VERSION 5.8 ;
BUSBITCHARS "[]" ;
DIVIDERCHAR "/" ;
UNITS
    DATABASE MICRONS 1000 ;
END UNITS

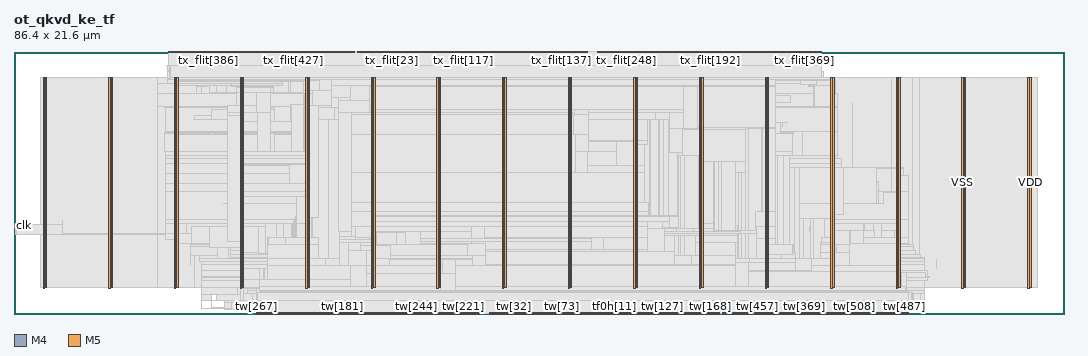
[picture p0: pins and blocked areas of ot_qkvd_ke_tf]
MACRO ot_qkvd_ke_tf
  FOREIGN ot_qkvd_ke_tf 0 0 ;
  CLASS BLOCK ;
  SIZE 86.4 BY 21.6 ;
  PIN clk
    DIRECTION INPUT ;
    USE SIGNAL ;
    PORT
      LAYER M4 ;
        RECT  0 7.248 0.084 7.272 ;
    END
  END clk
  PIN rst_n
    DIRECTION INPUT ;
    USE SIGNAL ;
    PORT
      LAYER M4 ;
        RECT  0 7.344 0.084 7.368 ;
    END
  END rst_n
  PIN tf0h[0]
    DIRECTION INPUT ;
    USE SIGNAL ;
    PORT
      LAYER M5 ;
        RECT  48.336 0 48.36 0.084 ;
    END
  END tf0h[0]
  PIN tf0h[10]
    DIRECTION INPUT ;
    USE SIGNAL ;
    PORT
      LAYER M5 ;
        RECT  49.296 0 49.32 0.084 ;
    END
  END tf0h[10]
  PIN tf0h[11]
    DIRECTION INPUT ;
    USE SIGNAL ;
    PORT
      LAYER M5 ;
        RECT  49.392 0 49.416 0.084 ;
    END
  END tf0h[11]
  PIN tf0h[12]
    DIRECTION INPUT ;
    USE SIGNAL ;
    PORT
      LAYER M5 ;
        RECT  49.488 0 49.512 0.084 ;
    END
  END tf0h[12]
  PIN tf0h[13]
    DIRECTION INPUT ;
    USE SIGNAL ;
    PORT
      LAYER M5 ;
        RECT  49.584 0 49.608 0.084 ;
    END
  END tf0h[13]
  PIN tf0h[14]
    DIRECTION INPUT ;
    USE SIGNAL ;
    PORT
      LAYER M5 ;
        RECT  49.68 0 49.704 0.084 ;
    END
  END tf0h[14]
  PIN tf0h[15]
    DIRECTION INPUT ;
    USE SIGNAL ;
    PORT
      LAYER M5 ;
        RECT  49.776 0 49.8 0.084 ;
    END
  END tf0h[15]
  PIN tf0h[16]
    DIRECTION INPUT ;
    USE SIGNAL ;
    PORT
      LAYER M5 ;
        RECT  49.872 0 49.896 0.084 ;
    END
  END tf0h[16]
  PIN tf0h[17]
    DIRECTION INPUT ;
    USE SIGNAL ;
    PORT
      LAYER M5 ;
        RECT  49.968 0 49.992 0.084 ;
    END
  END tf0h[17]
  PIN tf0h[18]
    DIRECTION INPUT ;
    USE SIGNAL ;
    PORT
      LAYER M5 ;
        RECT  50.064 0 50.088 0.084 ;
    END
  END tf0h[18]
  PIN tf0h[19]
    DIRECTION INPUT ;
    USE SIGNAL ;
    PORT
      LAYER M5 ;
        RECT  50.16 0 50.184 0.084 ;
    END
  END tf0h[19]
  PIN tf0h[1]
    DIRECTION INPUT ;
    USE SIGNAL ;
    PORT
      LAYER M5 ;
        RECT  48.432 0 48.456 0.084 ;
    END
  END tf0h[1]
  PIN tf0h[2]
    DIRECTION INPUT ;
    USE SIGNAL ;
    PORT
      LAYER M5 ;
        RECT  48.528 0 48.552 0.084 ;
    END
  END tf0h[2]
  PIN tf0h[3]
    DIRECTION INPUT ;
    USE SIGNAL ;
    PORT
      LAYER M5 ;
        RECT  48.624 0 48.648 0.084 ;
    END
  END tf0h[3]
  PIN tf0h[4]
    DIRECTION INPUT ;
    USE SIGNAL ;
    PORT
      LAYER M5 ;
        RECT  48.72 0 48.744 0.084 ;
    END
  END tf0h[4]
  PIN tf0h[5]
    DIRECTION INPUT ;
    USE SIGNAL ;
    PORT
      LAYER M5 ;
        RECT  48.816 0 48.84 0.084 ;
    END
  END tf0h[5]
  PIN tf0h[6]
    DIRECTION INPUT ;
    USE SIGNAL ;
    PORT
      LAYER M5 ;
        RECT  48.912 0 48.936 0.084 ;
    END
  END tf0h[6]
  PIN tf0h[7]
    DIRECTION INPUT ;
    USE SIGNAL ;
    PORT
      LAYER M5 ;
        RECT  49.008 0 49.032 0.084 ;
    END
  END tf0h[7]
  PIN tf0h[8]
    DIRECTION INPUT ;
    USE SIGNAL ;
    PORT
      LAYER M5 ;
        RECT  49.104 0 49.128 0.084 ;
    END
  END tf0h[8]
  PIN tf0h[9]
    DIRECTION INPUT ;
    USE SIGNAL ;
    PORT
      LAYER M5 ;
        RECT  49.2 0 49.224 0.084 ;
    END
  END tf0h[9]
  PIN tv0_i
    DIRECTION INPUT ;
    USE SIGNAL ;
    PORT
      LAYER M5 ;
        RECT  50.256 0 50.28 0.084 ;
    END
  END tv0_i
  PIN tw[0]
    DIRECTION INPUT ;
    USE SIGNAL ;
    PORT
      LAYER M5 ;
        RECT  50.352 0 50.376 0.084 ;
    END
  END tw[0]
  PIN tw[100]
    DIRECTION INPUT ;
    USE SIGNAL ;
    PORT
      LAYER M5 ;
        RECT  47.664 0 47.688 0.084 ;
    END
  END tw[100]
  PIN tw[101]
    DIRECTION INPUT ;
    USE SIGNAL ;
    PORT
      LAYER M5 ;
        RECT  47.76 0 47.784 0.084 ;
    END
  END tw[101]
  PIN tw[102]
    DIRECTION INPUT ;
    USE SIGNAL ;
    PORT
      LAYER M5 ;
        RECT  47.856 0 47.88 0.084 ;
    END
  END tw[102]
  PIN tw[103]
    DIRECTION INPUT ;
    USE SIGNAL ;
    PORT
      LAYER M5 ;
        RECT  47.952 0 47.976 0.084 ;
    END
  END tw[103]
  PIN tw[104]
    DIRECTION INPUT ;
    USE SIGNAL ;
    PORT
      LAYER M5 ;
        RECT  48.048 0 48.072 0.084 ;
    END
  END tw[104]
  PIN tw[105]
    DIRECTION INPUT ;
    USE SIGNAL ;
    PORT
      LAYER M5 ;
        RECT  48.144 0 48.168 0.084 ;
    END
  END tw[105]
  PIN tw[106]
    DIRECTION INPUT ;
    USE SIGNAL ;
    PORT
      LAYER M5 ;
        RECT  48.24 0 48.264 0.084 ;
    END
  END tw[106]
  PIN tw[107]
    DIRECTION INPUT ;
    USE SIGNAL ;
    PORT
      LAYER M5 ;
        RECT  51.408 0 51.432 0.084 ;
    END
  END tw[107]
  PIN tw[108]
    DIRECTION INPUT ;
    USE SIGNAL ;
    PORT
      LAYER M5 ;
        RECT  51.504 0 51.528 0.084 ;
    END
  END tw[108]
  PIN tw[109]
    DIRECTION INPUT ;
    USE SIGNAL ;
    PORT
      LAYER M5 ;
        RECT  51.6 0 51.624 0.084 ;
    END
  END tw[109]
  PIN tw[10]
    DIRECTION INPUT ;
    USE SIGNAL ;
    PORT
      LAYER M5 ;
        RECT  51.312 0 51.336 0.084 ;
    END
  END tw[10]
  PIN tw[110]
    DIRECTION INPUT ;
    USE SIGNAL ;
    PORT
      LAYER M5 ;
        RECT  51.696 0 51.72 0.084 ;
    END
  END tw[110]
  PIN tw[111]
    DIRECTION INPUT ;
    USE SIGNAL ;
    PORT
      LAYER M5 ;
        RECT  51.792 0 51.816 0.084 ;
    END
  END tw[111]
  PIN tw[112]
    DIRECTION INPUT ;
    USE SIGNAL ;
    PORT
      LAYER M5 ;
        RECT  51.888 0 51.912 0.084 ;
    END
  END tw[112]
  PIN tw[113]
    DIRECTION INPUT ;
    USE SIGNAL ;
    PORT
      LAYER M5 ;
        RECT  51.984 0 52.008 0.084 ;
    END
  END tw[113]
  PIN tw[114]
    DIRECTION INPUT ;
    USE SIGNAL ;
    PORT
      LAYER M5 ;
        RECT  52.08 0 52.104 0.084 ;
    END
  END tw[114]
  PIN tw[115]
    DIRECTION INPUT ;
    USE SIGNAL ;
    PORT
      LAYER M5 ;
        RECT  52.176 0 52.2 0.084 ;
    END
  END tw[115]
  PIN tw[116]
    DIRECTION INPUT ;
    USE SIGNAL ;
    PORT
      LAYER M5 ;
        RECT  52.272 0 52.296 0.084 ;
    END
  END tw[116]
  PIN tw[117]
    DIRECTION INPUT ;
    USE SIGNAL ;
    PORT
      LAYER M5 ;
        RECT  52.368 0 52.392 0.084 ;
    END
  END tw[117]
  PIN tw[118]
    DIRECTION INPUT ;
    USE SIGNAL ;
    PORT
      LAYER M5 ;
        RECT  52.464 0 52.488 0.084 ;
    END
  END tw[118]
  PIN tw[119]
    DIRECTION INPUT ;
    USE SIGNAL ;
    PORT
      LAYER M5 ;
        RECT  52.56 0 52.584 0.084 ;
    END
  END tw[119]
  PIN tw[11]
    DIRECTION INPUT ;
    USE SIGNAL ;
    PORT
      LAYER M5 ;
        RECT  39.12 0 39.144 0.084 ;
    END
  END tw[11]
  PIN tw[120]
    DIRECTION INPUT ;
    USE SIGNAL ;
    PORT
      LAYER M5 ;
        RECT  52.656 0 52.68 0.084 ;
    END
  END tw[120]
  PIN tw[121]
    DIRECTION INPUT ;
    USE SIGNAL ;
    PORT
      LAYER M5 ;
        RECT  52.752 0 52.776 0.084 ;
    END
  END tw[121]
  PIN tw[122]
    DIRECTION INPUT ;
    USE SIGNAL ;
    PORT
      LAYER M5 ;
        RECT  52.848 0 52.872 0.084 ;
    END
  END tw[122]
  PIN tw[123]
    DIRECTION INPUT ;
    USE SIGNAL ;
    PORT
      LAYER M5 ;
        RECT  52.944 0 52.968 0.084 ;
    END
  END tw[123]
  PIN tw[124]
    DIRECTION INPUT ;
    USE SIGNAL ;
    PORT
      LAYER M5 ;
        RECT  53.04 0 53.064 0.084 ;
    END
  END tw[124]
  PIN tw[125]
    DIRECTION INPUT ;
    USE SIGNAL ;
    PORT
      LAYER M5 ;
        RECT  53.136 0 53.16 0.084 ;
    END
  END tw[125]
  PIN tw[126]
    DIRECTION INPUT ;
    USE SIGNAL ;
    PORT
      LAYER M5 ;
        RECT  53.232 0 53.256 0.084 ;
    END
  END tw[126]
  PIN tw[127]
    DIRECTION INPUT ;
    USE SIGNAL ;
    PORT
      LAYER M5 ;
        RECT  53.328 0 53.352 0.084 ;
    END
  END tw[127]
  PIN tw[128]
    DIRECTION INPUT ;
    USE SIGNAL ;
    PORT
      LAYER M5 ;
        RECT  53.424 0 53.448 0.084 ;
    END
  END tw[128]
  PIN tw[129]
    DIRECTION INPUT ;
    USE SIGNAL ;
    PORT
      LAYER M5 ;
        RECT  53.52 0 53.544 0.084 ;
    END
  END tw[129]
  PIN tw[12]
    DIRECTION INPUT ;
    USE SIGNAL ;
    PORT
      LAYER M5 ;
        RECT  39.216 0 39.24 0.084 ;
    END
  END tw[12]
  PIN tw[130]
    DIRECTION INPUT ;
    USE SIGNAL ;
    PORT
      LAYER M5 ;
        RECT  53.616 0 53.64 0.084 ;
    END
  END tw[130]
  PIN tw[131]
    DIRECTION INPUT ;
    USE SIGNAL ;
    PORT
      LAYER M5 ;
        RECT  53.712 0 53.736 0.084 ;
    END
  END tw[131]
  PIN tw[132]
    DIRECTION INPUT ;
    USE SIGNAL ;
    PORT
      LAYER M5 ;
        RECT  53.808 0 53.832 0.084 ;
    END
  END tw[132]
  PIN tw[133]
    DIRECTION INPUT ;
    USE SIGNAL ;
    PORT
      LAYER M5 ;
        RECT  53.904 0 53.928 0.084 ;
    END
  END tw[133]
  PIN tw[134]
    DIRECTION INPUT ;
    USE SIGNAL ;
    PORT
      LAYER M5 ;
        RECT  54 0 54.024 0.084 ;
    END
  END tw[134]
  PIN tw[135]
    DIRECTION INPUT ;
    USE SIGNAL ;
    PORT
      LAYER M5 ;
        RECT  54.096 0 54.12 0.084 ;
    END
  END tw[135]
  PIN tw[136]
    DIRECTION INPUT ;
    USE SIGNAL ;
    PORT
      LAYER M5 ;
        RECT  54.192 0 54.216 0.084 ;
    END
  END tw[136]
  PIN tw[137]
    DIRECTION INPUT ;
    USE SIGNAL ;
    PORT
      LAYER M5 ;
        RECT  54.288 0 54.312 0.084 ;
    END
  END tw[137]
  PIN tw[138]
    DIRECTION INPUT ;
    USE SIGNAL ;
    PORT
      LAYER M5 ;
        RECT  54.384 0 54.408 0.084 ;
    END
  END tw[138]
  PIN tw[139]
    DIRECTION INPUT ;
    USE SIGNAL ;
    PORT
      LAYER M5 ;
        RECT  54.48 0 54.504 0.084 ;
    END
  END tw[139]
  PIN tw[13]
    DIRECTION INPUT ;
    USE SIGNAL ;
    PORT
      LAYER M5 ;
        RECT  39.312 0 39.336 0.084 ;
    END
  END tw[13]
  PIN tw[140]
    DIRECTION INPUT ;
    USE SIGNAL ;
    PORT
      LAYER M5 ;
        RECT  54.576 0 54.6 0.084 ;
    END
  END tw[140]
  PIN tw[141]
    DIRECTION INPUT ;
    USE SIGNAL ;
    PORT
      LAYER M5 ;
        RECT  54.672 0 54.696 0.084 ;
    END
  END tw[141]
  PIN tw[142]
    DIRECTION INPUT ;
    USE SIGNAL ;
    PORT
      LAYER M5 ;
        RECT  54.768 0 54.792 0.084 ;
    END
  END tw[142]
  PIN tw[143]
    DIRECTION INPUT ;
    USE SIGNAL ;
    PORT
      LAYER M5 ;
        RECT  54.864 0 54.888 0.084 ;
    END
  END tw[143]
  PIN tw[144]
    DIRECTION INPUT ;
    USE SIGNAL ;
    PORT
      LAYER M5 ;
        RECT  54.96 0 54.984 0.084 ;
    END
  END tw[144]
  PIN tw[145]
    DIRECTION INPUT ;
    USE SIGNAL ;
    PORT
      LAYER M5 ;
        RECT  55.056 0 55.08 0.084 ;
    END
  END tw[145]
  PIN tw[146]
    DIRECTION INPUT ;
    USE SIGNAL ;
    PORT
      LAYER M5 ;
        RECT  55.152 0 55.176 0.084 ;
    END
  END tw[146]
  PIN tw[147]
    DIRECTION INPUT ;
    USE SIGNAL ;
    PORT
      LAYER M5 ;
        RECT  55.248 0 55.272 0.084 ;
    END
  END tw[147]
  PIN tw[148]
    DIRECTION INPUT ;
    USE SIGNAL ;
    PORT
      LAYER M5 ;
        RECT  55.344 0 55.368 0.084 ;
    END
  END tw[148]
  PIN tw[149]
    DIRECTION INPUT ;
    USE SIGNAL ;
    PORT
      LAYER M5 ;
        RECT  55.44 0 55.464 0.084 ;
    END
  END tw[149]
  PIN tw[14]
    DIRECTION INPUT ;
    USE SIGNAL ;
    PORT
      LAYER M5 ;
        RECT  39.408 0 39.432 0.084 ;
    END
  END tw[14]
  PIN tw[150]
    DIRECTION INPUT ;
    USE SIGNAL ;
    PORT
      LAYER M5 ;
        RECT  55.536 0 55.56 0.084 ;
    END
  END tw[150]
  PIN tw[151]
    DIRECTION INPUT ;
    USE SIGNAL ;
    PORT
      LAYER M5 ;
        RECT  55.632 0 55.656 0.084 ;
    END
  END tw[151]
  PIN tw[152]
    DIRECTION INPUT ;
    USE SIGNAL ;
    PORT
      LAYER M5 ;
        RECT  55.728 0 55.752 0.084 ;
    END
  END tw[152]
  PIN tw[153]
    DIRECTION INPUT ;
    USE SIGNAL ;
    PORT
      LAYER M5 ;
        RECT  55.824 0 55.848 0.084 ;
    END
  END tw[153]
  PIN tw[154]
    DIRECTION INPUT ;
    USE SIGNAL ;
    PORT
      LAYER M5 ;
        RECT  55.92 0 55.944 0.084 ;
    END
  END tw[154]
  PIN tw[155]
    DIRECTION INPUT ;
    USE SIGNAL ;
    PORT
      LAYER M5 ;
        RECT  56.016 0 56.04 0.084 ;
    END
  END tw[155]
  PIN tw[156]
    DIRECTION INPUT ;
    USE SIGNAL ;
    PORT
      LAYER M5 ;
        RECT  56.112 0 56.136 0.084 ;
    END
  END tw[156]
  PIN tw[157]
    DIRECTION INPUT ;
    USE SIGNAL ;
    PORT
      LAYER M5 ;
        RECT  56.208 0 56.232 0.084 ;
    END
  END tw[157]
  PIN tw[158]
    DIRECTION INPUT ;
    USE SIGNAL ;
    PORT
      LAYER M5 ;
        RECT  56.304 0 56.328 0.084 ;
    END
  END tw[158]
  PIN tw[159]
    DIRECTION INPUT ;
    USE SIGNAL ;
    PORT
      LAYER M5 ;
        RECT  56.4 0 56.424 0.084 ;
    END
  END tw[159]
  PIN tw[15]
    DIRECTION INPUT ;
    USE SIGNAL ;
    PORT
      LAYER M5 ;
        RECT  39.504 0 39.528 0.084 ;
    END
  END tw[15]
  PIN tw[160]
    DIRECTION INPUT ;
    USE SIGNAL ;
    PORT
      LAYER M5 ;
        RECT  56.496 0 56.52 0.084 ;
    END
  END tw[160]
  PIN tw[161]
    DIRECTION INPUT ;
    USE SIGNAL ;
    PORT
      LAYER M5 ;
        RECT  56.592 0 56.616 0.084 ;
    END
  END tw[161]
  PIN tw[162]
    DIRECTION INPUT ;
    USE SIGNAL ;
    PORT
      LAYER M5 ;
        RECT  56.688 0 56.712 0.084 ;
    END
  END tw[162]
  PIN tw[163]
    DIRECTION INPUT ;
    USE SIGNAL ;
    PORT
      LAYER M5 ;
        RECT  56.784 0 56.808 0.084 ;
    END
  END tw[163]
  PIN tw[164]
    DIRECTION INPUT ;
    USE SIGNAL ;
    PORT
      LAYER M5 ;
        RECT  56.88 0 56.904 0.084 ;
    END
  END tw[164]
  PIN tw[165]
    DIRECTION INPUT ;
    USE SIGNAL ;
    PORT
      LAYER M5 ;
        RECT  56.976 0 57 0.084 ;
    END
  END tw[165]
  PIN tw[166]
    DIRECTION INPUT ;
    USE SIGNAL ;
    PORT
      LAYER M5 ;
        RECT  57.072 0 57.096 0.084 ;
    END
  END tw[166]
  PIN tw[167]
    DIRECTION INPUT ;
    USE SIGNAL ;
    PORT
      LAYER M5 ;
        RECT  57.168 0 57.192 0.084 ;
    END
  END tw[167]
  PIN tw[168]
    DIRECTION INPUT ;
    USE SIGNAL ;
    PORT
      LAYER M5 ;
        RECT  57.264 0 57.288 0.084 ;
    END
  END tw[168]
  PIN tw[169]
    DIRECTION INPUT ;
    USE SIGNAL ;
    PORT
      LAYER M5 ;
        RECT  57.36 0 57.384 0.084 ;
    END
  END tw[169]
  PIN tw[16]
    DIRECTION INPUT ;
    USE SIGNAL ;
    PORT
      LAYER M5 ;
        RECT  39.6 0 39.624 0.084 ;
    END
  END tw[16]
  PIN tw[170]
    DIRECTION INPUT ;
    USE SIGNAL ;
    PORT
      LAYER M5 ;
        RECT  57.456 0 57.48 0.084 ;
    END
  END tw[170]
  PIN tw[171]
    DIRECTION INPUT ;
    USE SIGNAL ;
    PORT
      LAYER M5 ;
        RECT  26.064 0 26.088 0.084 ;
    END
  END tw[171]
  PIN tw[172]
    DIRECTION INPUT ;
    USE SIGNAL ;
    PORT
      LAYER M5 ;
        RECT  26.16 0 26.184 0.084 ;
    END
  END tw[172]
  PIN tw[173]
    DIRECTION INPUT ;
    USE SIGNAL ;
    PORT
      LAYER M5 ;
        RECT  26.256 0 26.28 0.084 ;
    END
  END tw[173]
  PIN tw[174]
    DIRECTION INPUT ;
    USE SIGNAL ;
    PORT
      LAYER M5 ;
        RECT  26.352 0 26.376 0.084 ;
    END
  END tw[174]
  PIN tw[175]
    DIRECTION INPUT ;
    USE SIGNAL ;
    PORT
      LAYER M5 ;
        RECT  26.448 0 26.472 0.084 ;
    END
  END tw[175]
  PIN tw[176]
    DIRECTION INPUT ;
    USE SIGNAL ;
    PORT
      LAYER M5 ;
        RECT  26.544 0 26.568 0.084 ;
    END
  END tw[176]
  PIN tw[177]
    DIRECTION INPUT ;
    USE SIGNAL ;
    PORT
      LAYER M5 ;
        RECT  26.64 0 26.664 0.084 ;
    END
  END tw[177]
  PIN tw[178]
    DIRECTION INPUT ;
    USE SIGNAL ;
    PORT
      LAYER M5 ;
        RECT  26.736 0 26.76 0.084 ;
    END
  END tw[178]
  PIN tw[179]
    DIRECTION INPUT ;
    USE SIGNAL ;
    PORT
      LAYER M5 ;
        RECT  26.832 0 26.856 0.084 ;
    END
  END tw[179]
  PIN tw[17]
    DIRECTION INPUT ;
    USE SIGNAL ;
    PORT
      LAYER M5 ;
        RECT  39.696 0 39.72 0.084 ;
    END
  END tw[17]
  PIN tw[180]
    DIRECTION INPUT ;
    USE SIGNAL ;
    PORT
      LAYER M5 ;
        RECT  26.928 0 26.952 0.084 ;
    END
  END tw[180]
  PIN tw[181]
    DIRECTION INPUT ;
    USE SIGNAL ;
    PORT
      LAYER M5 ;
        RECT  27.024 0 27.048 0.084 ;
    END
  END tw[181]
  PIN tw[182]
    DIRECTION INPUT ;
    USE SIGNAL ;
    PORT
      LAYER M5 ;
        RECT  27.12 0 27.144 0.084 ;
    END
  END tw[182]
  PIN tw[183]
    DIRECTION INPUT ;
    USE SIGNAL ;
    PORT
      LAYER M5 ;
        RECT  27.216 0 27.24 0.084 ;
    END
  END tw[183]
  PIN tw[184]
    DIRECTION INPUT ;
    USE SIGNAL ;
    PORT
      LAYER M5 ;
        RECT  27.312 0 27.336 0.084 ;
    END
  END tw[184]
  PIN tw[185]
    DIRECTION INPUT ;
    USE SIGNAL ;
    PORT
      LAYER M5 ;
        RECT  27.408 0 27.432 0.084 ;
    END
  END tw[185]
  PIN tw[186]
    DIRECTION INPUT ;
    USE SIGNAL ;
    PORT
      LAYER M5 ;
        RECT  27.504 0 27.528 0.084 ;
    END
  END tw[186]
  PIN tw[187]
    DIRECTION INPUT ;
    USE SIGNAL ;
    PORT
      LAYER M5 ;
        RECT  27.6 0 27.624 0.084 ;
    END
  END tw[187]
  PIN tw[188]
    DIRECTION INPUT ;
    USE SIGNAL ;
    PORT
      LAYER M5 ;
        RECT  27.696 0 27.72 0.084 ;
    END
  END tw[188]
  PIN tw[189]
    DIRECTION INPUT ;
    USE SIGNAL ;
    PORT
      LAYER M5 ;
        RECT  27.792 0 27.816 0.084 ;
    END
  END tw[189]
  PIN tw[18]
    DIRECTION INPUT ;
    USE SIGNAL ;
    PORT
      LAYER M5 ;
        RECT  39.792 0 39.816 0.084 ;
    END
  END tw[18]
  PIN tw[190]
    DIRECTION INPUT ;
    USE SIGNAL ;
    PORT
      LAYER M5 ;
        RECT  27.888 0 27.912 0.084 ;
    END
  END tw[190]
  PIN tw[191]
    DIRECTION INPUT ;
    USE SIGNAL ;
    PORT
      LAYER M5 ;
        RECT  27.984 0 28.008 0.084 ;
    END
  END tw[191]
  PIN tw[192]
    DIRECTION INPUT ;
    USE SIGNAL ;
    PORT
      LAYER M5 ;
        RECT  28.08 0 28.104 0.084 ;
    END
  END tw[192]
  PIN tw[193]
    DIRECTION INPUT ;
    USE SIGNAL ;
    PORT
      LAYER M5 ;
        RECT  28.176 0 28.2 0.084 ;
    END
  END tw[193]
  PIN tw[194]
    DIRECTION INPUT ;
    USE SIGNAL ;
    PORT
      LAYER M5 ;
        RECT  28.272 0 28.296 0.084 ;
    END
  END tw[194]
  PIN tw[195]
    DIRECTION INPUT ;
    USE SIGNAL ;
    PORT
      LAYER M5 ;
        RECT  28.368 0 28.392 0.084 ;
    END
  END tw[195]
  PIN tw[196]
    DIRECTION INPUT ;
    USE SIGNAL ;
    PORT
      LAYER M5 ;
        RECT  28.464 0 28.488 0.084 ;
    END
  END tw[196]
  PIN tw[197]
    DIRECTION INPUT ;
    USE SIGNAL ;
    PORT
      LAYER M5 ;
        RECT  28.56 0 28.584 0.084 ;
    END
  END tw[197]
  PIN tw[198]
    DIRECTION INPUT ;
    USE SIGNAL ;
    PORT
      LAYER M5 ;
        RECT  28.656 0 28.68 0.084 ;
    END
  END tw[198]
  PIN tw[199]
    DIRECTION INPUT ;
    USE SIGNAL ;
    PORT
      LAYER M5 ;
        RECT  28.752 0 28.776 0.084 ;
    END
  END tw[199]
  PIN tw[19]
    DIRECTION INPUT ;
    USE SIGNAL ;
    PORT
      LAYER M5 ;
        RECT  39.888 0 39.912 0.084 ;
    END
  END tw[19]
  PIN tw[1]
    DIRECTION INPUT ;
    USE SIGNAL ;
    PORT
      LAYER M5 ;
        RECT  50.448 0 50.472 0.084 ;
    END
  END tw[1]
  PIN tw[200]
    DIRECTION INPUT ;
    USE SIGNAL ;
    PORT
      LAYER M5 ;
        RECT  28.848 0 28.872 0.084 ;
    END
  END tw[200]
  PIN tw[201]
    DIRECTION INPUT ;
    USE SIGNAL ;
    PORT
      LAYER M5 ;
        RECT  28.944 0 28.968 0.084 ;
    END
  END tw[201]
  PIN tw[202]
    DIRECTION INPUT ;
    USE SIGNAL ;
    PORT
      LAYER M5 ;
        RECT  29.04 0 29.064 0.084 ;
    END
  END tw[202]
  PIN tw[203]
    DIRECTION INPUT ;
    USE SIGNAL ;
    PORT
      LAYER M5 ;
        RECT  35.28 0 35.304 0.084 ;
    END
  END tw[203]
  PIN tw[204]
    DIRECTION INPUT ;
    USE SIGNAL ;
    PORT
      LAYER M5 ;
        RECT  35.376 0 35.4 0.084 ;
    END
  END tw[204]
  PIN tw[205]
    DIRECTION INPUT ;
    USE SIGNAL ;
    PORT
      LAYER M5 ;
        RECT  35.472 0 35.496 0.084 ;
    END
  END tw[205]
  PIN tw[206]
    DIRECTION INPUT ;
    USE SIGNAL ;
    PORT
      LAYER M5 ;
        RECT  35.568 0 35.592 0.084 ;
    END
  END tw[206]
  PIN tw[207]
    DIRECTION INPUT ;
    USE SIGNAL ;
    PORT
      LAYER M5 ;
        RECT  35.664 0 35.688 0.084 ;
    END
  END tw[207]
  PIN tw[208]
    DIRECTION INPUT ;
    USE SIGNAL ;
    PORT
      LAYER M5 ;
        RECT  35.76 0 35.784 0.084 ;
    END
  END tw[208]
  PIN tw[209]
    DIRECTION INPUT ;
    USE SIGNAL ;
    PORT
      LAYER M5 ;
        RECT  35.856 0 35.88 0.084 ;
    END
  END tw[209]
  PIN tw[20]
    DIRECTION INPUT ;
    USE SIGNAL ;
    PORT
      LAYER M5 ;
        RECT  39.984 0 40.008 0.084 ;
    END
  END tw[20]
  PIN tw[210]
    DIRECTION INPUT ;
    USE SIGNAL ;
    PORT
      LAYER M5 ;
        RECT  35.952 0 35.976 0.084 ;
    END
  END tw[210]
  PIN tw[211]
    DIRECTION INPUT ;
    USE SIGNAL ;
    PORT
      LAYER M5 ;
        RECT  36.048 0 36.072 0.084 ;
    END
  END tw[211]
  PIN tw[212]
    DIRECTION INPUT ;
    USE SIGNAL ;
    PORT
      LAYER M5 ;
        RECT  36.144 0 36.168 0.084 ;
    END
  END tw[212]
  PIN tw[213]
    DIRECTION INPUT ;
    USE SIGNAL ;
    PORT
      LAYER M5 ;
        RECT  36.24 0 36.264 0.084 ;
    END
  END tw[213]
  PIN tw[214]
    DIRECTION INPUT ;
    USE SIGNAL ;
    PORT
      LAYER M5 ;
        RECT  36.336 0 36.36 0.084 ;
    END
  END tw[214]
  PIN tw[215]
    DIRECTION INPUT ;
    USE SIGNAL ;
    PORT
      LAYER M5 ;
        RECT  36.432 0 36.456 0.084 ;
    END
  END tw[215]
  PIN tw[216]
    DIRECTION INPUT ;
    USE SIGNAL ;
    PORT
      LAYER M5 ;
        RECT  36.528 0 36.552 0.084 ;
    END
  END tw[216]
  PIN tw[217]
    DIRECTION INPUT ;
    USE SIGNAL ;
    PORT
      LAYER M5 ;
        RECT  36.624 0 36.648 0.084 ;
    END
  END tw[217]
  PIN tw[218]
    DIRECTION INPUT ;
    USE SIGNAL ;
    PORT
      LAYER M5 ;
        RECT  36.72 0 36.744 0.084 ;
    END
  END tw[218]
  PIN tw[219]
    DIRECTION INPUT ;
    USE SIGNAL ;
    PORT
      LAYER M5 ;
        RECT  36.816 0 36.84 0.084 ;
    END
  END tw[219]
  PIN tw[21]
    DIRECTION INPUT ;
    USE SIGNAL ;
    PORT
      LAYER M5 ;
        RECT  40.08 0 40.104 0.084 ;
    END
  END tw[21]
  PIN tw[220]
    DIRECTION INPUT ;
    USE SIGNAL ;
    PORT
      LAYER M5 ;
        RECT  36.912 0 36.936 0.084 ;
    END
  END tw[220]
  PIN tw[221]
    DIRECTION INPUT ;
    USE SIGNAL ;
    PORT
      LAYER M5 ;
        RECT  37.008 0 37.032 0.084 ;
    END
  END tw[221]
  PIN tw[222]
    DIRECTION INPUT ;
    USE SIGNAL ;
    PORT
      LAYER M5 ;
        RECT  37.104 0 37.128 0.084 ;
    END
  END tw[222]
  PIN tw[223]
    DIRECTION INPUT ;
    USE SIGNAL ;
    PORT
      LAYER M5 ;
        RECT  37.2 0 37.224 0.084 ;
    END
  END tw[223]
  PIN tw[224]
    DIRECTION INPUT ;
    USE SIGNAL ;
    PORT
      LAYER M5 ;
        RECT  37.296 0 37.32 0.084 ;
    END
  END tw[224]
  PIN tw[225]
    DIRECTION INPUT ;
    USE SIGNAL ;
    PORT
      LAYER M5 ;
        RECT  37.392 0 37.416 0.084 ;
    END
  END tw[225]
  PIN tw[226]
    DIRECTION INPUT ;
    USE SIGNAL ;
    PORT
      LAYER M5 ;
        RECT  37.488 0 37.512 0.084 ;
    END
  END tw[226]
  PIN tw[227]
    DIRECTION INPUT ;
    USE SIGNAL ;
    PORT
      LAYER M5 ;
        RECT  37.584 0 37.608 0.084 ;
    END
  END tw[227]
  PIN tw[228]
    DIRECTION INPUT ;
    USE SIGNAL ;
    PORT
      LAYER M5 ;
        RECT  37.68 0 37.704 0.084 ;
    END
  END tw[228]
  PIN tw[229]
    DIRECTION INPUT ;
    USE SIGNAL ;
    PORT
      LAYER M5 ;
        RECT  37.776 0 37.8 0.084 ;
    END
  END tw[229]
  PIN tw[22]
    DIRECTION INPUT ;
    USE SIGNAL ;
    PORT
      LAYER M5 ;
        RECT  40.176 0 40.2 0.084 ;
    END
  END tw[22]
  PIN tw[230]
    DIRECTION INPUT ;
    USE SIGNAL ;
    PORT
      LAYER M5 ;
        RECT  37.872 0 37.896 0.084 ;
    END
  END tw[230]
  PIN tw[231]
    DIRECTION INPUT ;
    USE SIGNAL ;
    PORT
      LAYER M5 ;
        RECT  37.968 0 37.992 0.084 ;
    END
  END tw[231]
  PIN tw[232]
    DIRECTION INPUT ;
    USE SIGNAL ;
    PORT
      LAYER M5 ;
        RECT  38.064 0 38.088 0.084 ;
    END
  END tw[232]
  PIN tw[233]
    DIRECTION INPUT ;
    USE SIGNAL ;
    PORT
      LAYER M5 ;
        RECT  38.16 0 38.184 0.084 ;
    END
  END tw[233]
  PIN tw[234]
    DIRECTION INPUT ;
    USE SIGNAL ;
    PORT
      LAYER M5 ;
        RECT  38.256 0 38.28 0.084 ;
    END
  END tw[234]
  PIN tw[235]
    DIRECTION INPUT ;
    USE SIGNAL ;
    PORT
      LAYER M5 ;
        RECT  32.208 0 32.232 0.084 ;
    END
  END tw[235]
  PIN tw[236]
    DIRECTION INPUT ;
    USE SIGNAL ;
    PORT
      LAYER M5 ;
        RECT  32.304 0 32.328 0.084 ;
    END
  END tw[236]
  PIN tw[237]
    DIRECTION INPUT ;
    USE SIGNAL ;
    PORT
      LAYER M5 ;
        RECT  32.4 0 32.424 0.084 ;
    END
  END tw[237]
  PIN tw[238]
    DIRECTION INPUT ;
    USE SIGNAL ;
    PORT
      LAYER M5 ;
        RECT  32.496 0 32.52 0.084 ;
    END
  END tw[238]
  PIN tw[239]
    DIRECTION INPUT ;
    USE SIGNAL ;
    PORT
      LAYER M5 ;
        RECT  32.592 0 32.616 0.084 ;
    END
  END tw[239]
  PIN tw[23]
    DIRECTION INPUT ;
    USE SIGNAL ;
    PORT
      LAYER M5 ;
        RECT  40.272 0 40.296 0.084 ;
    END
  END tw[23]
  PIN tw[240]
    DIRECTION INPUT ;
    USE SIGNAL ;
    PORT
      LAYER M5 ;
        RECT  32.688 0 32.712 0.084 ;
    END
  END tw[240]
  PIN tw[241]
    DIRECTION INPUT ;
    USE SIGNAL ;
    PORT
      LAYER M5 ;
        RECT  32.784 0 32.808 0.084 ;
    END
  END tw[241]
  PIN tw[242]
    DIRECTION INPUT ;
    USE SIGNAL ;
    PORT
      LAYER M5 ;
        RECT  32.88 0 32.904 0.084 ;
    END
  END tw[242]
  PIN tw[243]
    DIRECTION INPUT ;
    USE SIGNAL ;
    PORT
      LAYER M5 ;
        RECT  32.976 0 33 0.084 ;
    END
  END tw[243]
  PIN tw[244]
    DIRECTION INPUT ;
    USE SIGNAL ;
    PORT
      LAYER M5 ;
        RECT  33.072 0 33.096 0.084 ;
    END
  END tw[244]
  PIN tw[245]
    DIRECTION INPUT ;
    USE SIGNAL ;
    PORT
      LAYER M5 ;
        RECT  33.168 0 33.192 0.084 ;
    END
  END tw[245]
  PIN tw[246]
    DIRECTION INPUT ;
    USE SIGNAL ;
    PORT
      LAYER M5 ;
        RECT  33.264 0 33.288 0.084 ;
    END
  END tw[246]
  PIN tw[247]
    DIRECTION INPUT ;
    USE SIGNAL ;
    PORT
      LAYER M5 ;
        RECT  33.36 0 33.384 0.084 ;
    END
  END tw[247]
  PIN tw[248]
    DIRECTION INPUT ;
    USE SIGNAL ;
    PORT
      LAYER M5 ;
        RECT  33.456 0 33.48 0.084 ;
    END
  END tw[248]
  PIN tw[249]
    DIRECTION INPUT ;
    USE SIGNAL ;
    PORT
      LAYER M5 ;
        RECT  33.552 0 33.576 0.084 ;
    END
  END tw[249]
  PIN tw[24]
    DIRECTION INPUT ;
    USE SIGNAL ;
    PORT
      LAYER M5 ;
        RECT  40.368 0 40.392 0.084 ;
    END
  END tw[24]
  PIN tw[250]
    DIRECTION INPUT ;
    USE SIGNAL ;
    PORT
      LAYER M5 ;
        RECT  33.648 0 33.672 0.084 ;
    END
  END tw[250]
  PIN tw[251]
    DIRECTION INPUT ;
    USE SIGNAL ;
    PORT
      LAYER M5 ;
        RECT  33.744 0 33.768 0.084 ;
    END
  END tw[251]
  PIN tw[252]
    DIRECTION INPUT ;
    USE SIGNAL ;
    PORT
      LAYER M5 ;
        RECT  33.84 0 33.864 0.084 ;
    END
  END tw[252]
  PIN tw[253]
    DIRECTION INPUT ;
    USE SIGNAL ;
    PORT
      LAYER M5 ;
        RECT  33.936 0 33.96 0.084 ;
    END
  END tw[253]
  PIN tw[254]
    DIRECTION INPUT ;
    USE SIGNAL ;
    PORT
      LAYER M5 ;
        RECT  34.032 0 34.056 0.084 ;
    END
  END tw[254]
  PIN tw[255]
    DIRECTION INPUT ;
    USE SIGNAL ;
    PORT
      LAYER M5 ;
        RECT  34.128 0 34.152 0.084 ;
    END
  END tw[255]
  PIN tw[256]
    DIRECTION INPUT ;
    USE SIGNAL ;
    PORT
      LAYER M5 ;
        RECT  34.224 0 34.248 0.084 ;
    END
  END tw[256]
  PIN tw[257]
    DIRECTION INPUT ;
    USE SIGNAL ;
    PORT
      LAYER M5 ;
        RECT  34.32 0 34.344 0.084 ;
    END
  END tw[257]
  PIN tw[258]
    DIRECTION INPUT ;
    USE SIGNAL ;
    PORT
      LAYER M5 ;
        RECT  34.416 0 34.44 0.084 ;
    END
  END tw[258]
  PIN tw[259]
    DIRECTION INPUT ;
    USE SIGNAL ;
    PORT
      LAYER M5 ;
        RECT  34.512 0 34.536 0.084 ;
    END
  END tw[259]
  PIN tw[25]
    DIRECTION INPUT ;
    USE SIGNAL ;
    PORT
      LAYER M5 ;
        RECT  40.464 0 40.488 0.084 ;
    END
  END tw[25]
  PIN tw[260]
    DIRECTION INPUT ;
    USE SIGNAL ;
    PORT
      LAYER M5 ;
        RECT  34.608 0 34.632 0.084 ;
    END
  END tw[260]
  PIN tw[261]
    DIRECTION INPUT ;
    USE SIGNAL ;
    PORT
      LAYER M5 ;
        RECT  34.704 0 34.728 0.084 ;
    END
  END tw[261]
  PIN tw[262]
    DIRECTION INPUT ;
    USE SIGNAL ;
    PORT
      LAYER M5 ;
        RECT  34.8 0 34.824 0.084 ;
    END
  END tw[262]
  PIN tw[263]
    DIRECTION INPUT ;
    USE SIGNAL ;
    PORT
      LAYER M5 ;
        RECT  34.896 0 34.92 0.084 ;
    END
  END tw[263]
  PIN tw[264]
    DIRECTION INPUT ;
    USE SIGNAL ;
    PORT
      LAYER M5 ;
        RECT  34.992 0 35.016 0.084 ;
    END
  END tw[264]
  PIN tw[265]
    DIRECTION INPUT ;
    USE SIGNAL ;
    PORT
      LAYER M5 ;
        RECT  35.088 0 35.112 0.084 ;
    END
  END tw[265]
  PIN tw[266]
    DIRECTION INPUT ;
    USE SIGNAL ;
    PORT
      LAYER M5 ;
        RECT  35.184 0 35.208 0.084 ;
    END
  END tw[266]
  PIN tw[267]
    DIRECTION INPUT ;
    USE SIGNAL ;
    PORT
      LAYER M5 ;
        RECT  19.92 0 19.944 0.084 ;
    END
  END tw[267]
  PIN tw[268]
    DIRECTION INPUT ;
    USE SIGNAL ;
    PORT
      LAYER M5 ;
        RECT  20.016 0 20.04 0.084 ;
    END
  END tw[268]
  PIN tw[269]
    DIRECTION INPUT ;
    USE SIGNAL ;
    PORT
      LAYER M5 ;
        RECT  20.112 0 20.136 0.084 ;
    END
  END tw[269]
  PIN tw[26]
    DIRECTION INPUT ;
    USE SIGNAL ;
    PORT
      LAYER M5 ;
        RECT  40.56 0 40.584 0.084 ;
    END
  END tw[26]
  PIN tw[270]
    DIRECTION INPUT ;
    USE SIGNAL ;
    PORT
      LAYER M5 ;
        RECT  20.208 0 20.232 0.084 ;
    END
  END tw[270]
  PIN tw[271]
    DIRECTION INPUT ;
    USE SIGNAL ;
    PORT
      LAYER M5 ;
        RECT  20.304 0 20.328 0.084 ;
    END
  END tw[271]
  PIN tw[272]
    DIRECTION INPUT ;
    USE SIGNAL ;
    PORT
      LAYER M5 ;
        RECT  20.4 0 20.424 0.084 ;
    END
  END tw[272]
  PIN tw[273]
    DIRECTION INPUT ;
    USE SIGNAL ;
    PORT
      LAYER M5 ;
        RECT  20.496 0 20.52 0.084 ;
    END
  END tw[273]
  PIN tw[274]
    DIRECTION INPUT ;
    USE SIGNAL ;
    PORT
      LAYER M5 ;
        RECT  20.592 0 20.616 0.084 ;
    END
  END tw[274]
  PIN tw[275]
    DIRECTION INPUT ;
    USE SIGNAL ;
    PORT
      LAYER M5 ;
        RECT  20.688 0 20.712 0.084 ;
    END
  END tw[275]
  PIN tw[276]
    DIRECTION INPUT ;
    USE SIGNAL ;
    PORT
      LAYER M5 ;
        RECT  20.784 0 20.808 0.084 ;
    END
  END tw[276]
  PIN tw[277]
    DIRECTION INPUT ;
    USE SIGNAL ;
    PORT
      LAYER M5 ;
        RECT  20.88 0 20.904 0.084 ;
    END
  END tw[277]
  PIN tw[278]
    DIRECTION INPUT ;
    USE SIGNAL ;
    PORT
      LAYER M5 ;
        RECT  20.976 0 21 0.084 ;
    END
  END tw[278]
  PIN tw[279]
    DIRECTION INPUT ;
    USE SIGNAL ;
    PORT
      LAYER M5 ;
        RECT  21.072 0 21.096 0.084 ;
    END
  END tw[279]
  PIN tw[27]
    DIRECTION INPUT ;
    USE SIGNAL ;
    PORT
      LAYER M5 ;
        RECT  40.656 0 40.68 0.084 ;
    END
  END tw[27]
  PIN tw[280]
    DIRECTION INPUT ;
    USE SIGNAL ;
    PORT
      LAYER M5 ;
        RECT  21.168 0 21.192 0.084 ;
    END
  END tw[280]
  PIN tw[281]
    DIRECTION INPUT ;
    USE SIGNAL ;
    PORT
      LAYER M5 ;
        RECT  21.264 0 21.288 0.084 ;
    END
  END tw[281]
  PIN tw[282]
    DIRECTION INPUT ;
    USE SIGNAL ;
    PORT
      LAYER M5 ;
        RECT  21.36 0 21.384 0.084 ;
    END
  END tw[282]
  PIN tw[283]
    DIRECTION INPUT ;
    USE SIGNAL ;
    PORT
      LAYER M5 ;
        RECT  21.456 0 21.48 0.084 ;
    END
  END tw[283]
  PIN tw[284]
    DIRECTION INPUT ;
    USE SIGNAL ;
    PORT
      LAYER M5 ;
        RECT  21.552 0 21.576 0.084 ;
    END
  END tw[284]
  PIN tw[285]
    DIRECTION INPUT ;
    USE SIGNAL ;
    PORT
      LAYER M5 ;
        RECT  21.648 0 21.672 0.084 ;
    END
  END tw[285]
  PIN tw[286]
    DIRECTION INPUT ;
    USE SIGNAL ;
    PORT
      LAYER M5 ;
        RECT  21.744 0 21.768 0.084 ;
    END
  END tw[286]
  PIN tw[287]
    DIRECTION INPUT ;
    USE SIGNAL ;
    PORT
      LAYER M5 ;
        RECT  21.84 0 21.864 0.084 ;
    END
  END tw[287]
  PIN tw[288]
    DIRECTION INPUT ;
    USE SIGNAL ;
    PORT
      LAYER M5 ;
        RECT  21.936 0 21.96 0.084 ;
    END
  END tw[288]
  PIN tw[289]
    DIRECTION INPUT ;
    USE SIGNAL ;
    PORT
      LAYER M5 ;
        RECT  22.032 0 22.056 0.084 ;
    END
  END tw[289]
  PIN tw[28]
    DIRECTION INPUT ;
    USE SIGNAL ;
    PORT
      LAYER M5 ;
        RECT  40.752 0 40.776 0.084 ;
    END
  END tw[28]
  PIN tw[290]
    DIRECTION INPUT ;
    USE SIGNAL ;
    PORT
      LAYER M5 ;
        RECT  22.128 0 22.152 0.084 ;
    END
  END tw[290]
  PIN tw[291]
    DIRECTION INPUT ;
    USE SIGNAL ;
    PORT
      LAYER M5 ;
        RECT  22.224 0 22.248 0.084 ;
    END
  END tw[291]
  PIN tw[292]
    DIRECTION INPUT ;
    USE SIGNAL ;
    PORT
      LAYER M5 ;
        RECT  22.32 0 22.344 0.084 ;
    END
  END tw[292]
  PIN tw[293]
    DIRECTION INPUT ;
    USE SIGNAL ;
    PORT
      LAYER M5 ;
        RECT  22.416 0 22.44 0.084 ;
    END
  END tw[293]
  PIN tw[294]
    DIRECTION INPUT ;
    USE SIGNAL ;
    PORT
      LAYER M5 ;
        RECT  22.512 0 22.536 0.084 ;
    END
  END tw[294]
  PIN tw[295]
    DIRECTION INPUT ;
    USE SIGNAL ;
    PORT
      LAYER M5 ;
        RECT  22.608 0 22.632 0.084 ;
    END
  END tw[295]
  PIN tw[296]
    DIRECTION INPUT ;
    USE SIGNAL ;
    PORT
      LAYER M5 ;
        RECT  22.704 0 22.728 0.084 ;
    END
  END tw[296]
  PIN tw[297]
    DIRECTION INPUT ;
    USE SIGNAL ;
    PORT
      LAYER M5 ;
        RECT  22.8 0 22.824 0.084 ;
    END
  END tw[297]
  PIN tw[298]
    DIRECTION INPUT ;
    USE SIGNAL ;
    PORT
      LAYER M5 ;
        RECT  22.896 0 22.92 0.084 ;
    END
  END tw[298]
  PIN tw[299]
    DIRECTION INPUT ;
    USE SIGNAL ;
    PORT
      LAYER M5 ;
        RECT  22.992 0 23.016 0.084 ;
    END
  END tw[299]
  PIN tw[29]
    DIRECTION INPUT ;
    USE SIGNAL ;
    PORT
      LAYER M5 ;
        RECT  40.848 0 40.872 0.084 ;
    END
  END tw[29]
  PIN tw[2]
    DIRECTION INPUT ;
    USE SIGNAL ;
    PORT
      LAYER M5 ;
        RECT  50.544 0 50.568 0.084 ;
    END
  END tw[2]
  PIN tw[300]
    DIRECTION INPUT ;
    USE SIGNAL ;
    PORT
      LAYER M5 ;
        RECT  23.088 0 23.112 0.084 ;
    END
  END tw[300]
  PIN tw[301]
    DIRECTION INPUT ;
    USE SIGNAL ;
    PORT
      LAYER M5 ;
        RECT  23.184 0 23.208 0.084 ;
    END
  END tw[301]
  PIN tw[302]
    DIRECTION INPUT ;
    USE SIGNAL ;
    PORT
      LAYER M5 ;
        RECT  23.28 0 23.304 0.084 ;
    END
  END tw[302]
  PIN tw[303]
    DIRECTION INPUT ;
    USE SIGNAL ;
    PORT
      LAYER M5 ;
        RECT  23.376 0 23.4 0.084 ;
    END
  END tw[303]
  PIN tw[304]
    DIRECTION INPUT ;
    USE SIGNAL ;
    PORT
      LAYER M5 ;
        RECT  23.472 0 23.496 0.084 ;
    END
  END tw[304]
  PIN tw[305]
    DIRECTION INPUT ;
    USE SIGNAL ;
    PORT
      LAYER M5 ;
        RECT  23.568 0 23.592 0.084 ;
    END
  END tw[305]
  PIN tw[306]
    DIRECTION INPUT ;
    USE SIGNAL ;
    PORT
      LAYER M5 ;
        RECT  23.664 0 23.688 0.084 ;
    END
  END tw[306]
  PIN tw[307]
    DIRECTION INPUT ;
    USE SIGNAL ;
    PORT
      LAYER M5 ;
        RECT  23.76 0 23.784 0.084 ;
    END
  END tw[307]
  PIN tw[308]
    DIRECTION INPUT ;
    USE SIGNAL ;
    PORT
      LAYER M5 ;
        RECT  23.856 0 23.88 0.084 ;
    END
  END tw[308]
  PIN tw[309]
    DIRECTION INPUT ;
    USE SIGNAL ;
    PORT
      LAYER M5 ;
        RECT  23.952 0 23.976 0.084 ;
    END
  END tw[309]
  PIN tw[30]
    DIRECTION INPUT ;
    USE SIGNAL ;
    PORT
      LAYER M5 ;
        RECT  40.944 0 40.968 0.084 ;
    END
  END tw[30]
  PIN tw[310]
    DIRECTION INPUT ;
    USE SIGNAL ;
    PORT
      LAYER M5 ;
        RECT  24.048 0 24.072 0.084 ;
    END
  END tw[310]
  PIN tw[311]
    DIRECTION INPUT ;
    USE SIGNAL ;
    PORT
      LAYER M5 ;
        RECT  24.144 0 24.168 0.084 ;
    END
  END tw[311]
  PIN tw[312]
    DIRECTION INPUT ;
    USE SIGNAL ;
    PORT
      LAYER M5 ;
        RECT  24.24 0 24.264 0.084 ;
    END
  END tw[312]
  PIN tw[313]
    DIRECTION INPUT ;
    USE SIGNAL ;
    PORT
      LAYER M5 ;
        RECT  24.336 0 24.36 0.084 ;
    END
  END tw[313]
  PIN tw[314]
    DIRECTION INPUT ;
    USE SIGNAL ;
    PORT
      LAYER M5 ;
        RECT  24.432 0 24.456 0.084 ;
    END
  END tw[314]
  PIN tw[315]
    DIRECTION INPUT ;
    USE SIGNAL ;
    PORT
      LAYER M5 ;
        RECT  24.528 0 24.552 0.084 ;
    END
  END tw[315]
  PIN tw[316]
    DIRECTION INPUT ;
    USE SIGNAL ;
    PORT
      LAYER M5 ;
        RECT  24.624 0 24.648 0.084 ;
    END
  END tw[316]
  PIN tw[317]
    DIRECTION INPUT ;
    USE SIGNAL ;
    PORT
      LAYER M5 ;
        RECT  24.72 0 24.744 0.084 ;
    END
  END tw[317]
  PIN tw[318]
    DIRECTION INPUT ;
    USE SIGNAL ;
    PORT
      LAYER M5 ;
        RECT  24.816 0 24.84 0.084 ;
    END
  END tw[318]
  PIN tw[319]
    DIRECTION INPUT ;
    USE SIGNAL ;
    PORT
      LAYER M5 ;
        RECT  24.912 0 24.936 0.084 ;
    END
  END tw[319]
  PIN tw[31]
    DIRECTION INPUT ;
    USE SIGNAL ;
    PORT
      LAYER M5 ;
        RECT  41.04 0 41.064 0.084 ;
    END
  END tw[31]
  PIN tw[320]
    DIRECTION INPUT ;
    USE SIGNAL ;
    PORT
      LAYER M5 ;
        RECT  25.008 0 25.032 0.084 ;
    END
  END tw[320]
  PIN tw[321]
    DIRECTION INPUT ;
    USE SIGNAL ;
    PORT
      LAYER M5 ;
        RECT  25.104 0 25.128 0.084 ;
    END
  END tw[321]
  PIN tw[322]
    DIRECTION INPUT ;
    USE SIGNAL ;
    PORT
      LAYER M5 ;
        RECT  25.2 0 25.224 0.084 ;
    END
  END tw[322]
  PIN tw[323]
    DIRECTION INPUT ;
    USE SIGNAL ;
    PORT
      LAYER M5 ;
        RECT  25.296 0 25.32 0.084 ;
    END
  END tw[323]
  PIN tw[324]
    DIRECTION INPUT ;
    USE SIGNAL ;
    PORT
      LAYER M5 ;
        RECT  25.392 0 25.416 0.084 ;
    END
  END tw[324]
  PIN tw[325]
    DIRECTION INPUT ;
    USE SIGNAL ;
    PORT
      LAYER M5 ;
        RECT  25.488 0 25.512 0.084 ;
    END
  END tw[325]
  PIN tw[326]
    DIRECTION INPUT ;
    USE SIGNAL ;
    PORT
      LAYER M5 ;
        RECT  25.584 0 25.608 0.084 ;
    END
  END tw[326]
  PIN tw[327]
    DIRECTION INPUT ;
    USE SIGNAL ;
    PORT
      LAYER M5 ;
        RECT  25.68 0 25.704 0.084 ;
    END
  END tw[327]
  PIN tw[328]
    DIRECTION INPUT ;
    USE SIGNAL ;
    PORT
      LAYER M5 ;
        RECT  25.776 0 25.8 0.084 ;
    END
  END tw[328]
  PIN tw[329]
    DIRECTION INPUT ;
    USE SIGNAL ;
    PORT
      LAYER M5 ;
        RECT  25.872 0 25.896 0.084 ;
    END
  END tw[329]
  PIN tw[32]
    DIRECTION INPUT ;
    USE SIGNAL ;
    PORT
      LAYER M5 ;
        RECT  41.136 0 41.16 0.084 ;
    END
  END tw[32]
  PIN tw[330]
    DIRECTION INPUT ;
    USE SIGNAL ;
    PORT
      LAYER M5 ;
        RECT  25.968 0 25.992 0.084 ;
    END
  END tw[330]
  PIN tw[331]
    DIRECTION INPUT ;
    USE SIGNAL ;
    PORT
      LAYER M5 ;
        RECT  29.136 0 29.16 0.084 ;
    END
  END tw[331]
  PIN tw[332]
    DIRECTION INPUT ;
    USE SIGNAL ;
    PORT
      LAYER M5 ;
        RECT  29.232 0 29.256 0.084 ;
    END
  END tw[332]
  PIN tw[333]
    DIRECTION INPUT ;
    USE SIGNAL ;
    PORT
      LAYER M5 ;
        RECT  29.328 0 29.352 0.084 ;
    END
  END tw[333]
  PIN tw[334]
    DIRECTION INPUT ;
    USE SIGNAL ;
    PORT
      LAYER M5 ;
        RECT  29.424 0 29.448 0.084 ;
    END
  END tw[334]
  PIN tw[335]
    DIRECTION INPUT ;
    USE SIGNAL ;
    PORT
      LAYER M5 ;
        RECT  29.52 0 29.544 0.084 ;
    END
  END tw[335]
  PIN tw[336]
    DIRECTION INPUT ;
    USE SIGNAL ;
    PORT
      LAYER M5 ;
        RECT  29.616 0 29.64 0.084 ;
    END
  END tw[336]
  PIN tw[337]
    DIRECTION INPUT ;
    USE SIGNAL ;
    PORT
      LAYER M5 ;
        RECT  29.712 0 29.736 0.084 ;
    END
  END tw[337]
  PIN tw[338]
    DIRECTION INPUT ;
    USE SIGNAL ;
    PORT
      LAYER M5 ;
        RECT  29.808 0 29.832 0.084 ;
    END
  END tw[338]
  PIN tw[339]
    DIRECTION INPUT ;
    USE SIGNAL ;
    PORT
      LAYER M5 ;
        RECT  29.904 0 29.928 0.084 ;
    END
  END tw[339]
  PIN tw[33]
    DIRECTION INPUT ;
    USE SIGNAL ;
    PORT
      LAYER M5 ;
        RECT  41.232 0 41.256 0.084 ;
    END
  END tw[33]
  PIN tw[340]
    DIRECTION INPUT ;
    USE SIGNAL ;
    PORT
      LAYER M5 ;
        RECT  30 0 30.024 0.084 ;
    END
  END tw[340]
  PIN tw[341]
    DIRECTION INPUT ;
    USE SIGNAL ;
    PORT
      LAYER M5 ;
        RECT  30.096 0 30.12 0.084 ;
    END
  END tw[341]
  PIN tw[342]
    DIRECTION INPUT ;
    USE SIGNAL ;
    PORT
      LAYER M5 ;
        RECT  30.192 0 30.216 0.084 ;
    END
  END tw[342]
  PIN tw[343]
    DIRECTION INPUT ;
    USE SIGNAL ;
    PORT
      LAYER M5 ;
        RECT  30.288 0 30.312 0.084 ;
    END
  END tw[343]
  PIN tw[344]
    DIRECTION INPUT ;
    USE SIGNAL ;
    PORT
      LAYER M5 ;
        RECT  30.384 0 30.408 0.084 ;
    END
  END tw[344]
  PIN tw[345]
    DIRECTION INPUT ;
    USE SIGNAL ;
    PORT
      LAYER M5 ;
        RECT  30.48 0 30.504 0.084 ;
    END
  END tw[345]
  PIN tw[346]
    DIRECTION INPUT ;
    USE SIGNAL ;
    PORT
      LAYER M5 ;
        RECT  30.576 0 30.6 0.084 ;
    END
  END tw[346]
  PIN tw[347]
    DIRECTION INPUT ;
    USE SIGNAL ;
    PORT
      LAYER M5 ;
        RECT  30.672 0 30.696 0.084 ;
    END
  END tw[347]
  PIN tw[348]
    DIRECTION INPUT ;
    USE SIGNAL ;
    PORT
      LAYER M5 ;
        RECT  30.768 0 30.792 0.084 ;
    END
  END tw[348]
  PIN tw[349]
    DIRECTION INPUT ;
    USE SIGNAL ;
    PORT
      LAYER M5 ;
        RECT  30.864 0 30.888 0.084 ;
    END
  END tw[349]
  PIN tw[34]
    DIRECTION INPUT ;
    USE SIGNAL ;
    PORT
      LAYER M5 ;
        RECT  41.328 0 41.352 0.084 ;
    END
  END tw[34]
  PIN tw[350]
    DIRECTION INPUT ;
    USE SIGNAL ;
    PORT
      LAYER M5 ;
        RECT  30.96 0 30.984 0.084 ;
    END
  END tw[350]
  PIN tw[351]
    DIRECTION INPUT ;
    USE SIGNAL ;
    PORT
      LAYER M5 ;
        RECT  31.056 0 31.08 0.084 ;
    END
  END tw[351]
  PIN tw[352]
    DIRECTION INPUT ;
    USE SIGNAL ;
    PORT
      LAYER M5 ;
        RECT  31.152 0 31.176 0.084 ;
    END
  END tw[352]
  PIN tw[353]
    DIRECTION INPUT ;
    USE SIGNAL ;
    PORT
      LAYER M5 ;
        RECT  31.248 0 31.272 0.084 ;
    END
  END tw[353]
  PIN tw[354]
    DIRECTION INPUT ;
    USE SIGNAL ;
    PORT
      LAYER M5 ;
        RECT  31.344 0 31.368 0.084 ;
    END
  END tw[354]
  PIN tw[355]
    DIRECTION INPUT ;
    USE SIGNAL ;
    PORT
      LAYER M5 ;
        RECT  31.44 0 31.464 0.084 ;
    END
  END tw[355]
  PIN tw[356]
    DIRECTION INPUT ;
    USE SIGNAL ;
    PORT
      LAYER M5 ;
        RECT  31.536 0 31.56 0.084 ;
    END
  END tw[356]
  PIN tw[357]
    DIRECTION INPUT ;
    USE SIGNAL ;
    PORT
      LAYER M5 ;
        RECT  31.632 0 31.656 0.084 ;
    END
  END tw[357]
  PIN tw[358]
    DIRECTION INPUT ;
    USE SIGNAL ;
    PORT
      LAYER M5 ;
        RECT  31.728 0 31.752 0.084 ;
    END
  END tw[358]
  PIN tw[359]
    DIRECTION INPUT ;
    USE SIGNAL ;
    PORT
      LAYER M5 ;
        RECT  31.824 0 31.848 0.084 ;
    END
  END tw[359]
  PIN tw[35]
    DIRECTION INPUT ;
    USE SIGNAL ;
    PORT
      LAYER M5 ;
        RECT  41.424 0 41.448 0.084 ;
    END
  END tw[35]
  PIN tw[360]
    DIRECTION INPUT ;
    USE SIGNAL ;
    PORT
      LAYER M5 ;
        RECT  31.92 0 31.944 0.084 ;
    END
  END tw[360]
  PIN tw[361]
    DIRECTION INPUT ;
    USE SIGNAL ;
    PORT
      LAYER M5 ;
        RECT  32.016 0 32.04 0.084 ;
    END
  END tw[361]
  PIN tw[362]
    DIRECTION INPUT ;
    USE SIGNAL ;
    PORT
      LAYER M5 ;
        RECT  32.112 0 32.136 0.084 ;
    END
  END tw[362]
  PIN tw[363]
    DIRECTION INPUT ;
    USE SIGNAL ;
    PORT
      LAYER M5 ;
        RECT  64.464 0 64.488 0.084 ;
    END
  END tw[363]
  PIN tw[364]
    DIRECTION INPUT ;
    USE SIGNAL ;
    PORT
      LAYER M5 ;
        RECT  64.56 0 64.584 0.084 ;
    END
  END tw[364]
  PIN tw[365]
    DIRECTION INPUT ;
    USE SIGNAL ;
    PORT
      LAYER M5 ;
        RECT  64.656 0 64.68 0.084 ;
    END
  END tw[365]
  PIN tw[366]
    DIRECTION INPUT ;
    USE SIGNAL ;
    PORT
      LAYER M5 ;
        RECT  64.752 0 64.776 0.084 ;
    END
  END tw[366]
  PIN tw[367]
    DIRECTION INPUT ;
    USE SIGNAL ;
    PORT
      LAYER M5 ;
        RECT  64.848 0 64.872 0.084 ;
    END
  END tw[367]
  PIN tw[368]
    DIRECTION INPUT ;
    USE SIGNAL ;
    PORT
      LAYER M5 ;
        RECT  64.944 0 64.968 0.084 ;
    END
  END tw[368]
  PIN tw[369]
    DIRECTION INPUT ;
    USE SIGNAL ;
    PORT
      LAYER M5 ;
        RECT  65.04 0 65.064 0.084 ;
    END
  END tw[369]
  PIN tw[36]
    DIRECTION INPUT ;
    USE SIGNAL ;
    PORT
      LAYER M5 ;
        RECT  41.52 0 41.544 0.084 ;
    END
  END tw[36]
  PIN tw[370]
    DIRECTION INPUT ;
    USE SIGNAL ;
    PORT
      LAYER M5 ;
        RECT  65.136 0 65.16 0.084 ;
    END
  END tw[370]
  PIN tw[371]
    DIRECTION INPUT ;
    USE SIGNAL ;
    PORT
      LAYER M5 ;
        RECT  65.232 0 65.256 0.084 ;
    END
  END tw[371]
  PIN tw[372]
    DIRECTION INPUT ;
    USE SIGNAL ;
    PORT
      LAYER M5 ;
        RECT  65.328 0 65.352 0.084 ;
    END
  END tw[372]
  PIN tw[373]
    DIRECTION INPUT ;
    USE SIGNAL ;
    PORT
      LAYER M5 ;
        RECT  65.424 0 65.448 0.084 ;
    END
  END tw[373]
  PIN tw[374]
    DIRECTION INPUT ;
    USE SIGNAL ;
    PORT
      LAYER M5 ;
        RECT  65.52 0 65.544 0.084 ;
    END
  END tw[374]
  PIN tw[375]
    DIRECTION INPUT ;
    USE SIGNAL ;
    PORT
      LAYER M5 ;
        RECT  65.616 0 65.64 0.084 ;
    END
  END tw[375]
  PIN tw[376]
    DIRECTION INPUT ;
    USE SIGNAL ;
    PORT
      LAYER M5 ;
        RECT  65.712 0 65.736 0.084 ;
    END
  END tw[376]
  PIN tw[377]
    DIRECTION INPUT ;
    USE SIGNAL ;
    PORT
      LAYER M5 ;
        RECT  65.808 0 65.832 0.084 ;
    END
  END tw[377]
  PIN tw[378]
    DIRECTION INPUT ;
    USE SIGNAL ;
    PORT
      LAYER M5 ;
        RECT  65.904 0 65.928 0.084 ;
    END
  END tw[378]
  PIN tw[379]
    DIRECTION INPUT ;
    USE SIGNAL ;
    PORT
      LAYER M5 ;
        RECT  66 0 66.024 0.084 ;
    END
  END tw[379]
  PIN tw[37]
    DIRECTION INPUT ;
    USE SIGNAL ;
    PORT
      LAYER M5 ;
        RECT  41.616 0 41.64 0.084 ;
    END
  END tw[37]
  PIN tw[380]
    DIRECTION INPUT ;
    USE SIGNAL ;
    PORT
      LAYER M5 ;
        RECT  66.096 0 66.12 0.084 ;
    END
  END tw[380]
  PIN tw[381]
    DIRECTION INPUT ;
    USE SIGNAL ;
    PORT
      LAYER M5 ;
        RECT  66.192 0 66.216 0.084 ;
    END
  END tw[381]
  PIN tw[382]
    DIRECTION INPUT ;
    USE SIGNAL ;
    PORT
      LAYER M5 ;
        RECT  66.288 0 66.312 0.084 ;
    END
  END tw[382]
  PIN tw[383]
    DIRECTION INPUT ;
    USE SIGNAL ;
    PORT
      LAYER M5 ;
        RECT  66.384 0 66.408 0.084 ;
    END
  END tw[383]
  PIN tw[384]
    DIRECTION INPUT ;
    USE SIGNAL ;
    PORT
      LAYER M5 ;
        RECT  66.48 0 66.504 0.084 ;
    END
  END tw[384]
  PIN tw[385]
    DIRECTION INPUT ;
    USE SIGNAL ;
    PORT
      LAYER M5 ;
        RECT  66.576 0 66.6 0.084 ;
    END
  END tw[385]
  PIN tw[386]
    DIRECTION INPUT ;
    USE SIGNAL ;
    PORT
      LAYER M5 ;
        RECT  66.672 0 66.696 0.084 ;
    END
  END tw[386]
  PIN tw[387]
    DIRECTION INPUT ;
    USE SIGNAL ;
    PORT
      LAYER M5 ;
        RECT  66.768 0 66.792 0.084 ;
    END
  END tw[387]
  PIN tw[388]
    DIRECTION INPUT ;
    USE SIGNAL ;
    PORT
      LAYER M5 ;
        RECT  66.864 0 66.888 0.084 ;
    END
  END tw[388]
  PIN tw[389]
    DIRECTION INPUT ;
    USE SIGNAL ;
    PORT
      LAYER M5 ;
        RECT  66.96 0 66.984 0.084 ;
    END
  END tw[389]
  PIN tw[38]
    DIRECTION INPUT ;
    USE SIGNAL ;
    PORT
      LAYER M5 ;
        RECT  41.712 0 41.736 0.084 ;
    END
  END tw[38]
  PIN tw[390]
    DIRECTION INPUT ;
    USE SIGNAL ;
    PORT
      LAYER M5 ;
        RECT  67.056 0 67.08 0.084 ;
    END
  END tw[390]
  PIN tw[391]
    DIRECTION INPUT ;
    USE SIGNAL ;
    PORT
      LAYER M5 ;
        RECT  67.152 0 67.176 0.084 ;
    END
  END tw[391]
  PIN tw[392]
    DIRECTION INPUT ;
    USE SIGNAL ;
    PORT
      LAYER M5 ;
        RECT  67.248 0 67.272 0.084 ;
    END
  END tw[392]
  PIN tw[393]
    DIRECTION INPUT ;
    USE SIGNAL ;
    PORT
      LAYER M5 ;
        RECT  67.344 0 67.368 0.084 ;
    END
  END tw[393]
  PIN tw[394]
    DIRECTION INPUT ;
    USE SIGNAL ;
    PORT
      LAYER M5 ;
        RECT  67.44 0 67.464 0.084 ;
    END
  END tw[394]
  PIN tw[395]
    DIRECTION INPUT ;
    USE SIGNAL ;
    PORT
      LAYER M5 ;
        RECT  61.392 0 61.416 0.084 ;
    END
  END tw[395]
  PIN tw[396]
    DIRECTION INPUT ;
    USE SIGNAL ;
    PORT
      LAYER M5 ;
        RECT  61.488 0 61.512 0.084 ;
    END
  END tw[396]
  PIN tw[397]
    DIRECTION INPUT ;
    USE SIGNAL ;
    PORT
      LAYER M5 ;
        RECT  61.584 0 61.608 0.084 ;
    END
  END tw[397]
  PIN tw[398]
    DIRECTION INPUT ;
    USE SIGNAL ;
    PORT
      LAYER M5 ;
        RECT  61.68 0 61.704 0.084 ;
    END
  END tw[398]
  PIN tw[399]
    DIRECTION INPUT ;
    USE SIGNAL ;
    PORT
      LAYER M5 ;
        RECT  61.776 0 61.8 0.084 ;
    END
  END tw[399]
  PIN tw[39]
    DIRECTION INPUT ;
    USE SIGNAL ;
    PORT
      LAYER M5 ;
        RECT  41.808 0 41.832 0.084 ;
    END
  END tw[39]
  PIN tw[3]
    DIRECTION INPUT ;
    USE SIGNAL ;
    PORT
      LAYER M5 ;
        RECT  50.64 0 50.664 0.084 ;
    END
  END tw[3]
  PIN tw[400]
    DIRECTION INPUT ;
    USE SIGNAL ;
    PORT
      LAYER M5 ;
        RECT  61.872 0 61.896 0.084 ;
    END
  END tw[400]
  PIN tw[401]
    DIRECTION INPUT ;
    USE SIGNAL ;
    PORT
      LAYER M5 ;
        RECT  61.968 0 61.992 0.084 ;
    END
  END tw[401]
  PIN tw[402]
    DIRECTION INPUT ;
    USE SIGNAL ;
    PORT
      LAYER M5 ;
        RECT  62.064 0 62.088 0.084 ;
    END
  END tw[402]
  PIN tw[403]
    DIRECTION INPUT ;
    USE SIGNAL ;
    PORT
      LAYER M5 ;
        RECT  62.16 0 62.184 0.084 ;
    END
  END tw[403]
  PIN tw[404]
    DIRECTION INPUT ;
    USE SIGNAL ;
    PORT
      LAYER M5 ;
        RECT  62.256 0 62.28 0.084 ;
    END
  END tw[404]
  PIN tw[405]
    DIRECTION INPUT ;
    USE SIGNAL ;
    PORT
      LAYER M5 ;
        RECT  62.352 0 62.376 0.084 ;
    END
  END tw[405]
  PIN tw[406]
    DIRECTION INPUT ;
    USE SIGNAL ;
    PORT
      LAYER M5 ;
        RECT  62.448 0 62.472 0.084 ;
    END
  END tw[406]
  PIN tw[407]
    DIRECTION INPUT ;
    USE SIGNAL ;
    PORT
      LAYER M5 ;
        RECT  62.544 0 62.568 0.084 ;
    END
  END tw[407]
  PIN tw[408]
    DIRECTION INPUT ;
    USE SIGNAL ;
    PORT
      LAYER M5 ;
        RECT  62.64 0 62.664 0.084 ;
    END
  END tw[408]
  PIN tw[409]
    DIRECTION INPUT ;
    USE SIGNAL ;
    PORT
      LAYER M5 ;
        RECT  62.736 0 62.76 0.084 ;
    END
  END tw[409]
  PIN tw[40]
    DIRECTION INPUT ;
    USE SIGNAL ;
    PORT
      LAYER M5 ;
        RECT  41.904 0 41.928 0.084 ;
    END
  END tw[40]
  PIN tw[410]
    DIRECTION INPUT ;
    USE SIGNAL ;
    PORT
      LAYER M5 ;
        RECT  62.832 0 62.856 0.084 ;
    END
  END tw[410]
  PIN tw[411]
    DIRECTION INPUT ;
    USE SIGNAL ;
    PORT
      LAYER M5 ;
        RECT  62.928 0 62.952 0.084 ;
    END
  END tw[411]
  PIN tw[412]
    DIRECTION INPUT ;
    USE SIGNAL ;
    PORT
      LAYER M5 ;
        RECT  63.024 0 63.048 0.084 ;
    END
  END tw[412]
  PIN tw[413]
    DIRECTION INPUT ;
    USE SIGNAL ;
    PORT
      LAYER M5 ;
        RECT  63.12 0 63.144 0.084 ;
    END
  END tw[413]
  PIN tw[414]
    DIRECTION INPUT ;
    USE SIGNAL ;
    PORT
      LAYER M5 ;
        RECT  63.216 0 63.24 0.084 ;
    END
  END tw[414]
  PIN tw[415]
    DIRECTION INPUT ;
    USE SIGNAL ;
    PORT
      LAYER M5 ;
        RECT  63.312 0 63.336 0.084 ;
    END
  END tw[415]
  PIN tw[416]
    DIRECTION INPUT ;
    USE SIGNAL ;
    PORT
      LAYER M5 ;
        RECT  63.408 0 63.432 0.084 ;
    END
  END tw[416]
  PIN tw[417]
    DIRECTION INPUT ;
    USE SIGNAL ;
    PORT
      LAYER M5 ;
        RECT  63.504 0 63.528 0.084 ;
    END
  END tw[417]
  PIN tw[418]
    DIRECTION INPUT ;
    USE SIGNAL ;
    PORT
      LAYER M5 ;
        RECT  63.6 0 63.624 0.084 ;
    END
  END tw[418]
  PIN tw[419]
    DIRECTION INPUT ;
    USE SIGNAL ;
    PORT
      LAYER M5 ;
        RECT  63.696 0 63.72 0.084 ;
    END
  END tw[419]
  PIN tw[41]
    DIRECTION INPUT ;
    USE SIGNAL ;
    PORT
      LAYER M5 ;
        RECT  42 0 42.024 0.084 ;
    END
  END tw[41]
  PIN tw[420]
    DIRECTION INPUT ;
    USE SIGNAL ;
    PORT
      LAYER M5 ;
        RECT  63.792 0 63.816 0.084 ;
    END
  END tw[420]
  PIN tw[421]
    DIRECTION INPUT ;
    USE SIGNAL ;
    PORT
      LAYER M5 ;
        RECT  63.888 0 63.912 0.084 ;
    END
  END tw[421]
  PIN tw[422]
    DIRECTION INPUT ;
    USE SIGNAL ;
    PORT
      LAYER M5 ;
        RECT  63.984 0 64.008 0.084 ;
    END
  END tw[422]
  PIN tw[423]
    DIRECTION INPUT ;
    USE SIGNAL ;
    PORT
      LAYER M5 ;
        RECT  64.08 0 64.104 0.084 ;
    END
  END tw[423]
  PIN tw[424]
    DIRECTION INPUT ;
    USE SIGNAL ;
    PORT
      LAYER M5 ;
        RECT  64.176 0 64.2 0.084 ;
    END
  END tw[424]
  PIN tw[425]
    DIRECTION INPUT ;
    USE SIGNAL ;
    PORT
      LAYER M5 ;
        RECT  64.272 0 64.296 0.084 ;
    END
  END tw[425]
  PIN tw[426]
    DIRECTION INPUT ;
    USE SIGNAL ;
    PORT
      LAYER M5 ;
        RECT  64.368 0 64.392 0.084 ;
    END
  END tw[426]
  PIN tw[427]
    DIRECTION INPUT ;
    USE SIGNAL ;
    PORT
      LAYER M5 ;
        RECT  58.32 0 58.344 0.084 ;
    END
  END tw[427]
  PIN tw[428]
    DIRECTION INPUT ;
    USE SIGNAL ;
    PORT
      LAYER M5 ;
        RECT  58.416 0 58.44 0.084 ;
    END
  END tw[428]
  PIN tw[429]
    DIRECTION INPUT ;
    USE SIGNAL ;
    PORT
      LAYER M5 ;
        RECT  58.512 0 58.536 0.084 ;
    END
  END tw[429]
  PIN tw[42]
    DIRECTION INPUT ;
    USE SIGNAL ;
    PORT
      LAYER M5 ;
        RECT  42.096 0 42.12 0.084 ;
    END
  END tw[42]
  PIN tw[430]
    DIRECTION INPUT ;
    USE SIGNAL ;
    PORT
      LAYER M5 ;
        RECT  58.608 0 58.632 0.084 ;
    END
  END tw[430]
  PIN tw[431]
    DIRECTION INPUT ;
    USE SIGNAL ;
    PORT
      LAYER M5 ;
        RECT  58.704 0 58.728 0.084 ;
    END
  END tw[431]
  PIN tw[432]
    DIRECTION INPUT ;
    USE SIGNAL ;
    PORT
      LAYER M5 ;
        RECT  58.8 0 58.824 0.084 ;
    END
  END tw[432]
  PIN tw[433]
    DIRECTION INPUT ;
    USE SIGNAL ;
    PORT
      LAYER M5 ;
        RECT  58.896 0 58.92 0.084 ;
    END
  END tw[433]
  PIN tw[434]
    DIRECTION INPUT ;
    USE SIGNAL ;
    PORT
      LAYER M5 ;
        RECT  58.992 0 59.016 0.084 ;
    END
  END tw[434]
  PIN tw[435]
    DIRECTION INPUT ;
    USE SIGNAL ;
    PORT
      LAYER M5 ;
        RECT  59.088 0 59.112 0.084 ;
    END
  END tw[435]
  PIN tw[436]
    DIRECTION INPUT ;
    USE SIGNAL ;
    PORT
      LAYER M5 ;
        RECT  59.184 0 59.208 0.084 ;
    END
  END tw[436]
  PIN tw[437]
    DIRECTION INPUT ;
    USE SIGNAL ;
    PORT
      LAYER M5 ;
        RECT  59.28 0 59.304 0.084 ;
    END
  END tw[437]
  PIN tw[438]
    DIRECTION INPUT ;
    USE SIGNAL ;
    PORT
      LAYER M5 ;
        RECT  59.376 0 59.4 0.084 ;
    END
  END tw[438]
  PIN tw[439]
    DIRECTION INPUT ;
    USE SIGNAL ;
    PORT
      LAYER M5 ;
        RECT  59.472 0 59.496 0.084 ;
    END
  END tw[439]
  PIN tw[43]
    DIRECTION INPUT ;
    USE SIGNAL ;
    PORT
      LAYER M5 ;
        RECT  42.192 0 42.216 0.084 ;
    END
  END tw[43]
  PIN tw[440]
    DIRECTION INPUT ;
    USE SIGNAL ;
    PORT
      LAYER M5 ;
        RECT  59.568 0 59.592 0.084 ;
    END
  END tw[440]
  PIN tw[441]
    DIRECTION INPUT ;
    USE SIGNAL ;
    PORT
      LAYER M5 ;
        RECT  59.664 0 59.688 0.084 ;
    END
  END tw[441]
  PIN tw[442]
    DIRECTION INPUT ;
    USE SIGNAL ;
    PORT
      LAYER M5 ;
        RECT  59.76 0 59.784 0.084 ;
    END
  END tw[442]
  PIN tw[443]
    DIRECTION INPUT ;
    USE SIGNAL ;
    PORT
      LAYER M5 ;
        RECT  59.856 0 59.88 0.084 ;
    END
  END tw[443]
  PIN tw[444]
    DIRECTION INPUT ;
    USE SIGNAL ;
    PORT
      LAYER M5 ;
        RECT  59.952 0 59.976 0.084 ;
    END
  END tw[444]
  PIN tw[445]
    DIRECTION INPUT ;
    USE SIGNAL ;
    PORT
      LAYER M5 ;
        RECT  60.048 0 60.072 0.084 ;
    END
  END tw[445]
  PIN tw[446]
    DIRECTION INPUT ;
    USE SIGNAL ;
    PORT
      LAYER M5 ;
        RECT  60.144 0 60.168 0.084 ;
    END
  END tw[446]
  PIN tw[447]
    DIRECTION INPUT ;
    USE SIGNAL ;
    PORT
      LAYER M5 ;
        RECT  60.24 0 60.264 0.084 ;
    END
  END tw[447]
  PIN tw[448]
    DIRECTION INPUT ;
    USE SIGNAL ;
    PORT
      LAYER M5 ;
        RECT  60.336 0 60.36 0.084 ;
    END
  END tw[448]
  PIN tw[449]
    DIRECTION INPUT ;
    USE SIGNAL ;
    PORT
      LAYER M5 ;
        RECT  60.432 0 60.456 0.084 ;
    END
  END tw[449]
  PIN tw[44]
    DIRECTION INPUT ;
    USE SIGNAL ;
    PORT
      LAYER M5 ;
        RECT  42.288 0 42.312 0.084 ;
    END
  END tw[44]
  PIN tw[450]
    DIRECTION INPUT ;
    USE SIGNAL ;
    PORT
      LAYER M5 ;
        RECT  60.528 0 60.552 0.084 ;
    END
  END tw[450]
  PIN tw[451]
    DIRECTION INPUT ;
    USE SIGNAL ;
    PORT
      LAYER M5 ;
        RECT  60.624 0 60.648 0.084 ;
    END
  END tw[451]
  PIN tw[452]
    DIRECTION INPUT ;
    USE SIGNAL ;
    PORT
      LAYER M5 ;
        RECT  60.72 0 60.744 0.084 ;
    END
  END tw[452]
  PIN tw[453]
    DIRECTION INPUT ;
    USE SIGNAL ;
    PORT
      LAYER M5 ;
        RECT  60.816 0 60.84 0.084 ;
    END
  END tw[453]
  PIN tw[454]
    DIRECTION INPUT ;
    USE SIGNAL ;
    PORT
      LAYER M5 ;
        RECT  60.912 0 60.936 0.084 ;
    END
  END tw[454]
  PIN tw[455]
    DIRECTION INPUT ;
    USE SIGNAL ;
    PORT
      LAYER M5 ;
        RECT  61.008 0 61.032 0.084 ;
    END
  END tw[455]
  PIN tw[456]
    DIRECTION INPUT ;
    USE SIGNAL ;
    PORT
      LAYER M5 ;
        RECT  61.104 0 61.128 0.084 ;
    END
  END tw[456]
  PIN tw[457]
    DIRECTION INPUT ;
    USE SIGNAL ;
    PORT
      LAYER M5 ;
        RECT  61.2 0 61.224 0.084 ;
    END
  END tw[457]
  PIN tw[458]
    DIRECTION INPUT ;
    USE SIGNAL ;
    PORT
      LAYER M5 ;
        RECT  61.296 0 61.32 0.084 ;
    END
  END tw[458]
  PIN tw[459]
    DIRECTION INPUT ;
    USE SIGNAL ;
    PORT
      LAYER M5 ;
        RECT  70.608 0 70.632 0.084 ;
    END
  END tw[459]
  PIN tw[45]
    DIRECTION INPUT ;
    USE SIGNAL ;
    PORT
      LAYER M5 ;
        RECT  42.384 0 42.408 0.084 ;
    END
  END tw[45]
  PIN tw[460]
    DIRECTION INPUT ;
    USE SIGNAL ;
    PORT
      LAYER M5 ;
        RECT  70.704 0 70.728 0.084 ;
    END
  END tw[460]
  PIN tw[461]
    DIRECTION INPUT ;
    USE SIGNAL ;
    PORT
      LAYER M5 ;
        RECT  70.8 0 70.824 0.084 ;
    END
  END tw[461]
  PIN tw[462]
    DIRECTION INPUT ;
    USE SIGNAL ;
    PORT
      LAYER M5 ;
        RECT  70.896 0 70.92 0.084 ;
    END
  END tw[462]
  PIN tw[463]
    DIRECTION INPUT ;
    USE SIGNAL ;
    PORT
      LAYER M5 ;
        RECT  70.992 0 71.016 0.084 ;
    END
  END tw[463]
  PIN tw[464]
    DIRECTION INPUT ;
    USE SIGNAL ;
    PORT
      LAYER M5 ;
        RECT  71.088 0 71.112 0.084 ;
    END
  END tw[464]
  PIN tw[465]
    DIRECTION INPUT ;
    USE SIGNAL ;
    PORT
      LAYER M5 ;
        RECT  71.184 0 71.208 0.084 ;
    END
  END tw[465]
  PIN tw[466]
    DIRECTION INPUT ;
    USE SIGNAL ;
    PORT
      LAYER M5 ;
        RECT  71.28 0 71.304 0.084 ;
    END
  END tw[466]
  PIN tw[467]
    DIRECTION INPUT ;
    USE SIGNAL ;
    PORT
      LAYER M5 ;
        RECT  71.376 0 71.4 0.084 ;
    END
  END tw[467]
  PIN tw[468]
    DIRECTION INPUT ;
    USE SIGNAL ;
    PORT
      LAYER M5 ;
        RECT  71.472 0 71.496 0.084 ;
    END
  END tw[468]
  PIN tw[469]
    DIRECTION INPUT ;
    USE SIGNAL ;
    PORT
      LAYER M5 ;
        RECT  71.568 0 71.592 0.084 ;
    END
  END tw[469]
  PIN tw[46]
    DIRECTION INPUT ;
    USE SIGNAL ;
    PORT
      LAYER M5 ;
        RECT  42.48 0 42.504 0.084 ;
    END
  END tw[46]
  PIN tw[470]
    DIRECTION INPUT ;
    USE SIGNAL ;
    PORT
      LAYER M5 ;
        RECT  71.664 0 71.688 0.084 ;
    END
  END tw[470]
  PIN tw[471]
    DIRECTION INPUT ;
    USE SIGNAL ;
    PORT
      LAYER M5 ;
        RECT  71.76 0 71.784 0.084 ;
    END
  END tw[471]
  PIN tw[472]
    DIRECTION INPUT ;
    USE SIGNAL ;
    PORT
      LAYER M5 ;
        RECT  71.856 0 71.88 0.084 ;
    END
  END tw[472]
  PIN tw[473]
    DIRECTION INPUT ;
    USE SIGNAL ;
    PORT
      LAYER M5 ;
        RECT  71.952 0 71.976 0.084 ;
    END
  END tw[473]
  PIN tw[474]
    DIRECTION INPUT ;
    USE SIGNAL ;
    PORT
      LAYER M5 ;
        RECT  72.048 0 72.072 0.084 ;
    END
  END tw[474]
  PIN tw[475]
    DIRECTION INPUT ;
    USE SIGNAL ;
    PORT
      LAYER M5 ;
        RECT  72.144 0 72.168 0.084 ;
    END
  END tw[475]
  PIN tw[476]
    DIRECTION INPUT ;
    USE SIGNAL ;
    PORT
      LAYER M5 ;
        RECT  72.24 0 72.264 0.084 ;
    END
  END tw[476]
  PIN tw[477]
    DIRECTION INPUT ;
    USE SIGNAL ;
    PORT
      LAYER M5 ;
        RECT  72.336 0 72.36 0.084 ;
    END
  END tw[477]
  PIN tw[478]
    DIRECTION INPUT ;
    USE SIGNAL ;
    PORT
      LAYER M5 ;
        RECT  72.432 0 72.456 0.084 ;
    END
  END tw[478]
  PIN tw[479]
    DIRECTION INPUT ;
    USE SIGNAL ;
    PORT
      LAYER M5 ;
        RECT  72.528 0 72.552 0.084 ;
    END
  END tw[479]
  PIN tw[47]
    DIRECTION INPUT ;
    USE SIGNAL ;
    PORT
      LAYER M5 ;
        RECT  42.576 0 42.6 0.084 ;
    END
  END tw[47]
  PIN tw[480]
    DIRECTION INPUT ;
    USE SIGNAL ;
    PORT
      LAYER M5 ;
        RECT  72.624 0 72.648 0.084 ;
    END
  END tw[480]
  PIN tw[481]
    DIRECTION INPUT ;
    USE SIGNAL ;
    PORT
      LAYER M5 ;
        RECT  72.72 0 72.744 0.084 ;
    END
  END tw[481]
  PIN tw[482]
    DIRECTION INPUT ;
    USE SIGNAL ;
    PORT
      LAYER M5 ;
        RECT  72.816 0 72.84 0.084 ;
    END
  END tw[482]
  PIN tw[483]
    DIRECTION INPUT ;
    USE SIGNAL ;
    PORT
      LAYER M5 ;
        RECT  72.912 0 72.936 0.084 ;
    END
  END tw[483]
  PIN tw[484]
    DIRECTION INPUT ;
    USE SIGNAL ;
    PORT
      LAYER M5 ;
        RECT  73.008 0 73.032 0.084 ;
    END
  END tw[484]
  PIN tw[485]
    DIRECTION INPUT ;
    USE SIGNAL ;
    PORT
      LAYER M5 ;
        RECT  73.104 0 73.128 0.084 ;
    END
  END tw[485]
  PIN tw[486]
    DIRECTION INPUT ;
    USE SIGNAL ;
    PORT
      LAYER M5 ;
        RECT  73.2 0 73.224 0.084 ;
    END
  END tw[486]
  PIN tw[487]
    DIRECTION INPUT ;
    USE SIGNAL ;
    PORT
      LAYER M5 ;
        RECT  73.296 0 73.32 0.084 ;
    END
  END tw[487]
  PIN tw[488]
    DIRECTION INPUT ;
    USE SIGNAL ;
    PORT
      LAYER M5 ;
        RECT  73.392 0 73.416 0.084 ;
    END
  END tw[488]
  PIN tw[489]
    DIRECTION INPUT ;
    USE SIGNAL ;
    PORT
      LAYER M5 ;
        RECT  73.488 0 73.512 0.084 ;
    END
  END tw[489]
  PIN tw[48]
    DIRECTION INPUT ;
    USE SIGNAL ;
    PORT
      LAYER M5 ;
        RECT  42.672 0 42.696 0.084 ;
    END
  END tw[48]
  PIN tw[490]
    DIRECTION INPUT ;
    USE SIGNAL ;
    PORT
      LAYER M5 ;
        RECT  73.584 0 73.608 0.084 ;
    END
  END tw[490]
  PIN tw[491]
    DIRECTION INPUT ;
    USE SIGNAL ;
    PORT
      LAYER M5 ;
        RECT  67.536 0 67.56 0.084 ;
    END
  END tw[491]
  PIN tw[492]
    DIRECTION INPUT ;
    USE SIGNAL ;
    PORT
      LAYER M5 ;
        RECT  67.632 0 67.656 0.084 ;
    END
  END tw[492]
  PIN tw[493]
    DIRECTION INPUT ;
    USE SIGNAL ;
    PORT
      LAYER M5 ;
        RECT  67.728 0 67.752 0.084 ;
    END
  END tw[493]
  PIN tw[494]
    DIRECTION INPUT ;
    USE SIGNAL ;
    PORT
      LAYER M5 ;
        RECT  67.824 0 67.848 0.084 ;
    END
  END tw[494]
  PIN tw[495]
    DIRECTION INPUT ;
    USE SIGNAL ;
    PORT
      LAYER M5 ;
        RECT  67.92 0 67.944 0.084 ;
    END
  END tw[495]
  PIN tw[496]
    DIRECTION INPUT ;
    USE SIGNAL ;
    PORT
      LAYER M5 ;
        RECT  68.016 0 68.04 0.084 ;
    END
  END tw[496]
  PIN tw[497]
    DIRECTION INPUT ;
    USE SIGNAL ;
    PORT
      LAYER M5 ;
        RECT  68.112 0 68.136 0.084 ;
    END
  END tw[497]
  PIN tw[498]
    DIRECTION INPUT ;
    USE SIGNAL ;
    PORT
      LAYER M5 ;
        RECT  68.208 0 68.232 0.084 ;
    END
  END tw[498]
  PIN tw[499]
    DIRECTION INPUT ;
    USE SIGNAL ;
    PORT
      LAYER M5 ;
        RECT  68.304 0 68.328 0.084 ;
    END
  END tw[499]
  PIN tw[49]
    DIRECTION INPUT ;
    USE SIGNAL ;
    PORT
      LAYER M5 ;
        RECT  42.768 0 42.792 0.084 ;
    END
  END tw[49]
  PIN tw[4]
    DIRECTION INPUT ;
    USE SIGNAL ;
    PORT
      LAYER M5 ;
        RECT  50.736 0 50.76 0.084 ;
    END
  END tw[4]
  PIN tw[500]
    DIRECTION INPUT ;
    USE SIGNAL ;
    PORT
      LAYER M5 ;
        RECT  68.4 0 68.424 0.084 ;
    END
  END tw[500]
  PIN tw[501]
    DIRECTION INPUT ;
    USE SIGNAL ;
    PORT
      LAYER M5 ;
        RECT  68.496 0 68.52 0.084 ;
    END
  END tw[501]
  PIN tw[502]
    DIRECTION INPUT ;
    USE SIGNAL ;
    PORT
      LAYER M5 ;
        RECT  68.592 0 68.616 0.084 ;
    END
  END tw[502]
  PIN tw[503]
    DIRECTION INPUT ;
    USE SIGNAL ;
    PORT
      LAYER M5 ;
        RECT  68.688 0 68.712 0.084 ;
    END
  END tw[503]
  PIN tw[504]
    DIRECTION INPUT ;
    USE SIGNAL ;
    PORT
      LAYER M5 ;
        RECT  68.784 0 68.808 0.084 ;
    END
  END tw[504]
  PIN tw[505]
    DIRECTION INPUT ;
    USE SIGNAL ;
    PORT
      LAYER M5 ;
        RECT  68.88 0 68.904 0.084 ;
    END
  END tw[505]
  PIN tw[506]
    DIRECTION INPUT ;
    USE SIGNAL ;
    PORT
      LAYER M5 ;
        RECT  68.976 0 69 0.084 ;
    END
  END tw[506]
  PIN tw[507]
    DIRECTION INPUT ;
    USE SIGNAL ;
    PORT
      LAYER M5 ;
        RECT  69.072 0 69.096 0.084 ;
    END
  END tw[507]
  PIN tw[508]
    DIRECTION INPUT ;
    USE SIGNAL ;
    PORT
      LAYER M5 ;
        RECT  69.168 0 69.192 0.084 ;
    END
  END tw[508]
  PIN tw[509]
    DIRECTION INPUT ;
    USE SIGNAL ;
    PORT
      LAYER M5 ;
        RECT  69.264 0 69.288 0.084 ;
    END
  END tw[509]
  PIN tw[50]
    DIRECTION INPUT ;
    USE SIGNAL ;
    PORT
      LAYER M5 ;
        RECT  42.864 0 42.888 0.084 ;
    END
  END tw[50]
  PIN tw[510]
    DIRECTION INPUT ;
    USE SIGNAL ;
    PORT
      LAYER M5 ;
        RECT  69.36 0 69.384 0.084 ;
    END
  END tw[510]
  PIN tw[511]
    DIRECTION INPUT ;
    USE SIGNAL ;
    PORT
      LAYER M5 ;
        RECT  69.456 0 69.48 0.084 ;
    END
  END tw[511]
  PIN tw[512]
    DIRECTION INPUT ;
    USE SIGNAL ;
    PORT
      LAYER M5 ;
        RECT  69.552 0 69.576 0.084 ;
    END
  END tw[512]
  PIN tw[513]
    DIRECTION INPUT ;
    USE SIGNAL ;
    PORT
      LAYER M5 ;
        RECT  69.648 0 69.672 0.084 ;
    END
  END tw[513]
  PIN tw[514]
    DIRECTION INPUT ;
    USE SIGNAL ;
    PORT
      LAYER M5 ;
        RECT  69.744 0 69.768 0.084 ;
    END
  END tw[514]
  PIN tw[515]
    DIRECTION INPUT ;
    USE SIGNAL ;
    PORT
      LAYER M5 ;
        RECT  69.84 0 69.864 0.084 ;
    END
  END tw[515]
  PIN tw[516]
    DIRECTION INPUT ;
    USE SIGNAL ;
    PORT
      LAYER M5 ;
        RECT  69.936 0 69.96 0.084 ;
    END
  END tw[516]
  PIN tw[517]
    DIRECTION INPUT ;
    USE SIGNAL ;
    PORT
      LAYER M5 ;
        RECT  70.032 0 70.056 0.084 ;
    END
  END tw[517]
  PIN tw[518]
    DIRECTION INPUT ;
    USE SIGNAL ;
    PORT
      LAYER M5 ;
        RECT  70.128 0 70.152 0.084 ;
    END
  END tw[518]
  PIN tw[519]
    DIRECTION INPUT ;
    USE SIGNAL ;
    PORT
      LAYER M5 ;
        RECT  70.224 0 70.248 0.084 ;
    END
  END tw[519]
  PIN tw[51]
    DIRECTION INPUT ;
    USE SIGNAL ;
    PORT
      LAYER M5 ;
        RECT  42.96 0 42.984 0.084 ;
    END
  END tw[51]
  PIN tw[520]
    DIRECTION INPUT ;
    USE SIGNAL ;
    PORT
      LAYER M5 ;
        RECT  70.32 0 70.344 0.084 ;
    END
  END tw[520]
  PIN tw[521]
    DIRECTION INPUT ;
    USE SIGNAL ;
    PORT
      LAYER M5 ;
        RECT  70.416 0 70.44 0.084 ;
    END
  END tw[521]
  PIN tw[522]
    DIRECTION INPUT ;
    USE SIGNAL ;
    PORT
      LAYER M5 ;
        RECT  70.512 0 70.536 0.084 ;
    END
  END tw[522]
  PIN tw[523]
    DIRECTION INPUT ;
    USE SIGNAL ;
    PORT
      LAYER M5 ;
        RECT  57.552 0 57.576 0.084 ;
    END
  END tw[523]
  PIN tw[524]
    DIRECTION INPUT ;
    USE SIGNAL ;
    PORT
      LAYER M5 ;
        RECT  57.648 0 57.672 0.084 ;
    END
  END tw[524]
  PIN tw[525]
    DIRECTION INPUT ;
    USE SIGNAL ;
    PORT
      LAYER M5 ;
        RECT  57.744 0 57.768 0.084 ;
    END
  END tw[525]
  PIN tw[526]
    DIRECTION INPUT ;
    USE SIGNAL ;
    PORT
      LAYER M5 ;
        RECT  57.84 0 57.864 0.084 ;
    END
  END tw[526]
  PIN tw[527]
    DIRECTION INPUT ;
    USE SIGNAL ;
    PORT
      LAYER M5 ;
        RECT  57.936 0 57.96 0.084 ;
    END
  END tw[527]
  PIN tw[52]
    DIRECTION INPUT ;
    USE SIGNAL ;
    PORT
      LAYER M5 ;
        RECT  43.056 0 43.08 0.084 ;
    END
  END tw[52]
  PIN tw[53]
    DIRECTION INPUT ;
    USE SIGNAL ;
    PORT
      LAYER M5 ;
        RECT  43.152 0 43.176 0.084 ;
    END
  END tw[53]
  PIN tw[54]
    DIRECTION INPUT ;
    USE SIGNAL ;
    PORT
      LAYER M5 ;
        RECT  43.248 0 43.272 0.084 ;
    END
  END tw[54]
  PIN tw[55]
    DIRECTION INPUT ;
    USE SIGNAL ;
    PORT
      LAYER M5 ;
        RECT  43.344 0 43.368 0.084 ;
    END
  END tw[55]
  PIN tw[56]
    DIRECTION INPUT ;
    USE SIGNAL ;
    PORT
      LAYER M5 ;
        RECT  43.44 0 43.464 0.084 ;
    END
  END tw[56]
  PIN tw[57]
    DIRECTION INPUT ;
    USE SIGNAL ;
    PORT
      LAYER M5 ;
        RECT  43.536 0 43.56 0.084 ;
    END
  END tw[57]
  PIN tw[58]
    DIRECTION INPUT ;
    USE SIGNAL ;
    PORT
      LAYER M5 ;
        RECT  43.632 0 43.656 0.084 ;
    END
  END tw[58]
  PIN tw[59]
    DIRECTION INPUT ;
    USE SIGNAL ;
    PORT
      LAYER M5 ;
        RECT  43.728 0 43.752 0.084 ;
    END
  END tw[59]
  PIN tw[5]
    DIRECTION INPUT ;
    USE SIGNAL ;
    PORT
      LAYER M5 ;
        RECT  50.832 0 50.856 0.084 ;
    END
  END tw[5]
  PIN tw[60]
    DIRECTION INPUT ;
    USE SIGNAL ;
    PORT
      LAYER M5 ;
        RECT  43.824 0 43.848 0.084 ;
    END
  END tw[60]
  PIN tw[61]
    DIRECTION INPUT ;
    USE SIGNAL ;
    PORT
      LAYER M5 ;
        RECT  43.92 0 43.944 0.084 ;
    END
  END tw[61]
  PIN tw[62]
    DIRECTION INPUT ;
    USE SIGNAL ;
    PORT
      LAYER M5 ;
        RECT  44.016 0 44.04 0.084 ;
    END
  END tw[62]
  PIN tw[63]
    DIRECTION INPUT ;
    USE SIGNAL ;
    PORT
      LAYER M5 ;
        RECT  44.112 0 44.136 0.084 ;
    END
  END tw[63]
  PIN tw[64]
    DIRECTION INPUT ;
    USE SIGNAL ;
    PORT
      LAYER M5 ;
        RECT  44.208 0 44.232 0.084 ;
    END
  END tw[64]
  PIN tw[65]
    DIRECTION INPUT ;
    USE SIGNAL ;
    PORT
      LAYER M5 ;
        RECT  44.304 0 44.328 0.084 ;
    END
  END tw[65]
  PIN tw[66]
    DIRECTION INPUT ;
    USE SIGNAL ;
    PORT
      LAYER M5 ;
        RECT  44.4 0 44.424 0.084 ;
    END
  END tw[66]
  PIN tw[67]
    DIRECTION INPUT ;
    USE SIGNAL ;
    PORT
      LAYER M5 ;
        RECT  44.496 0 44.52 0.084 ;
    END
  END tw[67]
  PIN tw[68]
    DIRECTION INPUT ;
    USE SIGNAL ;
    PORT
      LAYER M5 ;
        RECT  44.592 0 44.616 0.084 ;
    END
  END tw[68]
  PIN tw[69]
    DIRECTION INPUT ;
    USE SIGNAL ;
    PORT
      LAYER M5 ;
        RECT  44.688 0 44.712 0.084 ;
    END
  END tw[69]
  PIN tw[6]
    DIRECTION INPUT ;
    USE SIGNAL ;
    PORT
      LAYER M5 ;
        RECT  50.928 0 50.952 0.084 ;
    END
  END tw[6]
  PIN tw[70]
    DIRECTION INPUT ;
    USE SIGNAL ;
    PORT
      LAYER M5 ;
        RECT  44.784 0 44.808 0.084 ;
    END
  END tw[70]
  PIN tw[71]
    DIRECTION INPUT ;
    USE SIGNAL ;
    PORT
      LAYER M5 ;
        RECT  44.88 0 44.904 0.084 ;
    END
  END tw[71]
  PIN tw[72]
    DIRECTION INPUT ;
    USE SIGNAL ;
    PORT
      LAYER M5 ;
        RECT  44.976 0 45 0.084 ;
    END
  END tw[72]
  PIN tw[73]
    DIRECTION INPUT ;
    USE SIGNAL ;
    PORT
      LAYER M5 ;
        RECT  45.072 0 45.096 0.084 ;
    END
  END tw[73]
  PIN tw[74]
    DIRECTION INPUT ;
    USE SIGNAL ;
    PORT
      LAYER M5 ;
        RECT  45.168 0 45.192 0.084 ;
    END
  END tw[74]
  PIN tw[75]
    DIRECTION INPUT ;
    USE SIGNAL ;
    PORT
      LAYER M5 ;
        RECT  45.264 0 45.288 0.084 ;
    END
  END tw[75]
  PIN tw[76]
    DIRECTION INPUT ;
    USE SIGNAL ;
    PORT
      LAYER M5 ;
        RECT  45.36 0 45.384 0.084 ;
    END
  END tw[76]
  PIN tw[77]
    DIRECTION INPUT ;
    USE SIGNAL ;
    PORT
      LAYER M5 ;
        RECT  45.456 0 45.48 0.084 ;
    END
  END tw[77]
  PIN tw[78]
    DIRECTION INPUT ;
    USE SIGNAL ;
    PORT
      LAYER M5 ;
        RECT  45.552 0 45.576 0.084 ;
    END
  END tw[78]
  PIN tw[79]
    DIRECTION INPUT ;
    USE SIGNAL ;
    PORT
      LAYER M5 ;
        RECT  45.648 0 45.672 0.084 ;
    END
  END tw[79]
  PIN tw[7]
    DIRECTION INPUT ;
    USE SIGNAL ;
    PORT
      LAYER M5 ;
        RECT  51.024 0 51.048 0.084 ;
    END
  END tw[7]
  PIN tw[80]
    DIRECTION INPUT ;
    USE SIGNAL ;
    PORT
      LAYER M5 ;
        RECT  45.744 0 45.768 0.084 ;
    END
  END tw[80]
  PIN tw[81]
    DIRECTION INPUT ;
    USE SIGNAL ;
    PORT
      LAYER M5 ;
        RECT  45.84 0 45.864 0.084 ;
    END
  END tw[81]
  PIN tw[82]
    DIRECTION INPUT ;
    USE SIGNAL ;
    PORT
      LAYER M5 ;
        RECT  45.936 0 45.96 0.084 ;
    END
  END tw[82]
  PIN tw[83]
    DIRECTION INPUT ;
    USE SIGNAL ;
    PORT
      LAYER M5 ;
        RECT  46.032 0 46.056 0.084 ;
    END
  END tw[83]
  PIN tw[84]
    DIRECTION INPUT ;
    USE SIGNAL ;
    PORT
      LAYER M5 ;
        RECT  46.128 0 46.152 0.084 ;
    END
  END tw[84]
  PIN tw[85]
    DIRECTION INPUT ;
    USE SIGNAL ;
    PORT
      LAYER M5 ;
        RECT  46.224 0 46.248 0.084 ;
    END
  END tw[85]
  PIN tw[86]
    DIRECTION INPUT ;
    USE SIGNAL ;
    PORT
      LAYER M5 ;
        RECT  46.32 0 46.344 0.084 ;
    END
  END tw[86]
  PIN tw[87]
    DIRECTION INPUT ;
    USE SIGNAL ;
    PORT
      LAYER M5 ;
        RECT  46.416 0 46.44 0.084 ;
    END
  END tw[87]
  PIN tw[88]
    DIRECTION INPUT ;
    USE SIGNAL ;
    PORT
      LAYER M5 ;
        RECT  46.512 0 46.536 0.084 ;
    END
  END tw[88]
  PIN tw[89]
    DIRECTION INPUT ;
    USE SIGNAL ;
    PORT
      LAYER M5 ;
        RECT  46.608 0 46.632 0.084 ;
    END
  END tw[89]
  PIN tw[8]
    DIRECTION INPUT ;
    USE SIGNAL ;
    PORT
      LAYER M5 ;
        RECT  51.12 0 51.144 0.084 ;
    END
  END tw[8]
  PIN tw[90]
    DIRECTION INPUT ;
    USE SIGNAL ;
    PORT
      LAYER M5 ;
        RECT  46.704 0 46.728 0.084 ;
    END
  END tw[90]
  PIN tw[91]
    DIRECTION INPUT ;
    USE SIGNAL ;
    PORT
      LAYER M5 ;
        RECT  46.8 0 46.824 0.084 ;
    END
  END tw[91]
  PIN tw[92]
    DIRECTION INPUT ;
    USE SIGNAL ;
    PORT
      LAYER M5 ;
        RECT  46.896 0 46.92 0.084 ;
    END
  END tw[92]
  PIN tw[93]
    DIRECTION INPUT ;
    USE SIGNAL ;
    PORT
      LAYER M5 ;
        RECT  46.992 0 47.016 0.084 ;
    END
  END tw[93]
  PIN tw[94]
    DIRECTION INPUT ;
    USE SIGNAL ;
    PORT
      LAYER M5 ;
        RECT  47.088 0 47.112 0.084 ;
    END
  END tw[94]
  PIN tw[95]
    DIRECTION INPUT ;
    USE SIGNAL ;
    PORT
      LAYER M5 ;
        RECT  47.184 0 47.208 0.084 ;
    END
  END tw[95]
  PIN tw[96]
    DIRECTION INPUT ;
    USE SIGNAL ;
    PORT
      LAYER M5 ;
        RECT  47.28 0 47.304 0.084 ;
    END
  END tw[96]
  PIN tw[97]
    DIRECTION INPUT ;
    USE SIGNAL ;
    PORT
      LAYER M5 ;
        RECT  47.376 0 47.4 0.084 ;
    END
  END tw[97]
  PIN tw[98]
    DIRECTION INPUT ;
    USE SIGNAL ;
    PORT
      LAYER M5 ;
        RECT  47.472 0 47.496 0.084 ;
    END
  END tw[98]
  PIN tw[99]
    DIRECTION INPUT ;
    USE SIGNAL ;
    PORT
      LAYER M5 ;
        RECT  47.568 0 47.592 0.084 ;
    END
  END tw[99]
  PIN tw[9]
    DIRECTION INPUT ;
    USE SIGNAL ;
    PORT
      LAYER M5 ;
        RECT  51.216 0 51.24 0.084 ;
    END
  END tw[9]
  PIN tx_flit[0]
    DIRECTION OUTPUT ;
    USE SIGNAL ;
    PORT
      LAYER M5 ;
        RECT  28.848 21.516 28.872 21.6 ;
    END
  END tx_flit[0]
  PIN tx_flit[100]
    DIRECTION OUTPUT ;
    USE SIGNAL ;
    PORT
      LAYER M5 ;
        RECT  35.376 21.516 35.4 21.6 ;
    END
  END tx_flit[100]
  PIN tx_flit[101]
    DIRECTION OUTPUT ;
    USE SIGNAL ;
    PORT
      LAYER M5 ;
        RECT  35.472 21.516 35.496 21.6 ;
    END
  END tx_flit[101]
  PIN tx_flit[102]
    DIRECTION OUTPUT ;
    USE SIGNAL ;
    PORT
      LAYER M5 ;
        RECT  35.568 21.516 35.592 21.6 ;
    END
  END tx_flit[102]
  PIN tx_flit[103]
    DIRECTION OUTPUT ;
    USE SIGNAL ;
    PORT
      LAYER M5 ;
        RECT  35.664 21.516 35.688 21.6 ;
    END
  END tx_flit[103]
  PIN tx_flit[104]
    DIRECTION OUTPUT ;
    USE SIGNAL ;
    PORT
      LAYER M5 ;
        RECT  35.76 21.516 35.784 21.6 ;
    END
  END tx_flit[104]
  PIN tx_flit[105]
    DIRECTION OUTPUT ;
    USE SIGNAL ;
    PORT
      LAYER M5 ;
        RECT  35.856 21.516 35.88 21.6 ;
    END
  END tx_flit[105]
  PIN tx_flit[106]
    DIRECTION OUTPUT ;
    USE SIGNAL ;
    PORT
      LAYER M5 ;
        RECT  35.952 21.516 35.976 21.6 ;
    END
  END tx_flit[106]
  PIN tx_flit[107]
    DIRECTION OUTPUT ;
    USE SIGNAL ;
    PORT
      LAYER M5 ;
        RECT  36.048 21.516 36.072 21.6 ;
    END
  END tx_flit[107]
  PIN tx_flit[108]
    DIRECTION OUTPUT ;
    USE SIGNAL ;
    PORT
      LAYER M5 ;
        RECT  36.144 21.516 36.168 21.6 ;
    END
  END tx_flit[108]
  PIN tx_flit[109]
    DIRECTION OUTPUT ;
    USE SIGNAL ;
    PORT
      LAYER M5 ;
        RECT  36.24 21.516 36.264 21.6 ;
    END
  END tx_flit[109]
  PIN tx_flit[10]
    DIRECTION OUTPUT ;
    USE SIGNAL ;
    PORT
      LAYER M5 ;
        RECT  29.808 21.516 29.832 21.6 ;
    END
  END tx_flit[10]
  PIN tx_flit[110]
    DIRECTION OUTPUT ;
    USE SIGNAL ;
    PORT
      LAYER M5 ;
        RECT  36.336 21.516 36.36 21.6 ;
    END
  END tx_flit[110]
  PIN tx_flit[111]
    DIRECTION OUTPUT ;
    USE SIGNAL ;
    PORT
      LAYER M5 ;
        RECT  36.432 21.516 36.456 21.6 ;
    END
  END tx_flit[111]
  PIN tx_flit[112]
    DIRECTION OUTPUT ;
    USE SIGNAL ;
    PORT
      LAYER M5 ;
        RECT  36.528 21.516 36.552 21.6 ;
    END
  END tx_flit[112]
  PIN tx_flit[113]
    DIRECTION OUTPUT ;
    USE SIGNAL ;
    PORT
      LAYER M5 ;
        RECT  36.624 21.516 36.648 21.6 ;
    END
  END tx_flit[113]
  PIN tx_flit[114]
    DIRECTION OUTPUT ;
    USE SIGNAL ;
    PORT
      LAYER M5 ;
        RECT  36.72 21.516 36.744 21.6 ;
    END
  END tx_flit[114]
  PIN tx_flit[115]
    DIRECTION OUTPUT ;
    USE SIGNAL ;
    PORT
      LAYER M5 ;
        RECT  36.816 21.516 36.84 21.6 ;
    END
  END tx_flit[115]
  PIN tx_flit[116]
    DIRECTION OUTPUT ;
    USE SIGNAL ;
    PORT
      LAYER M5 ;
        RECT  36.912 21.516 36.936 21.6 ;
    END
  END tx_flit[116]
  PIN tx_flit[117]
    DIRECTION OUTPUT ;
    USE SIGNAL ;
    PORT
      LAYER M5 ;
        RECT  37.008 21.516 37.032 21.6 ;
    END
  END tx_flit[117]
  PIN tx_flit[118]
    DIRECTION OUTPUT ;
    USE SIGNAL ;
    PORT
      LAYER M5 ;
        RECT  37.104 21.516 37.128 21.6 ;
    END
  END tx_flit[118]
  PIN tx_flit[119]
    DIRECTION OUTPUT ;
    USE SIGNAL ;
    PORT
      LAYER M5 ;
        RECT  37.2 21.516 37.224 21.6 ;
    END
  END tx_flit[119]
  PIN tx_flit[11]
    DIRECTION OUTPUT ;
    USE SIGNAL ;
    PORT
      LAYER M5 ;
        RECT  29.904 21.516 29.928 21.6 ;
    END
  END tx_flit[11]
  PIN tx_flit[120]
    DIRECTION OUTPUT ;
    USE SIGNAL ;
    PORT
      LAYER M5 ;
        RECT  37.296 21.516 37.32 21.6 ;
    END
  END tx_flit[120]
  PIN tx_flit[121]
    DIRECTION OUTPUT ;
    USE SIGNAL ;
    PORT
      LAYER M5 ;
        RECT  37.392 21.516 37.416 21.6 ;
    END
  END tx_flit[121]
  PIN tx_flit[122]
    DIRECTION OUTPUT ;
    USE SIGNAL ;
    PORT
      LAYER M5 ;
        RECT  37.488 21.516 37.512 21.6 ;
    END
  END tx_flit[122]
  PIN tx_flit[123]
    DIRECTION OUTPUT ;
    USE SIGNAL ;
    PORT
      LAYER M5 ;
        RECT  37.584 21.516 37.608 21.6 ;
    END
  END tx_flit[123]
  PIN tx_flit[124]
    DIRECTION OUTPUT ;
    USE SIGNAL ;
    PORT
      LAYER M5 ;
        RECT  37.68 21.516 37.704 21.6 ;
    END
  END tx_flit[124]
  PIN tx_flit[125]
    DIRECTION OUTPUT ;
    USE SIGNAL ;
    PORT
      LAYER M5 ;
        RECT  37.776 21.516 37.8 21.6 ;
    END
  END tx_flit[125]
  PIN tx_flit[126]
    DIRECTION OUTPUT ;
    USE SIGNAL ;
    PORT
      LAYER M5 ;
        RECT  37.872 21.516 37.896 21.6 ;
    END
  END tx_flit[126]
  PIN tx_flit[127]
    DIRECTION OUTPUT ;
    USE SIGNAL ;
    PORT
      LAYER M5 ;
        RECT  37.968 21.516 37.992 21.6 ;
    END
  END tx_flit[127]
  PIN tx_flit[128]
    DIRECTION OUTPUT ;
    USE SIGNAL ;
    PORT
      LAYER M5 ;
        RECT  44.208 21.516 44.232 21.6 ;
    END
  END tx_flit[128]
  PIN tx_flit[129]
    DIRECTION OUTPUT ;
    USE SIGNAL ;
    PORT
      LAYER M5 ;
        RECT  44.304 21.516 44.328 21.6 ;
    END
  END tx_flit[129]
  PIN tx_flit[12]
    DIRECTION OUTPUT ;
    USE SIGNAL ;
    PORT
      LAYER M5 ;
        RECT  30 21.516 30.024 21.6 ;
    END
  END tx_flit[12]
  PIN tx_flit[130]
    DIRECTION OUTPUT ;
    USE SIGNAL ;
    PORT
      LAYER M5 ;
        RECT  44.4 21.516 44.424 21.6 ;
    END
  END tx_flit[130]
  PIN tx_flit[131]
    DIRECTION OUTPUT ;
    USE SIGNAL ;
    PORT
      LAYER M5 ;
        RECT  44.496 21.516 44.52 21.6 ;
    END
  END tx_flit[131]
  PIN tx_flit[132]
    DIRECTION OUTPUT ;
    USE SIGNAL ;
    PORT
      LAYER M5 ;
        RECT  44.592 21.516 44.616 21.6 ;
    END
  END tx_flit[132]
  PIN tx_flit[133]
    DIRECTION OUTPUT ;
    USE SIGNAL ;
    PORT
      LAYER M5 ;
        RECT  44.688 21.516 44.712 21.6 ;
    END
  END tx_flit[133]
  PIN tx_flit[134]
    DIRECTION OUTPUT ;
    USE SIGNAL ;
    PORT
      LAYER M5 ;
        RECT  44.784 21.516 44.808 21.6 ;
    END
  END tx_flit[134]
  PIN tx_flit[135]
    DIRECTION OUTPUT ;
    USE SIGNAL ;
    PORT
      LAYER M5 ;
        RECT  44.88 21.516 44.904 21.6 ;
    END
  END tx_flit[135]
  PIN tx_flit[136]
    DIRECTION OUTPUT ;
    USE SIGNAL ;
    PORT
      LAYER M5 ;
        RECT  44.976 21.516 45 21.6 ;
    END
  END tx_flit[136]
  PIN tx_flit[137]
    DIRECTION OUTPUT ;
    USE SIGNAL ;
    PORT
      LAYER M5 ;
        RECT  45.072 21.516 45.096 21.6 ;
    END
  END tx_flit[137]
  PIN tx_flit[138]
    DIRECTION OUTPUT ;
    USE SIGNAL ;
    PORT
      LAYER M5 ;
        RECT  45.168 21.516 45.192 21.6 ;
    END
  END tx_flit[138]
  PIN tx_flit[139]
    DIRECTION OUTPUT ;
    USE SIGNAL ;
    PORT
      LAYER M5 ;
        RECT  45.264 21.516 45.288 21.6 ;
    END
  END tx_flit[139]
  PIN tx_flit[13]
    DIRECTION OUTPUT ;
    USE SIGNAL ;
    PORT
      LAYER M5 ;
        RECT  30.096 21.516 30.12 21.6 ;
    END
  END tx_flit[13]
  PIN tx_flit[140]
    DIRECTION OUTPUT ;
    USE SIGNAL ;
    PORT
      LAYER M5 ;
        RECT  45.36 21.516 45.384 21.6 ;
    END
  END tx_flit[140]
  PIN tx_flit[141]
    DIRECTION OUTPUT ;
    USE SIGNAL ;
    PORT
      LAYER M5 ;
        RECT  45.456 21.516 45.48 21.6 ;
    END
  END tx_flit[141]
  PIN tx_flit[142]
    DIRECTION OUTPUT ;
    USE SIGNAL ;
    PORT
      LAYER M5 ;
        RECT  45.552 21.516 45.576 21.6 ;
    END
  END tx_flit[142]
  PIN tx_flit[143]
    DIRECTION OUTPUT ;
    USE SIGNAL ;
    PORT
      LAYER M5 ;
        RECT  45.648 21.516 45.672 21.6 ;
    END
  END tx_flit[143]
  PIN tx_flit[144]
    DIRECTION OUTPUT ;
    USE SIGNAL ;
    PORT
      LAYER M5 ;
        RECT  45.744 21.516 45.768 21.6 ;
    END
  END tx_flit[144]
  PIN tx_flit[145]
    DIRECTION OUTPUT ;
    USE SIGNAL ;
    PORT
      LAYER M5 ;
        RECT  45.84 21.516 45.864 21.6 ;
    END
  END tx_flit[145]
  PIN tx_flit[146]
    DIRECTION OUTPUT ;
    USE SIGNAL ;
    PORT
      LAYER M5 ;
        RECT  45.936 21.516 45.96 21.6 ;
    END
  END tx_flit[146]
  PIN tx_flit[147]
    DIRECTION OUTPUT ;
    USE SIGNAL ;
    PORT
      LAYER M5 ;
        RECT  46.032 21.516 46.056 21.6 ;
    END
  END tx_flit[147]
  PIN tx_flit[148]
    DIRECTION OUTPUT ;
    USE SIGNAL ;
    PORT
      LAYER M5 ;
        RECT  46.128 21.516 46.152 21.6 ;
    END
  END tx_flit[148]
  PIN tx_flit[149]
    DIRECTION OUTPUT ;
    USE SIGNAL ;
    PORT
      LAYER M5 ;
        RECT  46.224 21.516 46.248 21.6 ;
    END
  END tx_flit[149]
  PIN tx_flit[14]
    DIRECTION OUTPUT ;
    USE SIGNAL ;
    PORT
      LAYER M5 ;
        RECT  30.192 21.516 30.216 21.6 ;
    END
  END tx_flit[14]
  PIN tx_flit[150]
    DIRECTION OUTPUT ;
    USE SIGNAL ;
    PORT
      LAYER M5 ;
        RECT  46.32 21.516 46.344 21.6 ;
    END
  END tx_flit[150]
  PIN tx_flit[151]
    DIRECTION OUTPUT ;
    USE SIGNAL ;
    PORT
      LAYER M5 ;
        RECT  46.416 21.516 46.44 21.6 ;
    END
  END tx_flit[151]
  PIN tx_flit[152]
    DIRECTION OUTPUT ;
    USE SIGNAL ;
    PORT
      LAYER M5 ;
        RECT  46.512 21.516 46.536 21.6 ;
    END
  END tx_flit[152]
  PIN tx_flit[153]
    DIRECTION OUTPUT ;
    USE SIGNAL ;
    PORT
      LAYER M5 ;
        RECT  46.608 21.516 46.632 21.6 ;
    END
  END tx_flit[153]
  PIN tx_flit[154]
    DIRECTION OUTPUT ;
    USE SIGNAL ;
    PORT
      LAYER M5 ;
        RECT  46.704 21.516 46.728 21.6 ;
    END
  END tx_flit[154]
  PIN tx_flit[155]
    DIRECTION OUTPUT ;
    USE SIGNAL ;
    PORT
      LAYER M5 ;
        RECT  46.8 21.516 46.824 21.6 ;
    END
  END tx_flit[155]
  PIN tx_flit[156]
    DIRECTION OUTPUT ;
    USE SIGNAL ;
    PORT
      LAYER M5 ;
        RECT  46.896 21.516 46.92 21.6 ;
    END
  END tx_flit[156]
  PIN tx_flit[157]
    DIRECTION OUTPUT ;
    USE SIGNAL ;
    PORT
      LAYER M5 ;
        RECT  46.992 21.516 47.016 21.6 ;
    END
  END tx_flit[157]
  PIN tx_flit[158]
    DIRECTION OUTPUT ;
    USE SIGNAL ;
    PORT
      LAYER M5 ;
        RECT  47.088 21.516 47.112 21.6 ;
    END
  END tx_flit[158]
  PIN tx_flit[159]
    DIRECTION OUTPUT ;
    USE SIGNAL ;
    PORT
      LAYER M5 ;
        RECT  47.184 21.516 47.208 21.6 ;
    END
  END tx_flit[159]
  PIN tx_flit[15]
    DIRECTION OUTPUT ;
    USE SIGNAL ;
    PORT
      LAYER M5 ;
        RECT  30.288 21.516 30.312 21.6 ;
    END
  END tx_flit[15]
  PIN tx_flit[160]
    DIRECTION OUTPUT ;
    USE SIGNAL ;
    PORT
      LAYER M5 ;
        RECT  41.136 21.516 41.16 21.6 ;
    END
  END tx_flit[160]
  PIN tx_flit[161]
    DIRECTION OUTPUT ;
    USE SIGNAL ;
    PORT
      LAYER M5 ;
        RECT  41.232 21.516 41.256 21.6 ;
    END
  END tx_flit[161]
  PIN tx_flit[162]
    DIRECTION OUTPUT ;
    USE SIGNAL ;
    PORT
      LAYER M5 ;
        RECT  41.328 21.516 41.352 21.6 ;
    END
  END tx_flit[162]
  PIN tx_flit[163]
    DIRECTION OUTPUT ;
    USE SIGNAL ;
    PORT
      LAYER M5 ;
        RECT  41.424 21.516 41.448 21.6 ;
    END
  END tx_flit[163]
  PIN tx_flit[164]
    DIRECTION OUTPUT ;
    USE SIGNAL ;
    PORT
      LAYER M5 ;
        RECT  41.52 21.516 41.544 21.6 ;
    END
  END tx_flit[164]
  PIN tx_flit[165]
    DIRECTION OUTPUT ;
    USE SIGNAL ;
    PORT
      LAYER M5 ;
        RECT  41.616 21.516 41.64 21.6 ;
    END
  END tx_flit[165]
  PIN tx_flit[166]
    DIRECTION OUTPUT ;
    USE SIGNAL ;
    PORT
      LAYER M5 ;
        RECT  41.712 21.516 41.736 21.6 ;
    END
  END tx_flit[166]
  PIN tx_flit[167]
    DIRECTION OUTPUT ;
    USE SIGNAL ;
    PORT
      LAYER M5 ;
        RECT  41.808 21.516 41.832 21.6 ;
    END
  END tx_flit[167]
  PIN tx_flit[168]
    DIRECTION OUTPUT ;
    USE SIGNAL ;
    PORT
      LAYER M5 ;
        RECT  41.904 21.516 41.928 21.6 ;
    END
  END tx_flit[168]
  PIN tx_flit[169]
    DIRECTION OUTPUT ;
    USE SIGNAL ;
    PORT
      LAYER M5 ;
        RECT  42 21.516 42.024 21.6 ;
    END
  END tx_flit[169]
  PIN tx_flit[16]
    DIRECTION OUTPUT ;
    USE SIGNAL ;
    PORT
      LAYER M5 ;
        RECT  30.384 21.516 30.408 21.6 ;
    END
  END tx_flit[16]
  PIN tx_flit[170]
    DIRECTION OUTPUT ;
    USE SIGNAL ;
    PORT
      LAYER M5 ;
        RECT  42.096 21.516 42.12 21.6 ;
    END
  END tx_flit[170]
  PIN tx_flit[171]
    DIRECTION OUTPUT ;
    USE SIGNAL ;
    PORT
      LAYER M5 ;
        RECT  42.192 21.516 42.216 21.6 ;
    END
  END tx_flit[171]
  PIN tx_flit[172]
    DIRECTION OUTPUT ;
    USE SIGNAL ;
    PORT
      LAYER M5 ;
        RECT  42.288 21.516 42.312 21.6 ;
    END
  END tx_flit[172]
  PIN tx_flit[173]
    DIRECTION OUTPUT ;
    USE SIGNAL ;
    PORT
      LAYER M5 ;
        RECT  42.384 21.516 42.408 21.6 ;
    END
  END tx_flit[173]
  PIN tx_flit[174]
    DIRECTION OUTPUT ;
    USE SIGNAL ;
    PORT
      LAYER M5 ;
        RECT  42.48 21.516 42.504 21.6 ;
    END
  END tx_flit[174]
  PIN tx_flit[175]
    DIRECTION OUTPUT ;
    USE SIGNAL ;
    PORT
      LAYER M5 ;
        RECT  42.576 21.516 42.6 21.6 ;
    END
  END tx_flit[175]
  PIN tx_flit[176]
    DIRECTION OUTPUT ;
    USE SIGNAL ;
    PORT
      LAYER M5 ;
        RECT  42.672 21.516 42.696 21.6 ;
    END
  END tx_flit[176]
  PIN tx_flit[177]
    DIRECTION OUTPUT ;
    USE SIGNAL ;
    PORT
      LAYER M5 ;
        RECT  42.768 21.516 42.792 21.6 ;
    END
  END tx_flit[177]
  PIN tx_flit[178]
    DIRECTION OUTPUT ;
    USE SIGNAL ;
    PORT
      LAYER M5 ;
        RECT  42.864 21.516 42.888 21.6 ;
    END
  END tx_flit[178]
  PIN tx_flit[179]
    DIRECTION OUTPUT ;
    USE SIGNAL ;
    PORT
      LAYER M5 ;
        RECT  42.96 21.516 42.984 21.6 ;
    END
  END tx_flit[179]
  PIN tx_flit[17]
    DIRECTION OUTPUT ;
    USE SIGNAL ;
    PORT
      LAYER M5 ;
        RECT  30.48 21.516 30.504 21.6 ;
    END
  END tx_flit[17]
  PIN tx_flit[180]
    DIRECTION OUTPUT ;
    USE SIGNAL ;
    PORT
      LAYER M5 ;
        RECT  43.056 21.516 43.08 21.6 ;
    END
  END tx_flit[180]
  PIN tx_flit[181]
    DIRECTION OUTPUT ;
    USE SIGNAL ;
    PORT
      LAYER M5 ;
        RECT  43.152 21.516 43.176 21.6 ;
    END
  END tx_flit[181]
  PIN tx_flit[182]
    DIRECTION OUTPUT ;
    USE SIGNAL ;
    PORT
      LAYER M5 ;
        RECT  43.248 21.516 43.272 21.6 ;
    END
  END tx_flit[182]
  PIN tx_flit[183]
    DIRECTION OUTPUT ;
    USE SIGNAL ;
    PORT
      LAYER M5 ;
        RECT  43.344 21.516 43.368 21.6 ;
    END
  END tx_flit[183]
  PIN tx_flit[184]
    DIRECTION OUTPUT ;
    USE SIGNAL ;
    PORT
      LAYER M5 ;
        RECT  43.44 21.516 43.464 21.6 ;
    END
  END tx_flit[184]
  PIN tx_flit[185]
    DIRECTION OUTPUT ;
    USE SIGNAL ;
    PORT
      LAYER M5 ;
        RECT  43.536 21.516 43.56 21.6 ;
    END
  END tx_flit[185]
  PIN tx_flit[186]
    DIRECTION OUTPUT ;
    USE SIGNAL ;
    PORT
      LAYER M5 ;
        RECT  43.632 21.516 43.656 21.6 ;
    END
  END tx_flit[186]
  PIN tx_flit[187]
    DIRECTION OUTPUT ;
    USE SIGNAL ;
    PORT
      LAYER M5 ;
        RECT  43.728 21.516 43.752 21.6 ;
    END
  END tx_flit[187]
  PIN tx_flit[188]
    DIRECTION OUTPUT ;
    USE SIGNAL ;
    PORT
      LAYER M5 ;
        RECT  43.824 21.516 43.848 21.6 ;
    END
  END tx_flit[188]
  PIN tx_flit[189]
    DIRECTION OUTPUT ;
    USE SIGNAL ;
    PORT
      LAYER M5 ;
        RECT  43.92 21.516 43.944 21.6 ;
    END
  END tx_flit[189]
  PIN tx_flit[18]
    DIRECTION OUTPUT ;
    USE SIGNAL ;
    PORT
      LAYER M5 ;
        RECT  30.576 21.516 30.6 21.6 ;
    END
  END tx_flit[18]
  PIN tx_flit[190]
    DIRECTION OUTPUT ;
    USE SIGNAL ;
    PORT
      LAYER M5 ;
        RECT  44.016 21.516 44.04 21.6 ;
    END
  END tx_flit[190]
  PIN tx_flit[191]
    DIRECTION OUTPUT ;
    USE SIGNAL ;
    PORT
      LAYER M5 ;
        RECT  44.112 21.516 44.136 21.6 ;
    END
  END tx_flit[191]
  PIN tx_flit[192]
    DIRECTION OUTPUT ;
    USE SIGNAL ;
    PORT
      LAYER M5 ;
        RECT  57.264 21.516 57.288 21.6 ;
    END
  END tx_flit[192]
  PIN tx_flit[193]
    DIRECTION OUTPUT ;
    USE SIGNAL ;
    PORT
      LAYER M5 ;
        RECT  57.36 21.516 57.384 21.6 ;
    END
  END tx_flit[193]
  PIN tx_flit[194]
    DIRECTION OUTPUT ;
    USE SIGNAL ;
    PORT
      LAYER M5 ;
        RECT  57.456 21.516 57.48 21.6 ;
    END
  END tx_flit[194]
  PIN tx_flit[195]
    DIRECTION OUTPUT ;
    USE SIGNAL ;
    PORT
      LAYER M5 ;
        RECT  57.552 21.516 57.576 21.6 ;
    END
  END tx_flit[195]
  PIN tx_flit[196]
    DIRECTION OUTPUT ;
    USE SIGNAL ;
    PORT
      LAYER M5 ;
        RECT  57.648 21.516 57.672 21.6 ;
    END
  END tx_flit[196]
  PIN tx_flit[197]
    DIRECTION OUTPUT ;
    USE SIGNAL ;
    PORT
      LAYER M5 ;
        RECT  57.744 21.516 57.768 21.6 ;
    END
  END tx_flit[197]
  PIN tx_flit[198]
    DIRECTION OUTPUT ;
    USE SIGNAL ;
    PORT
      LAYER M5 ;
        RECT  57.84 21.516 57.864 21.6 ;
    END
  END tx_flit[198]
  PIN tx_flit[199]
    DIRECTION OUTPUT ;
    USE SIGNAL ;
    PORT
      LAYER M5 ;
        RECT  57.936 21.516 57.96 21.6 ;
    END
  END tx_flit[199]
  PIN tx_flit[19]
    DIRECTION OUTPUT ;
    USE SIGNAL ;
    PORT
      LAYER M5 ;
        RECT  30.672 21.516 30.696 21.6 ;
    END
  END tx_flit[19]
  PIN tx_flit[1]
    DIRECTION OUTPUT ;
    USE SIGNAL ;
    PORT
      LAYER M5 ;
        RECT  28.944 21.516 28.968 21.6 ;
    END
  END tx_flit[1]
  PIN tx_flit[200]
    DIRECTION OUTPUT ;
    USE SIGNAL ;
    PORT
      LAYER M5 ;
        RECT  58.032 21.516 58.056 21.6 ;
    END
  END tx_flit[200]
  PIN tx_flit[201]
    DIRECTION OUTPUT ;
    USE SIGNAL ;
    PORT
      LAYER M5 ;
        RECT  58.128 21.516 58.152 21.6 ;
    END
  END tx_flit[201]
  PIN tx_flit[202]
    DIRECTION OUTPUT ;
    USE SIGNAL ;
    PORT
      LAYER M5 ;
        RECT  58.224 21.516 58.248 21.6 ;
    END
  END tx_flit[202]
  PIN tx_flit[203]
    DIRECTION OUTPUT ;
    USE SIGNAL ;
    PORT
      LAYER M5 ;
        RECT  58.32 21.516 58.344 21.6 ;
    END
  END tx_flit[203]
  PIN tx_flit[204]
    DIRECTION OUTPUT ;
    USE SIGNAL ;
    PORT
      LAYER M5 ;
        RECT  58.416 21.516 58.44 21.6 ;
    END
  END tx_flit[204]
  PIN tx_flit[205]
    DIRECTION OUTPUT ;
    USE SIGNAL ;
    PORT
      LAYER M5 ;
        RECT  58.512 21.516 58.536 21.6 ;
    END
  END tx_flit[205]
  PIN tx_flit[206]
    DIRECTION OUTPUT ;
    USE SIGNAL ;
    PORT
      LAYER M5 ;
        RECT  58.608 21.516 58.632 21.6 ;
    END
  END tx_flit[206]
  PIN tx_flit[207]
    DIRECTION OUTPUT ;
    USE SIGNAL ;
    PORT
      LAYER M5 ;
        RECT  58.704 21.516 58.728 21.6 ;
    END
  END tx_flit[207]
  PIN tx_flit[208]
    DIRECTION OUTPUT ;
    USE SIGNAL ;
    PORT
      LAYER M5 ;
        RECT  58.8 21.516 58.824 21.6 ;
    END
  END tx_flit[208]
  PIN tx_flit[209]
    DIRECTION OUTPUT ;
    USE SIGNAL ;
    PORT
      LAYER M5 ;
        RECT  58.896 21.516 58.92 21.6 ;
    END
  END tx_flit[209]
  PIN tx_flit[20]
    DIRECTION OUTPUT ;
    USE SIGNAL ;
    PORT
      LAYER M5 ;
        RECT  30.768 21.516 30.792 21.6 ;
    END
  END tx_flit[20]
  PIN tx_flit[210]
    DIRECTION OUTPUT ;
    USE SIGNAL ;
    PORT
      LAYER M5 ;
        RECT  58.992 21.516 59.016 21.6 ;
    END
  END tx_flit[210]
  PIN tx_flit[211]
    DIRECTION OUTPUT ;
    USE SIGNAL ;
    PORT
      LAYER M5 ;
        RECT  59.088 21.516 59.112 21.6 ;
    END
  END tx_flit[211]
  PIN tx_flit[212]
    DIRECTION OUTPUT ;
    USE SIGNAL ;
    PORT
      LAYER M5 ;
        RECT  59.184 21.516 59.208 21.6 ;
    END
  END tx_flit[212]
  PIN tx_flit[213]
    DIRECTION OUTPUT ;
    USE SIGNAL ;
    PORT
      LAYER M5 ;
        RECT  59.28 21.516 59.304 21.6 ;
    END
  END tx_flit[213]
  PIN tx_flit[214]
    DIRECTION OUTPUT ;
    USE SIGNAL ;
    PORT
      LAYER M5 ;
        RECT  59.376 21.516 59.4 21.6 ;
    END
  END tx_flit[214]
  PIN tx_flit[215]
    DIRECTION OUTPUT ;
    USE SIGNAL ;
    PORT
      LAYER M5 ;
        RECT  59.472 21.516 59.496 21.6 ;
    END
  END tx_flit[215]
  PIN tx_flit[216]
    DIRECTION OUTPUT ;
    USE SIGNAL ;
    PORT
      LAYER M5 ;
        RECT  59.568 21.516 59.592 21.6 ;
    END
  END tx_flit[216]
  PIN tx_flit[217]
    DIRECTION OUTPUT ;
    USE SIGNAL ;
    PORT
      LAYER M5 ;
        RECT  59.664 21.516 59.688 21.6 ;
    END
  END tx_flit[217]
  PIN tx_flit[218]
    DIRECTION OUTPUT ;
    USE SIGNAL ;
    PORT
      LAYER M5 ;
        RECT  59.76 21.516 59.784 21.6 ;
    END
  END tx_flit[218]
  PIN tx_flit[219]
    DIRECTION OUTPUT ;
    USE SIGNAL ;
    PORT
      LAYER M5 ;
        RECT  59.856 21.516 59.88 21.6 ;
    END
  END tx_flit[219]
  PIN tx_flit[21]
    DIRECTION OUTPUT ;
    USE SIGNAL ;
    PORT
      LAYER M5 ;
        RECT  30.864 21.516 30.888 21.6 ;
    END
  END tx_flit[21]
  PIN tx_flit[220]
    DIRECTION OUTPUT ;
    USE SIGNAL ;
    PORT
      LAYER M5 ;
        RECT  59.952 21.516 59.976 21.6 ;
    END
  END tx_flit[220]
  PIN tx_flit[221]
    DIRECTION OUTPUT ;
    USE SIGNAL ;
    PORT
      LAYER M5 ;
        RECT  60.048 21.516 60.072 21.6 ;
    END
  END tx_flit[221]
  PIN tx_flit[222]
    DIRECTION OUTPUT ;
    USE SIGNAL ;
    PORT
      LAYER M5 ;
        RECT  60.144 21.516 60.168 21.6 ;
    END
  END tx_flit[222]
  PIN tx_flit[223]
    DIRECTION OUTPUT ;
    USE SIGNAL ;
    PORT
      LAYER M5 ;
        RECT  60.24 21.516 60.264 21.6 ;
    END
  END tx_flit[223]
  PIN tx_flit[224]
    DIRECTION OUTPUT ;
    USE SIGNAL ;
    PORT
      LAYER M5 ;
        RECT  48.048 21.516 48.072 21.6 ;
    END
  END tx_flit[224]
  PIN tx_flit[225]
    DIRECTION OUTPUT ;
    USE SIGNAL ;
    PORT
      LAYER M5 ;
        RECT  48.144 21.516 48.168 21.6 ;
    END
  END tx_flit[225]
  PIN tx_flit[226]
    DIRECTION OUTPUT ;
    USE SIGNAL ;
    PORT
      LAYER M5 ;
        RECT  48.24 21.516 48.264 21.6 ;
    END
  END tx_flit[226]
  PIN tx_flit[227]
    DIRECTION OUTPUT ;
    USE SIGNAL ;
    PORT
      LAYER M5 ;
        RECT  48.336 21.516 48.36 21.6 ;
    END
  END tx_flit[227]
  PIN tx_flit[228]
    DIRECTION OUTPUT ;
    USE SIGNAL ;
    PORT
      LAYER M5 ;
        RECT  48.432 21.516 48.456 21.6 ;
    END
  END tx_flit[228]
  PIN tx_flit[229]
    DIRECTION OUTPUT ;
    USE SIGNAL ;
    PORT
      LAYER M5 ;
        RECT  48.528 21.516 48.552 21.6 ;
    END
  END tx_flit[229]
  PIN tx_flit[22]
    DIRECTION OUTPUT ;
    USE SIGNAL ;
    PORT
      LAYER M5 ;
        RECT  30.96 21.516 30.984 21.6 ;
    END
  END tx_flit[22]
  PIN tx_flit[230]
    DIRECTION OUTPUT ;
    USE SIGNAL ;
    PORT
      LAYER M5 ;
        RECT  48.624 21.516 48.648 21.6 ;
    END
  END tx_flit[230]
  PIN tx_flit[231]
    DIRECTION OUTPUT ;
    USE SIGNAL ;
    PORT
      LAYER M5 ;
        RECT  48.72 21.516 48.744 21.6 ;
    END
  END tx_flit[231]
  PIN tx_flit[232]
    DIRECTION OUTPUT ;
    USE SIGNAL ;
    PORT
      LAYER M5 ;
        RECT  48.816 21.516 48.84 21.6 ;
    END
  END tx_flit[232]
  PIN tx_flit[233]
    DIRECTION OUTPUT ;
    USE SIGNAL ;
    PORT
      LAYER M5 ;
        RECT  48.912 21.516 48.936 21.6 ;
    END
  END tx_flit[233]
  PIN tx_flit[234]
    DIRECTION OUTPUT ;
    USE SIGNAL ;
    PORT
      LAYER M5 ;
        RECT  49.008 21.516 49.032 21.6 ;
    END
  END tx_flit[234]
  PIN tx_flit[235]
    DIRECTION OUTPUT ;
    USE SIGNAL ;
    PORT
      LAYER M5 ;
        RECT  49.104 21.516 49.128 21.6 ;
    END
  END tx_flit[235]
  PIN tx_flit[236]
    DIRECTION OUTPUT ;
    USE SIGNAL ;
    PORT
      LAYER M5 ;
        RECT  49.2 21.516 49.224 21.6 ;
    END
  END tx_flit[236]
  PIN tx_flit[237]
    DIRECTION OUTPUT ;
    USE SIGNAL ;
    PORT
      LAYER M5 ;
        RECT  49.296 21.516 49.32 21.6 ;
    END
  END tx_flit[237]
  PIN tx_flit[238]
    DIRECTION OUTPUT ;
    USE SIGNAL ;
    PORT
      LAYER M5 ;
        RECT  49.392 21.516 49.416 21.6 ;
    END
  END tx_flit[238]
  PIN tx_flit[239]
    DIRECTION OUTPUT ;
    USE SIGNAL ;
    PORT
      LAYER M5 ;
        RECT  49.488 21.516 49.512 21.6 ;
    END
  END tx_flit[239]
  PIN tx_flit[23]
    DIRECTION OUTPUT ;
    USE SIGNAL ;
    PORT
      LAYER M5 ;
        RECT  31.056 21.516 31.08 21.6 ;
    END
  END tx_flit[23]
  PIN tx_flit[240]
    DIRECTION OUTPUT ;
    USE SIGNAL ;
    PORT
      LAYER M5 ;
        RECT  49.584 21.516 49.608 21.6 ;
    END
  END tx_flit[240]
  PIN tx_flit[241]
    DIRECTION OUTPUT ;
    USE SIGNAL ;
    PORT
      LAYER M5 ;
        RECT  49.68 21.516 49.704 21.6 ;
    END
  END tx_flit[241]
  PIN tx_flit[242]
    DIRECTION OUTPUT ;
    USE SIGNAL ;
    PORT
      LAYER M5 ;
        RECT  49.776 21.516 49.8 21.6 ;
    END
  END tx_flit[242]
  PIN tx_flit[243]
    DIRECTION OUTPUT ;
    USE SIGNAL ;
    PORT
      LAYER M5 ;
        RECT  49.872 21.516 49.896 21.6 ;
    END
  END tx_flit[243]
  PIN tx_flit[244]
    DIRECTION OUTPUT ;
    USE SIGNAL ;
    PORT
      LAYER M5 ;
        RECT  49.968 21.516 49.992 21.6 ;
    END
  END tx_flit[244]
  PIN tx_flit[245]
    DIRECTION OUTPUT ;
    USE SIGNAL ;
    PORT
      LAYER M5 ;
        RECT  50.064 21.516 50.088 21.6 ;
    END
  END tx_flit[245]
  PIN tx_flit[246]
    DIRECTION OUTPUT ;
    USE SIGNAL ;
    PORT
      LAYER M5 ;
        RECT  50.16 21.516 50.184 21.6 ;
    END
  END tx_flit[246]
  PIN tx_flit[247]
    DIRECTION OUTPUT ;
    USE SIGNAL ;
    PORT
      LAYER M5 ;
        RECT  50.256 21.516 50.28 21.6 ;
    END
  END tx_flit[247]
  PIN tx_flit[248]
    DIRECTION OUTPUT ;
    USE SIGNAL ;
    PORT
      LAYER M5 ;
        RECT  50.352 21.516 50.376 21.6 ;
    END
  END tx_flit[248]
  PIN tx_flit[249]
    DIRECTION OUTPUT ;
    USE SIGNAL ;
    PORT
      LAYER M5 ;
        RECT  50.448 21.516 50.472 21.6 ;
    END
  END tx_flit[249]
  PIN tx_flit[24]
    DIRECTION OUTPUT ;
    USE SIGNAL ;
    PORT
      LAYER M5 ;
        RECT  31.152 21.516 31.176 21.6 ;
    END
  END tx_flit[24]
  PIN tx_flit[250]
    DIRECTION OUTPUT ;
    USE SIGNAL ;
    PORT
      LAYER M5 ;
        RECT  50.544 21.516 50.568 21.6 ;
    END
  END tx_flit[250]
  PIN tx_flit[251]
    DIRECTION OUTPUT ;
    USE SIGNAL ;
    PORT
      LAYER M5 ;
        RECT  50.64 21.516 50.664 21.6 ;
    END
  END tx_flit[251]
  PIN tx_flit[252]
    DIRECTION OUTPUT ;
    USE SIGNAL ;
    PORT
      LAYER M5 ;
        RECT  50.736 21.516 50.76 21.6 ;
    END
  END tx_flit[252]
  PIN tx_flit[253]
    DIRECTION OUTPUT ;
    USE SIGNAL ;
    PORT
      LAYER M5 ;
        RECT  50.832 21.516 50.856 21.6 ;
    END
  END tx_flit[253]
  PIN tx_flit[254]
    DIRECTION OUTPUT ;
    USE SIGNAL ;
    PORT
      LAYER M5 ;
        RECT  50.928 21.516 50.952 21.6 ;
    END
  END tx_flit[254]
  PIN tx_flit[255]
    DIRECTION OUTPUT ;
    USE SIGNAL ;
    PORT
      LAYER M5 ;
        RECT  51.024 21.516 51.048 21.6 ;
    END
  END tx_flit[255]
  PIN tx_flit[256]
    DIRECTION OUTPUT ;
    USE SIGNAL ;
    PORT
      LAYER M5 ;
        RECT  54.192 21.516 54.216 21.6 ;
    END
  END tx_flit[256]
  PIN tx_flit[257]
    DIRECTION OUTPUT ;
    USE SIGNAL ;
    PORT
      LAYER M5 ;
        RECT  54.288 21.516 54.312 21.6 ;
    END
  END tx_flit[257]
  PIN tx_flit[258]
    DIRECTION OUTPUT ;
    USE SIGNAL ;
    PORT
      LAYER M5 ;
        RECT  54.384 21.516 54.408 21.6 ;
    END
  END tx_flit[258]
  PIN tx_flit[259]
    DIRECTION OUTPUT ;
    USE SIGNAL ;
    PORT
      LAYER M5 ;
        RECT  54.48 21.516 54.504 21.6 ;
    END
  END tx_flit[259]
  PIN tx_flit[25]
    DIRECTION OUTPUT ;
    USE SIGNAL ;
    PORT
      LAYER M5 ;
        RECT  31.248 21.516 31.272 21.6 ;
    END
  END tx_flit[25]
  PIN tx_flit[260]
    DIRECTION OUTPUT ;
    USE SIGNAL ;
    PORT
      LAYER M5 ;
        RECT  54.576 21.516 54.6 21.6 ;
    END
  END tx_flit[260]
  PIN tx_flit[261]
    DIRECTION OUTPUT ;
    USE SIGNAL ;
    PORT
      LAYER M5 ;
        RECT  54.672 21.516 54.696 21.6 ;
    END
  END tx_flit[261]
  PIN tx_flit[262]
    DIRECTION OUTPUT ;
    USE SIGNAL ;
    PORT
      LAYER M5 ;
        RECT  54.768 21.516 54.792 21.6 ;
    END
  END tx_flit[262]
  PIN tx_flit[263]
    DIRECTION OUTPUT ;
    USE SIGNAL ;
    PORT
      LAYER M5 ;
        RECT  54.864 21.516 54.888 21.6 ;
    END
  END tx_flit[263]
  PIN tx_flit[264]
    DIRECTION OUTPUT ;
    USE SIGNAL ;
    PORT
      LAYER M5 ;
        RECT  54.96 21.516 54.984 21.6 ;
    END
  END tx_flit[264]
  PIN tx_flit[265]
    DIRECTION OUTPUT ;
    USE SIGNAL ;
    PORT
      LAYER M5 ;
        RECT  55.056 21.516 55.08 21.6 ;
    END
  END tx_flit[265]
  PIN tx_flit[266]
    DIRECTION OUTPUT ;
    USE SIGNAL ;
    PORT
      LAYER M5 ;
        RECT  55.152 21.516 55.176 21.6 ;
    END
  END tx_flit[266]
  PIN tx_flit[267]
    DIRECTION OUTPUT ;
    USE SIGNAL ;
    PORT
      LAYER M5 ;
        RECT  55.248 21.516 55.272 21.6 ;
    END
  END tx_flit[267]
  PIN tx_flit[268]
    DIRECTION OUTPUT ;
    USE SIGNAL ;
    PORT
      LAYER M5 ;
        RECT  55.344 21.516 55.368 21.6 ;
    END
  END tx_flit[268]
  PIN tx_flit[269]
    DIRECTION OUTPUT ;
    USE SIGNAL ;
    PORT
      LAYER M5 ;
        RECT  55.44 21.516 55.464 21.6 ;
    END
  END tx_flit[269]
  PIN tx_flit[26]
    DIRECTION OUTPUT ;
    USE SIGNAL ;
    PORT
      LAYER M5 ;
        RECT  31.344 21.516 31.368 21.6 ;
    END
  END tx_flit[26]
  PIN tx_flit[270]
    DIRECTION OUTPUT ;
    USE SIGNAL ;
    PORT
      LAYER M5 ;
        RECT  55.536 21.516 55.56 21.6 ;
    END
  END tx_flit[270]
  PIN tx_flit[271]
    DIRECTION OUTPUT ;
    USE SIGNAL ;
    PORT
      LAYER M5 ;
        RECT  55.632 21.516 55.656 21.6 ;
    END
  END tx_flit[271]
  PIN tx_flit[272]
    DIRECTION OUTPUT ;
    USE SIGNAL ;
    PORT
      LAYER M5 ;
        RECT  55.728 21.516 55.752 21.6 ;
    END
  END tx_flit[272]
  PIN tx_flit[273]
    DIRECTION OUTPUT ;
    USE SIGNAL ;
    PORT
      LAYER M5 ;
        RECT  55.824 21.516 55.848 21.6 ;
    END
  END tx_flit[273]
  PIN tx_flit[274]
    DIRECTION OUTPUT ;
    USE SIGNAL ;
    PORT
      LAYER M5 ;
        RECT  55.92 21.516 55.944 21.6 ;
    END
  END tx_flit[274]
  PIN tx_flit[275]
    DIRECTION OUTPUT ;
    USE SIGNAL ;
    PORT
      LAYER M5 ;
        RECT  56.016 21.516 56.04 21.6 ;
    END
  END tx_flit[275]
  PIN tx_flit[276]
    DIRECTION OUTPUT ;
    USE SIGNAL ;
    PORT
      LAYER M5 ;
        RECT  56.112 21.516 56.136 21.6 ;
    END
  END tx_flit[276]
  PIN tx_flit[277]
    DIRECTION OUTPUT ;
    USE SIGNAL ;
    PORT
      LAYER M5 ;
        RECT  56.208 21.516 56.232 21.6 ;
    END
  END tx_flit[277]
  PIN tx_flit[278]
    DIRECTION OUTPUT ;
    USE SIGNAL ;
    PORT
      LAYER M5 ;
        RECT  56.304 21.516 56.328 21.6 ;
    END
  END tx_flit[278]
  PIN tx_flit[279]
    DIRECTION OUTPUT ;
    USE SIGNAL ;
    PORT
      LAYER M5 ;
        RECT  56.4 21.516 56.424 21.6 ;
    END
  END tx_flit[279]
  PIN tx_flit[27]
    DIRECTION OUTPUT ;
    USE SIGNAL ;
    PORT
      LAYER M5 ;
        RECT  31.44 21.516 31.464 21.6 ;
    END
  END tx_flit[27]
  PIN tx_flit[280]
    DIRECTION OUTPUT ;
    USE SIGNAL ;
    PORT
      LAYER M5 ;
        RECT  56.496 21.516 56.52 21.6 ;
    END
  END tx_flit[280]
  PIN tx_flit[281]
    DIRECTION OUTPUT ;
    USE SIGNAL ;
    PORT
      LAYER M5 ;
        RECT  56.592 21.516 56.616 21.6 ;
    END
  END tx_flit[281]
  PIN tx_flit[282]
    DIRECTION OUTPUT ;
    USE SIGNAL ;
    PORT
      LAYER M5 ;
        RECT  56.688 21.516 56.712 21.6 ;
    END
  END tx_flit[282]
  PIN tx_flit[283]
    DIRECTION OUTPUT ;
    USE SIGNAL ;
    PORT
      LAYER M5 ;
        RECT  56.784 21.516 56.808 21.6 ;
    END
  END tx_flit[283]
  PIN tx_flit[284]
    DIRECTION OUTPUT ;
    USE SIGNAL ;
    PORT
      LAYER M5 ;
        RECT  56.88 21.516 56.904 21.6 ;
    END
  END tx_flit[284]
  PIN tx_flit[285]
    DIRECTION OUTPUT ;
    USE SIGNAL ;
    PORT
      LAYER M5 ;
        RECT  56.976 21.516 57 21.6 ;
    END
  END tx_flit[285]
  PIN tx_flit[286]
    DIRECTION OUTPUT ;
    USE SIGNAL ;
    PORT
      LAYER M5 ;
        RECT  57.072 21.516 57.096 21.6 ;
    END
  END tx_flit[286]
  PIN tx_flit[287]
    DIRECTION OUTPUT ;
    USE SIGNAL ;
    PORT
      LAYER M5 ;
        RECT  57.168 21.516 57.192 21.6 ;
    END
  END tx_flit[287]
  PIN tx_flit[288]
    DIRECTION OUTPUT ;
    USE SIGNAL ;
    PORT
      LAYER M5 ;
        RECT  51.12 21.516 51.144 21.6 ;
    END
  END tx_flit[288]
  PIN tx_flit[289]
    DIRECTION OUTPUT ;
    USE SIGNAL ;
    PORT
      LAYER M5 ;
        RECT  51.216 21.516 51.24 21.6 ;
    END
  END tx_flit[289]
  PIN tx_flit[28]
    DIRECTION OUTPUT ;
    USE SIGNAL ;
    PORT
      LAYER M5 ;
        RECT  31.536 21.516 31.56 21.6 ;
    END
  END tx_flit[28]
  PIN tx_flit[290]
    DIRECTION OUTPUT ;
    USE SIGNAL ;
    PORT
      LAYER M5 ;
        RECT  51.312 21.516 51.336 21.6 ;
    END
  END tx_flit[290]
  PIN tx_flit[291]
    DIRECTION OUTPUT ;
    USE SIGNAL ;
    PORT
      LAYER M5 ;
        RECT  51.408 21.516 51.432 21.6 ;
    END
  END tx_flit[291]
  PIN tx_flit[292]
    DIRECTION OUTPUT ;
    USE SIGNAL ;
    PORT
      LAYER M5 ;
        RECT  51.504 21.516 51.528 21.6 ;
    END
  END tx_flit[292]
  PIN tx_flit[293]
    DIRECTION OUTPUT ;
    USE SIGNAL ;
    PORT
      LAYER M5 ;
        RECT  51.6 21.516 51.624 21.6 ;
    END
  END tx_flit[293]
  PIN tx_flit[294]
    DIRECTION OUTPUT ;
    USE SIGNAL ;
    PORT
      LAYER M5 ;
        RECT  51.696 21.516 51.72 21.6 ;
    END
  END tx_flit[294]
  PIN tx_flit[295]
    DIRECTION OUTPUT ;
    USE SIGNAL ;
    PORT
      LAYER M5 ;
        RECT  51.792 21.516 51.816 21.6 ;
    END
  END tx_flit[295]
  PIN tx_flit[296]
    DIRECTION OUTPUT ;
    USE SIGNAL ;
    PORT
      LAYER M5 ;
        RECT  51.888 21.516 51.912 21.6 ;
    END
  END tx_flit[296]
  PIN tx_flit[297]
    DIRECTION OUTPUT ;
    USE SIGNAL ;
    PORT
      LAYER M5 ;
        RECT  51.984 21.516 52.008 21.6 ;
    END
  END tx_flit[297]
  PIN tx_flit[298]
    DIRECTION OUTPUT ;
    USE SIGNAL ;
    PORT
      LAYER M5 ;
        RECT  52.08 21.516 52.104 21.6 ;
    END
  END tx_flit[298]
  PIN tx_flit[299]
    DIRECTION OUTPUT ;
    USE SIGNAL ;
    PORT
      LAYER M5 ;
        RECT  52.176 21.516 52.2 21.6 ;
    END
  END tx_flit[299]
  PIN tx_flit[29]
    DIRECTION OUTPUT ;
    USE SIGNAL ;
    PORT
      LAYER M5 ;
        RECT  31.632 21.516 31.656 21.6 ;
    END
  END tx_flit[29]
  PIN tx_flit[2]
    DIRECTION OUTPUT ;
    USE SIGNAL ;
    PORT
      LAYER M5 ;
        RECT  29.04 21.516 29.064 21.6 ;
    END
  END tx_flit[2]
  PIN tx_flit[300]
    DIRECTION OUTPUT ;
    USE SIGNAL ;
    PORT
      LAYER M5 ;
        RECT  52.272 21.516 52.296 21.6 ;
    END
  END tx_flit[300]
  PIN tx_flit[301]
    DIRECTION OUTPUT ;
    USE SIGNAL ;
    PORT
      LAYER M5 ;
        RECT  52.368 21.516 52.392 21.6 ;
    END
  END tx_flit[301]
  PIN tx_flit[302]
    DIRECTION OUTPUT ;
    USE SIGNAL ;
    PORT
      LAYER M5 ;
        RECT  52.464 21.516 52.488 21.6 ;
    END
  END tx_flit[302]
  PIN tx_flit[303]
    DIRECTION OUTPUT ;
    USE SIGNAL ;
    PORT
      LAYER M5 ;
        RECT  52.56 21.516 52.584 21.6 ;
    END
  END tx_flit[303]
  PIN tx_flit[304]
    DIRECTION OUTPUT ;
    USE SIGNAL ;
    PORT
      LAYER M5 ;
        RECT  52.656 21.516 52.68 21.6 ;
    END
  END tx_flit[304]
  PIN tx_flit[305]
    DIRECTION OUTPUT ;
    USE SIGNAL ;
    PORT
      LAYER M5 ;
        RECT  52.752 21.516 52.776 21.6 ;
    END
  END tx_flit[305]
  PIN tx_flit[306]
    DIRECTION OUTPUT ;
    USE SIGNAL ;
    PORT
      LAYER M5 ;
        RECT  52.848 21.516 52.872 21.6 ;
    END
  END tx_flit[306]
  PIN tx_flit[307]
    DIRECTION OUTPUT ;
    USE SIGNAL ;
    PORT
      LAYER M5 ;
        RECT  52.944 21.516 52.968 21.6 ;
    END
  END tx_flit[307]
  PIN tx_flit[308]
    DIRECTION OUTPUT ;
    USE SIGNAL ;
    PORT
      LAYER M5 ;
        RECT  53.04 21.516 53.064 21.6 ;
    END
  END tx_flit[308]
  PIN tx_flit[309]
    DIRECTION OUTPUT ;
    USE SIGNAL ;
    PORT
      LAYER M5 ;
        RECT  53.136 21.516 53.16 21.6 ;
    END
  END tx_flit[309]
  PIN tx_flit[30]
    DIRECTION OUTPUT ;
    USE SIGNAL ;
    PORT
      LAYER M5 ;
        RECT  31.728 21.516 31.752 21.6 ;
    END
  END tx_flit[30]
  PIN tx_flit[310]
    DIRECTION OUTPUT ;
    USE SIGNAL ;
    PORT
      LAYER M5 ;
        RECT  53.232 21.516 53.256 21.6 ;
    END
  END tx_flit[310]
  PIN tx_flit[311]
    DIRECTION OUTPUT ;
    USE SIGNAL ;
    PORT
      LAYER M5 ;
        RECT  53.328 21.516 53.352 21.6 ;
    END
  END tx_flit[311]
  PIN tx_flit[312]
    DIRECTION OUTPUT ;
    USE SIGNAL ;
    PORT
      LAYER M5 ;
        RECT  53.424 21.516 53.448 21.6 ;
    END
  END tx_flit[312]
  PIN tx_flit[313]
    DIRECTION OUTPUT ;
    USE SIGNAL ;
    PORT
      LAYER M5 ;
        RECT  53.52 21.516 53.544 21.6 ;
    END
  END tx_flit[313]
  PIN tx_flit[314]
    DIRECTION OUTPUT ;
    USE SIGNAL ;
    PORT
      LAYER M5 ;
        RECT  53.616 21.516 53.64 21.6 ;
    END
  END tx_flit[314]
  PIN tx_flit[315]
    DIRECTION OUTPUT ;
    USE SIGNAL ;
    PORT
      LAYER M5 ;
        RECT  53.712 21.516 53.736 21.6 ;
    END
  END tx_flit[315]
  PIN tx_flit[316]
    DIRECTION OUTPUT ;
    USE SIGNAL ;
    PORT
      LAYER M5 ;
        RECT  53.808 21.516 53.832 21.6 ;
    END
  END tx_flit[316]
  PIN tx_flit[317]
    DIRECTION OUTPUT ;
    USE SIGNAL ;
    PORT
      LAYER M5 ;
        RECT  53.904 21.516 53.928 21.6 ;
    END
  END tx_flit[317]
  PIN tx_flit[318]
    DIRECTION OUTPUT ;
    USE SIGNAL ;
    PORT
      LAYER M5 ;
        RECT  54 21.516 54.024 21.6 ;
    END
  END tx_flit[318]
  PIN tx_flit[319]
    DIRECTION OUTPUT ;
    USE SIGNAL ;
    PORT
      LAYER M5 ;
        RECT  54.096 21.516 54.12 21.6 ;
    END
  END tx_flit[319]
  PIN tx_flit[31]
    DIRECTION OUTPUT ;
    USE SIGNAL ;
    PORT
      LAYER M5 ;
        RECT  31.824 21.516 31.848 21.6 ;
    END
  END tx_flit[31]
  PIN tx_flit[320]
    DIRECTION OUTPUT ;
    USE SIGNAL ;
    PORT
      LAYER M5 ;
        RECT  60.336 21.516 60.36 21.6 ;
    END
  END tx_flit[320]
  PIN tx_flit[321]
    DIRECTION OUTPUT ;
    USE SIGNAL ;
    PORT
      LAYER M5 ;
        RECT  60.432 21.516 60.456 21.6 ;
    END
  END tx_flit[321]
  PIN tx_flit[322]
    DIRECTION OUTPUT ;
    USE SIGNAL ;
    PORT
      LAYER M5 ;
        RECT  60.528 21.516 60.552 21.6 ;
    END
  END tx_flit[322]
  PIN tx_flit[323]
    DIRECTION OUTPUT ;
    USE SIGNAL ;
    PORT
      LAYER M5 ;
        RECT  60.624 21.516 60.648 21.6 ;
    END
  END tx_flit[323]
  PIN tx_flit[324]
    DIRECTION OUTPUT ;
    USE SIGNAL ;
    PORT
      LAYER M5 ;
        RECT  60.72 21.516 60.744 21.6 ;
    END
  END tx_flit[324]
  PIN tx_flit[325]
    DIRECTION OUTPUT ;
    USE SIGNAL ;
    PORT
      LAYER M5 ;
        RECT  60.816 21.516 60.84 21.6 ;
    END
  END tx_flit[325]
  PIN tx_flit[326]
    DIRECTION OUTPUT ;
    USE SIGNAL ;
    PORT
      LAYER M5 ;
        RECT  60.912 21.516 60.936 21.6 ;
    END
  END tx_flit[326]
  PIN tx_flit[327]
    DIRECTION OUTPUT ;
    USE SIGNAL ;
    PORT
      LAYER M5 ;
        RECT  61.008 21.516 61.032 21.6 ;
    END
  END tx_flit[327]
  PIN tx_flit[328]
    DIRECTION OUTPUT ;
    USE SIGNAL ;
    PORT
      LAYER M5 ;
        RECT  61.104 21.516 61.128 21.6 ;
    END
  END tx_flit[328]
  PIN tx_flit[329]
    DIRECTION OUTPUT ;
    USE SIGNAL ;
    PORT
      LAYER M5 ;
        RECT  61.2 21.516 61.224 21.6 ;
    END
  END tx_flit[329]
  PIN tx_flit[32]
    DIRECTION OUTPUT ;
    USE SIGNAL ;
    PORT
      LAYER M5 ;
        RECT  31.92 21.516 31.944 21.6 ;
    END
  END tx_flit[32]
  PIN tx_flit[330]
    DIRECTION OUTPUT ;
    USE SIGNAL ;
    PORT
      LAYER M5 ;
        RECT  61.296 21.516 61.32 21.6 ;
    END
  END tx_flit[330]
  PIN tx_flit[331]
    DIRECTION OUTPUT ;
    USE SIGNAL ;
    PORT
      LAYER M5 ;
        RECT  61.392 21.516 61.416 21.6 ;
    END
  END tx_flit[331]
  PIN tx_flit[332]
    DIRECTION OUTPUT ;
    USE SIGNAL ;
    PORT
      LAYER M5 ;
        RECT  61.488 21.516 61.512 21.6 ;
    END
  END tx_flit[332]
  PIN tx_flit[333]
    DIRECTION OUTPUT ;
    USE SIGNAL ;
    PORT
      LAYER M5 ;
        RECT  61.584 21.516 61.608 21.6 ;
    END
  END tx_flit[333]
  PIN tx_flit[334]
    DIRECTION OUTPUT ;
    USE SIGNAL ;
    PORT
      LAYER M5 ;
        RECT  61.68 21.516 61.704 21.6 ;
    END
  END tx_flit[334]
  PIN tx_flit[335]
    DIRECTION OUTPUT ;
    USE SIGNAL ;
    PORT
      LAYER M5 ;
        RECT  61.776 21.516 61.8 21.6 ;
    END
  END tx_flit[335]
  PIN tx_flit[336]
    DIRECTION OUTPUT ;
    USE SIGNAL ;
    PORT
      LAYER M5 ;
        RECT  61.872 21.516 61.896 21.6 ;
    END
  END tx_flit[336]
  PIN tx_flit[337]
    DIRECTION OUTPUT ;
    USE SIGNAL ;
    PORT
      LAYER M5 ;
        RECT  61.968 21.516 61.992 21.6 ;
    END
  END tx_flit[337]
  PIN tx_flit[338]
    DIRECTION OUTPUT ;
    USE SIGNAL ;
    PORT
      LAYER M5 ;
        RECT  62.064 21.516 62.088 21.6 ;
    END
  END tx_flit[338]
  PIN tx_flit[339]
    DIRECTION OUTPUT ;
    USE SIGNAL ;
    PORT
      LAYER M5 ;
        RECT  62.16 21.516 62.184 21.6 ;
    END
  END tx_flit[339]
  PIN tx_flit[33]
    DIRECTION OUTPUT ;
    USE SIGNAL ;
    PORT
      LAYER M5 ;
        RECT  32.016 21.516 32.04 21.6 ;
    END
  END tx_flit[33]
  PIN tx_flit[340]
    DIRECTION OUTPUT ;
    USE SIGNAL ;
    PORT
      LAYER M5 ;
        RECT  62.256 21.516 62.28 21.6 ;
    END
  END tx_flit[340]
  PIN tx_flit[341]
    DIRECTION OUTPUT ;
    USE SIGNAL ;
    PORT
      LAYER M5 ;
        RECT  62.352 21.516 62.376 21.6 ;
    END
  END tx_flit[341]
  PIN tx_flit[342]
    DIRECTION OUTPUT ;
    USE SIGNAL ;
    PORT
      LAYER M5 ;
        RECT  62.448 21.516 62.472 21.6 ;
    END
  END tx_flit[342]
  PIN tx_flit[343]
    DIRECTION OUTPUT ;
    USE SIGNAL ;
    PORT
      LAYER M5 ;
        RECT  62.544 21.516 62.568 21.6 ;
    END
  END tx_flit[343]
  PIN tx_flit[344]
    DIRECTION OUTPUT ;
    USE SIGNAL ;
    PORT
      LAYER M5 ;
        RECT  62.64 21.516 62.664 21.6 ;
    END
  END tx_flit[344]
  PIN tx_flit[345]
    DIRECTION OUTPUT ;
    USE SIGNAL ;
    PORT
      LAYER M5 ;
        RECT  62.736 21.516 62.76 21.6 ;
    END
  END tx_flit[345]
  PIN tx_flit[346]
    DIRECTION OUTPUT ;
    USE SIGNAL ;
    PORT
      LAYER M5 ;
        RECT  62.832 21.516 62.856 21.6 ;
    END
  END tx_flit[346]
  PIN tx_flit[347]
    DIRECTION OUTPUT ;
    USE SIGNAL ;
    PORT
      LAYER M5 ;
        RECT  62.928 21.516 62.952 21.6 ;
    END
  END tx_flit[347]
  PIN tx_flit[348]
    DIRECTION OUTPUT ;
    USE SIGNAL ;
    PORT
      LAYER M5 ;
        RECT  63.024 21.516 63.048 21.6 ;
    END
  END tx_flit[348]
  PIN tx_flit[349]
    DIRECTION OUTPUT ;
    USE SIGNAL ;
    PORT
      LAYER M5 ;
        RECT  63.12 21.516 63.144 21.6 ;
    END
  END tx_flit[349]
  PIN tx_flit[34]
    DIRECTION OUTPUT ;
    USE SIGNAL ;
    PORT
      LAYER M5 ;
        RECT  32.112 21.516 32.136 21.6 ;
    END
  END tx_flit[34]
  PIN tx_flit[350]
    DIRECTION OUTPUT ;
    USE SIGNAL ;
    PORT
      LAYER M5 ;
        RECT  63.216 21.516 63.24 21.6 ;
    END
  END tx_flit[350]
  PIN tx_flit[351]
    DIRECTION OUTPUT ;
    USE SIGNAL ;
    PORT
      LAYER M5 ;
        RECT  63.312 21.516 63.336 21.6 ;
    END
  END tx_flit[351]
  PIN tx_flit[352]
    DIRECTION OUTPUT ;
    USE SIGNAL ;
    PORT
      LAYER M5 ;
        RECT  63.408 21.516 63.432 21.6 ;
    END
  END tx_flit[352]
  PIN tx_flit[353]
    DIRECTION OUTPUT ;
    USE SIGNAL ;
    PORT
      LAYER M5 ;
        RECT  63.504 21.516 63.528 21.6 ;
    END
  END tx_flit[353]
  PIN tx_flit[354]
    DIRECTION OUTPUT ;
    USE SIGNAL ;
    PORT
      LAYER M5 ;
        RECT  63.6 21.516 63.624 21.6 ;
    END
  END tx_flit[354]
  PIN tx_flit[355]
    DIRECTION OUTPUT ;
    USE SIGNAL ;
    PORT
      LAYER M5 ;
        RECT  63.696 21.516 63.72 21.6 ;
    END
  END tx_flit[355]
  PIN tx_flit[356]
    DIRECTION OUTPUT ;
    USE SIGNAL ;
    PORT
      LAYER M5 ;
        RECT  63.792 21.516 63.816 21.6 ;
    END
  END tx_flit[356]
  PIN tx_flit[357]
    DIRECTION OUTPUT ;
    USE SIGNAL ;
    PORT
      LAYER M5 ;
        RECT  63.888 21.516 63.912 21.6 ;
    END
  END tx_flit[357]
  PIN tx_flit[358]
    DIRECTION OUTPUT ;
    USE SIGNAL ;
    PORT
      LAYER M5 ;
        RECT  63.984 21.516 64.008 21.6 ;
    END
  END tx_flit[358]
  PIN tx_flit[359]
    DIRECTION OUTPUT ;
    USE SIGNAL ;
    PORT
      LAYER M5 ;
        RECT  64.08 21.516 64.104 21.6 ;
    END
  END tx_flit[359]
  PIN tx_flit[35]
    DIRECTION OUTPUT ;
    USE SIGNAL ;
    PORT
      LAYER M5 ;
        RECT  32.208 21.516 32.232 21.6 ;
    END
  END tx_flit[35]
  PIN tx_flit[360]
    DIRECTION OUTPUT ;
    USE SIGNAL ;
    PORT
      LAYER M5 ;
        RECT  64.176 21.516 64.2 21.6 ;
    END
  END tx_flit[360]
  PIN tx_flit[361]
    DIRECTION OUTPUT ;
    USE SIGNAL ;
    PORT
      LAYER M5 ;
        RECT  64.272 21.516 64.296 21.6 ;
    END
  END tx_flit[361]
  PIN tx_flit[362]
    DIRECTION OUTPUT ;
    USE SIGNAL ;
    PORT
      LAYER M5 ;
        RECT  64.368 21.516 64.392 21.6 ;
    END
  END tx_flit[362]
  PIN tx_flit[363]
    DIRECTION OUTPUT ;
    USE SIGNAL ;
    PORT
      LAYER M5 ;
        RECT  64.464 21.516 64.488 21.6 ;
    END
  END tx_flit[363]
  PIN tx_flit[364]
    DIRECTION OUTPUT ;
    USE SIGNAL ;
    PORT
      LAYER M5 ;
        RECT  64.56 21.516 64.584 21.6 ;
    END
  END tx_flit[364]
  PIN tx_flit[365]
    DIRECTION OUTPUT ;
    USE SIGNAL ;
    PORT
      LAYER M5 ;
        RECT  64.656 21.516 64.68 21.6 ;
    END
  END tx_flit[365]
  PIN tx_flit[366]
    DIRECTION OUTPUT ;
    USE SIGNAL ;
    PORT
      LAYER M5 ;
        RECT  64.752 21.516 64.776 21.6 ;
    END
  END tx_flit[366]
  PIN tx_flit[367]
    DIRECTION OUTPUT ;
    USE SIGNAL ;
    PORT
      LAYER M5 ;
        RECT  64.848 21.516 64.872 21.6 ;
    END
  END tx_flit[367]
  PIN tx_flit[368]
    DIRECTION OUTPUT ;
    USE SIGNAL ;
    PORT
      LAYER M5 ;
        RECT  64.944 21.516 64.968 21.6 ;
    END
  END tx_flit[368]
  PIN tx_flit[369]
    DIRECTION OUTPUT ;
    USE SIGNAL ;
    PORT
      LAYER M5 ;
        RECT  65.04 21.516 65.064 21.6 ;
    END
  END tx_flit[369]
  PIN tx_flit[36]
    DIRECTION OUTPUT ;
    USE SIGNAL ;
    PORT
      LAYER M5 ;
        RECT  32.304 21.516 32.328 21.6 ;
    END
  END tx_flit[36]
  PIN tx_flit[370]
    DIRECTION OUTPUT ;
    USE SIGNAL ;
    PORT
      LAYER M5 ;
        RECT  65.136 21.516 65.16 21.6 ;
    END
  END tx_flit[370]
  PIN tx_flit[371]
    DIRECTION OUTPUT ;
    USE SIGNAL ;
    PORT
      LAYER M5 ;
        RECT  65.232 21.516 65.256 21.6 ;
    END
  END tx_flit[371]
  PIN tx_flit[372]
    DIRECTION OUTPUT ;
    USE SIGNAL ;
    PORT
      LAYER M5 ;
        RECT  65.328 21.516 65.352 21.6 ;
    END
  END tx_flit[372]
  PIN tx_flit[373]
    DIRECTION OUTPUT ;
    USE SIGNAL ;
    PORT
      LAYER M5 ;
        RECT  65.424 21.516 65.448 21.6 ;
    END
  END tx_flit[373]
  PIN tx_flit[374]
    DIRECTION OUTPUT ;
    USE SIGNAL ;
    PORT
      LAYER M5 ;
        RECT  65.52 21.516 65.544 21.6 ;
    END
  END tx_flit[374]
  PIN tx_flit[375]
    DIRECTION OUTPUT ;
    USE SIGNAL ;
    PORT
      LAYER M5 ;
        RECT  65.616 21.516 65.64 21.6 ;
    END
  END tx_flit[375]
  PIN tx_flit[376]
    DIRECTION OUTPUT ;
    USE SIGNAL ;
    PORT
      LAYER M5 ;
        RECT  65.712 21.516 65.736 21.6 ;
    END
  END tx_flit[376]
  PIN tx_flit[377]
    DIRECTION OUTPUT ;
    USE SIGNAL ;
    PORT
      LAYER M5 ;
        RECT  65.808 21.516 65.832 21.6 ;
    END
  END tx_flit[377]
  PIN tx_flit[378]
    DIRECTION OUTPUT ;
    USE SIGNAL ;
    PORT
      LAYER M5 ;
        RECT  65.904 21.516 65.928 21.6 ;
    END
  END tx_flit[378]
  PIN tx_flit[379]
    DIRECTION OUTPUT ;
    USE SIGNAL ;
    PORT
      LAYER M5 ;
        RECT  66 21.516 66.024 21.6 ;
    END
  END tx_flit[379]
  PIN tx_flit[37]
    DIRECTION OUTPUT ;
    USE SIGNAL ;
    PORT
      LAYER M5 ;
        RECT  32.4 21.516 32.424 21.6 ;
    END
  END tx_flit[37]
  PIN tx_flit[380]
    DIRECTION OUTPUT ;
    USE SIGNAL ;
    PORT
      LAYER M5 ;
        RECT  66.096 21.516 66.12 21.6 ;
    END
  END tx_flit[380]
  PIN tx_flit[381]
    DIRECTION OUTPUT ;
    USE SIGNAL ;
    PORT
      LAYER M5 ;
        RECT  66.192 21.516 66.216 21.6 ;
    END
  END tx_flit[381]
  PIN tx_flit[382]
    DIRECTION OUTPUT ;
    USE SIGNAL ;
    PORT
      LAYER M5 ;
        RECT  66.288 21.516 66.312 21.6 ;
    END
  END tx_flit[382]
  PIN tx_flit[383]
    DIRECTION OUTPUT ;
    USE SIGNAL ;
    PORT
      LAYER M5 ;
        RECT  66.384 21.516 66.408 21.6 ;
    END
  END tx_flit[383]
  PIN tx_flit[384]
    DIRECTION OUTPUT ;
    USE SIGNAL ;
    PORT
      LAYER M5 ;
        RECT  15.792 21.516 15.816 21.6 ;
    END
  END tx_flit[384]
  PIN tx_flit[385]
    DIRECTION OUTPUT ;
    USE SIGNAL ;
    PORT
      LAYER M5 ;
        RECT  15.888 21.516 15.912 21.6 ;
    END
  END tx_flit[385]
  PIN tx_flit[386]
    DIRECTION OUTPUT ;
    USE SIGNAL ;
    PORT
      LAYER M5 ;
        RECT  15.984 21.516 16.008 21.6 ;
    END
  END tx_flit[386]
  PIN tx_flit[387]
    DIRECTION OUTPUT ;
    USE SIGNAL ;
    PORT
      LAYER M5 ;
        RECT  16.08 21.516 16.104 21.6 ;
    END
  END tx_flit[387]
  PIN tx_flit[388]
    DIRECTION OUTPUT ;
    USE SIGNAL ;
    PORT
      LAYER M5 ;
        RECT  16.176 21.516 16.2 21.6 ;
    END
  END tx_flit[388]
  PIN tx_flit[389]
    DIRECTION OUTPUT ;
    USE SIGNAL ;
    PORT
      LAYER M5 ;
        RECT  16.272 21.516 16.296 21.6 ;
    END
  END tx_flit[389]
  PIN tx_flit[38]
    DIRECTION OUTPUT ;
    USE SIGNAL ;
    PORT
      LAYER M5 ;
        RECT  32.496 21.516 32.52 21.6 ;
    END
  END tx_flit[38]
  PIN tx_flit[390]
    DIRECTION OUTPUT ;
    USE SIGNAL ;
    PORT
      LAYER M5 ;
        RECT  16.368 21.516 16.392 21.6 ;
    END
  END tx_flit[390]
  PIN tx_flit[391]
    DIRECTION OUTPUT ;
    USE SIGNAL ;
    PORT
      LAYER M5 ;
        RECT  16.464 21.516 16.488 21.6 ;
    END
  END tx_flit[391]
  PIN tx_flit[392]
    DIRECTION OUTPUT ;
    USE SIGNAL ;
    PORT
      LAYER M5 ;
        RECT  16.56 21.516 16.584 21.6 ;
    END
  END tx_flit[392]
  PIN tx_flit[393]
    DIRECTION OUTPUT ;
    USE SIGNAL ;
    PORT
      LAYER M5 ;
        RECT  16.656 21.516 16.68 21.6 ;
    END
  END tx_flit[393]
  PIN tx_flit[394]
    DIRECTION OUTPUT ;
    USE SIGNAL ;
    PORT
      LAYER M5 ;
        RECT  16.752 21.516 16.776 21.6 ;
    END
  END tx_flit[394]
  PIN tx_flit[395]
    DIRECTION OUTPUT ;
    USE SIGNAL ;
    PORT
      LAYER M5 ;
        RECT  16.848 21.516 16.872 21.6 ;
    END
  END tx_flit[395]
  PIN tx_flit[396]
    DIRECTION OUTPUT ;
    USE SIGNAL ;
    PORT
      LAYER M5 ;
        RECT  16.944 21.516 16.968 21.6 ;
    END
  END tx_flit[396]
  PIN tx_flit[397]
    DIRECTION OUTPUT ;
    USE SIGNAL ;
    PORT
      LAYER M5 ;
        RECT  17.04 21.516 17.064 21.6 ;
    END
  END tx_flit[397]
  PIN tx_flit[398]
    DIRECTION OUTPUT ;
    USE SIGNAL ;
    PORT
      LAYER M5 ;
        RECT  17.136 21.516 17.16 21.6 ;
    END
  END tx_flit[398]
  PIN tx_flit[399]
    DIRECTION OUTPUT ;
    USE SIGNAL ;
    PORT
      LAYER M5 ;
        RECT  17.232 21.516 17.256 21.6 ;
    END
  END tx_flit[399]
  PIN tx_flit[39]
    DIRECTION OUTPUT ;
    USE SIGNAL ;
    PORT
      LAYER M5 ;
        RECT  32.592 21.516 32.616 21.6 ;
    END
  END tx_flit[39]
  PIN tx_flit[3]
    DIRECTION OUTPUT ;
    USE SIGNAL ;
    PORT
      LAYER M5 ;
        RECT  29.136 21.516 29.16 21.6 ;
    END
  END tx_flit[3]
  PIN tx_flit[400]
    DIRECTION OUTPUT ;
    USE SIGNAL ;
    PORT
      LAYER M5 ;
        RECT  17.328 21.516 17.352 21.6 ;
    END
  END tx_flit[400]
  PIN tx_flit[401]
    DIRECTION OUTPUT ;
    USE SIGNAL ;
    PORT
      LAYER M5 ;
        RECT  17.424 21.516 17.448 21.6 ;
    END
  END tx_flit[401]
  PIN tx_flit[402]
    DIRECTION OUTPUT ;
    USE SIGNAL ;
    PORT
      LAYER M5 ;
        RECT  17.52 21.516 17.544 21.6 ;
    END
  END tx_flit[402]
  PIN tx_flit[403]
    DIRECTION OUTPUT ;
    USE SIGNAL ;
    PORT
      LAYER M5 ;
        RECT  17.616 21.516 17.64 21.6 ;
    END
  END tx_flit[403]
  PIN tx_flit[404]
    DIRECTION OUTPUT ;
    USE SIGNAL ;
    PORT
      LAYER M5 ;
        RECT  17.712 21.516 17.736 21.6 ;
    END
  END tx_flit[404]
  PIN tx_flit[405]
    DIRECTION OUTPUT ;
    USE SIGNAL ;
    PORT
      LAYER M5 ;
        RECT  17.808 21.516 17.832 21.6 ;
    END
  END tx_flit[405]
  PIN tx_flit[406]
    DIRECTION OUTPUT ;
    USE SIGNAL ;
    PORT
      LAYER M5 ;
        RECT  17.904 21.516 17.928 21.6 ;
    END
  END tx_flit[406]
  PIN tx_flit[407]
    DIRECTION OUTPUT ;
    USE SIGNAL ;
    PORT
      LAYER M5 ;
        RECT  18 21.516 18.024 21.6 ;
    END
  END tx_flit[407]
  PIN tx_flit[408]
    DIRECTION OUTPUT ;
    USE SIGNAL ;
    PORT
      LAYER M5 ;
        RECT  18.096 21.516 18.12 21.6 ;
    END
  END tx_flit[408]
  PIN tx_flit[409]
    DIRECTION OUTPUT ;
    USE SIGNAL ;
    PORT
      LAYER M5 ;
        RECT  18.192 21.516 18.216 21.6 ;
    END
  END tx_flit[409]
  PIN tx_flit[40]
    DIRECTION OUTPUT ;
    USE SIGNAL ;
    PORT
      LAYER M5 ;
        RECT  32.688 21.516 32.712 21.6 ;
    END
  END tx_flit[40]
  PIN tx_flit[410]
    DIRECTION OUTPUT ;
    USE SIGNAL ;
    PORT
      LAYER M5 ;
        RECT  18.288 21.516 18.312 21.6 ;
    END
  END tx_flit[410]
  PIN tx_flit[411]
    DIRECTION OUTPUT ;
    USE SIGNAL ;
    PORT
      LAYER M5 ;
        RECT  18.384 21.516 18.408 21.6 ;
    END
  END tx_flit[411]
  PIN tx_flit[412]
    DIRECTION OUTPUT ;
    USE SIGNAL ;
    PORT
      LAYER M5 ;
        RECT  18.48 21.516 18.504 21.6 ;
    END
  END tx_flit[412]
  PIN tx_flit[413]
    DIRECTION OUTPUT ;
    USE SIGNAL ;
    PORT
      LAYER M5 ;
        RECT  18.576 21.516 18.6 21.6 ;
    END
  END tx_flit[413]
  PIN tx_flit[414]
    DIRECTION OUTPUT ;
    USE SIGNAL ;
    PORT
      LAYER M5 ;
        RECT  18.672 21.516 18.696 21.6 ;
    END
  END tx_flit[414]
  PIN tx_flit[415]
    DIRECTION OUTPUT ;
    USE SIGNAL ;
    PORT
      LAYER M5 ;
        RECT  18.768 21.516 18.792 21.6 ;
    END
  END tx_flit[415]
  PIN tx_flit[416]
    DIRECTION OUTPUT ;
    USE SIGNAL ;
    PORT
      LAYER M5 ;
        RECT  21.936 21.516 21.96 21.6 ;
    END
  END tx_flit[416]
  PIN tx_flit[417]
    DIRECTION OUTPUT ;
    USE SIGNAL ;
    PORT
      LAYER M5 ;
        RECT  22.032 21.516 22.056 21.6 ;
    END
  END tx_flit[417]
  PIN tx_flit[418]
    DIRECTION OUTPUT ;
    USE SIGNAL ;
    PORT
      LAYER M5 ;
        RECT  22.128 21.516 22.152 21.6 ;
    END
  END tx_flit[418]
  PIN tx_flit[419]
    DIRECTION OUTPUT ;
    USE SIGNAL ;
    PORT
      LAYER M5 ;
        RECT  22.224 21.516 22.248 21.6 ;
    END
  END tx_flit[419]
  PIN tx_flit[41]
    DIRECTION OUTPUT ;
    USE SIGNAL ;
    PORT
      LAYER M5 ;
        RECT  32.784 21.516 32.808 21.6 ;
    END
  END tx_flit[41]
  PIN tx_flit[420]
    DIRECTION OUTPUT ;
    USE SIGNAL ;
    PORT
      LAYER M5 ;
        RECT  22.32 21.516 22.344 21.6 ;
    END
  END tx_flit[420]
  PIN tx_flit[421]
    DIRECTION OUTPUT ;
    USE SIGNAL ;
    PORT
      LAYER M5 ;
        RECT  22.416 21.516 22.44 21.6 ;
    END
  END tx_flit[421]
  PIN tx_flit[422]
    DIRECTION OUTPUT ;
    USE SIGNAL ;
    PORT
      LAYER M5 ;
        RECT  22.512 21.516 22.536 21.6 ;
    END
  END tx_flit[422]
  PIN tx_flit[423]
    DIRECTION OUTPUT ;
    USE SIGNAL ;
    PORT
      LAYER M5 ;
        RECT  22.608 21.516 22.632 21.6 ;
    END
  END tx_flit[423]
  PIN tx_flit[424]
    DIRECTION OUTPUT ;
    USE SIGNAL ;
    PORT
      LAYER M5 ;
        RECT  22.704 21.516 22.728 21.6 ;
    END
  END tx_flit[424]
  PIN tx_flit[425]
    DIRECTION OUTPUT ;
    USE SIGNAL ;
    PORT
      LAYER M5 ;
        RECT  22.8 21.516 22.824 21.6 ;
    END
  END tx_flit[425]
  PIN tx_flit[426]
    DIRECTION OUTPUT ;
    USE SIGNAL ;
    PORT
      LAYER M5 ;
        RECT  22.896 21.516 22.92 21.6 ;
    END
  END tx_flit[426]
  PIN tx_flit[427]
    DIRECTION OUTPUT ;
    USE SIGNAL ;
    PORT
      LAYER M5 ;
        RECT  22.992 21.516 23.016 21.6 ;
    END
  END tx_flit[427]
  PIN tx_flit[428]
    DIRECTION OUTPUT ;
    USE SIGNAL ;
    PORT
      LAYER M5 ;
        RECT  23.088 21.516 23.112 21.6 ;
    END
  END tx_flit[428]
  PIN tx_flit[429]
    DIRECTION OUTPUT ;
    USE SIGNAL ;
    PORT
      LAYER M5 ;
        RECT  23.184 21.516 23.208 21.6 ;
    END
  END tx_flit[429]
  PIN tx_flit[42]
    DIRECTION OUTPUT ;
    USE SIGNAL ;
    PORT
      LAYER M5 ;
        RECT  32.88 21.516 32.904 21.6 ;
    END
  END tx_flit[42]
  PIN tx_flit[430]
    DIRECTION OUTPUT ;
    USE SIGNAL ;
    PORT
      LAYER M5 ;
        RECT  23.28 21.516 23.304 21.6 ;
    END
  END tx_flit[430]
  PIN tx_flit[431]
    DIRECTION OUTPUT ;
    USE SIGNAL ;
    PORT
      LAYER M5 ;
        RECT  23.376 21.516 23.4 21.6 ;
    END
  END tx_flit[431]
  PIN tx_flit[432]
    DIRECTION OUTPUT ;
    USE SIGNAL ;
    PORT
      LAYER M5 ;
        RECT  23.472 21.516 23.496 21.6 ;
    END
  END tx_flit[432]
  PIN tx_flit[433]
    DIRECTION OUTPUT ;
    USE SIGNAL ;
    PORT
      LAYER M5 ;
        RECT  23.568 21.516 23.592 21.6 ;
    END
  END tx_flit[433]
  PIN tx_flit[434]
    DIRECTION OUTPUT ;
    USE SIGNAL ;
    PORT
      LAYER M5 ;
        RECT  23.664 21.516 23.688 21.6 ;
    END
  END tx_flit[434]
  PIN tx_flit[435]
    DIRECTION OUTPUT ;
    USE SIGNAL ;
    PORT
      LAYER M5 ;
        RECT  23.76 21.516 23.784 21.6 ;
    END
  END tx_flit[435]
  PIN tx_flit[436]
    DIRECTION OUTPUT ;
    USE SIGNAL ;
    PORT
      LAYER M5 ;
        RECT  23.856 21.516 23.88 21.6 ;
    END
  END tx_flit[436]
  PIN tx_flit[437]
    DIRECTION OUTPUT ;
    USE SIGNAL ;
    PORT
      LAYER M5 ;
        RECT  23.952 21.516 23.976 21.6 ;
    END
  END tx_flit[437]
  PIN tx_flit[438]
    DIRECTION OUTPUT ;
    USE SIGNAL ;
    PORT
      LAYER M5 ;
        RECT  24.048 21.516 24.072 21.6 ;
    END
  END tx_flit[438]
  PIN tx_flit[439]
    DIRECTION OUTPUT ;
    USE SIGNAL ;
    PORT
      LAYER M5 ;
        RECT  24.144 21.516 24.168 21.6 ;
    END
  END tx_flit[439]
  PIN tx_flit[43]
    DIRECTION OUTPUT ;
    USE SIGNAL ;
    PORT
      LAYER M5 ;
        RECT  32.976 21.516 33 21.6 ;
    END
  END tx_flit[43]
  PIN tx_flit[440]
    DIRECTION OUTPUT ;
    USE SIGNAL ;
    PORT
      LAYER M5 ;
        RECT  24.24 21.516 24.264 21.6 ;
    END
  END tx_flit[440]
  PIN tx_flit[441]
    DIRECTION OUTPUT ;
    USE SIGNAL ;
    PORT
      LAYER M5 ;
        RECT  24.336 21.516 24.36 21.6 ;
    END
  END tx_flit[441]
  PIN tx_flit[442]
    DIRECTION OUTPUT ;
    USE SIGNAL ;
    PORT
      LAYER M5 ;
        RECT  24.432 21.516 24.456 21.6 ;
    END
  END tx_flit[442]
  PIN tx_flit[443]
    DIRECTION OUTPUT ;
    USE SIGNAL ;
    PORT
      LAYER M5 ;
        RECT  24.528 21.516 24.552 21.6 ;
    END
  END tx_flit[443]
  PIN tx_flit[444]
    DIRECTION OUTPUT ;
    USE SIGNAL ;
    PORT
      LAYER M5 ;
        RECT  24.624 21.516 24.648 21.6 ;
    END
  END tx_flit[444]
  PIN tx_flit[445]
    DIRECTION OUTPUT ;
    USE SIGNAL ;
    PORT
      LAYER M5 ;
        RECT  24.72 21.516 24.744 21.6 ;
    END
  END tx_flit[445]
  PIN tx_flit[446]
    DIRECTION OUTPUT ;
    USE SIGNAL ;
    PORT
      LAYER M5 ;
        RECT  24.816 21.516 24.84 21.6 ;
    END
  END tx_flit[446]
  PIN tx_flit[447]
    DIRECTION OUTPUT ;
    USE SIGNAL ;
    PORT
      LAYER M5 ;
        RECT  24.912 21.516 24.936 21.6 ;
    END
  END tx_flit[447]
  PIN tx_flit[448]
    DIRECTION OUTPUT ;
    USE SIGNAL ;
    PORT
      LAYER M5 ;
        RECT  12.72 21.516 12.744 21.6 ;
    END
  END tx_flit[448]
  PIN tx_flit[449]
    DIRECTION OUTPUT ;
    USE SIGNAL ;
    PORT
      LAYER M5 ;
        RECT  12.816 21.516 12.84 21.6 ;
    END
  END tx_flit[449]
  PIN tx_flit[44]
    DIRECTION OUTPUT ;
    USE SIGNAL ;
    PORT
      LAYER M5 ;
        RECT  33.072 21.516 33.096 21.6 ;
    END
  END tx_flit[44]
  PIN tx_flit[450]
    DIRECTION OUTPUT ;
    USE SIGNAL ;
    PORT
      LAYER M5 ;
        RECT  12.912 21.516 12.936 21.6 ;
    END
  END tx_flit[450]
  PIN tx_flit[451]
    DIRECTION OUTPUT ;
    USE SIGNAL ;
    PORT
      LAYER M5 ;
        RECT  13.008 21.516 13.032 21.6 ;
    END
  END tx_flit[451]
  PIN tx_flit[452]
    DIRECTION OUTPUT ;
    USE SIGNAL ;
    PORT
      LAYER M5 ;
        RECT  13.104 21.516 13.128 21.6 ;
    END
  END tx_flit[452]
  PIN tx_flit[453]
    DIRECTION OUTPUT ;
    USE SIGNAL ;
    PORT
      LAYER M5 ;
        RECT  13.2 21.516 13.224 21.6 ;
    END
  END tx_flit[453]
  PIN tx_flit[454]
    DIRECTION OUTPUT ;
    USE SIGNAL ;
    PORT
      LAYER M5 ;
        RECT  13.296 21.516 13.32 21.6 ;
    END
  END tx_flit[454]
  PIN tx_flit[455]
    DIRECTION OUTPUT ;
    USE SIGNAL ;
    PORT
      LAYER M5 ;
        RECT  13.392 21.516 13.416 21.6 ;
    END
  END tx_flit[455]
  PIN tx_flit[456]
    DIRECTION OUTPUT ;
    USE SIGNAL ;
    PORT
      LAYER M5 ;
        RECT  13.488 21.516 13.512 21.6 ;
    END
  END tx_flit[456]
  PIN tx_flit[457]
    DIRECTION OUTPUT ;
    USE SIGNAL ;
    PORT
      LAYER M5 ;
        RECT  13.584 21.516 13.608 21.6 ;
    END
  END tx_flit[457]
  PIN tx_flit[458]
    DIRECTION OUTPUT ;
    USE SIGNAL ;
    PORT
      LAYER M5 ;
        RECT  13.68 21.516 13.704 21.6 ;
    END
  END tx_flit[458]
  PIN tx_flit[459]
    DIRECTION OUTPUT ;
    USE SIGNAL ;
    PORT
      LAYER M5 ;
        RECT  13.776 21.516 13.8 21.6 ;
    END
  END tx_flit[459]
  PIN tx_flit[45]
    DIRECTION OUTPUT ;
    USE SIGNAL ;
    PORT
      LAYER M5 ;
        RECT  33.168 21.516 33.192 21.6 ;
    END
  END tx_flit[45]
  PIN tx_flit[460]
    DIRECTION OUTPUT ;
    USE SIGNAL ;
    PORT
      LAYER M5 ;
        RECT  13.872 21.516 13.896 21.6 ;
    END
  END tx_flit[460]
  PIN tx_flit[461]
    DIRECTION OUTPUT ;
    USE SIGNAL ;
    PORT
      LAYER M5 ;
        RECT  13.968 21.516 13.992 21.6 ;
    END
  END tx_flit[461]
  PIN tx_flit[462]
    DIRECTION OUTPUT ;
    USE SIGNAL ;
    PORT
      LAYER M5 ;
        RECT  14.064 21.516 14.088 21.6 ;
    END
  END tx_flit[462]
  PIN tx_flit[463]
    DIRECTION OUTPUT ;
    USE SIGNAL ;
    PORT
      LAYER M5 ;
        RECT  14.16 21.516 14.184 21.6 ;
    END
  END tx_flit[463]
  PIN tx_flit[464]
    DIRECTION OUTPUT ;
    USE SIGNAL ;
    PORT
      LAYER M5 ;
        RECT  14.256 21.516 14.28 21.6 ;
    END
  END tx_flit[464]
  PIN tx_flit[465]
    DIRECTION OUTPUT ;
    USE SIGNAL ;
    PORT
      LAYER M5 ;
        RECT  14.352 21.516 14.376 21.6 ;
    END
  END tx_flit[465]
  PIN tx_flit[466]
    DIRECTION OUTPUT ;
    USE SIGNAL ;
    PORT
      LAYER M5 ;
        RECT  14.448 21.516 14.472 21.6 ;
    END
  END tx_flit[466]
  PIN tx_flit[467]
    DIRECTION OUTPUT ;
    USE SIGNAL ;
    PORT
      LAYER M5 ;
        RECT  14.544 21.516 14.568 21.6 ;
    END
  END tx_flit[467]
  PIN tx_flit[468]
    DIRECTION OUTPUT ;
    USE SIGNAL ;
    PORT
      LAYER M5 ;
        RECT  14.64 21.516 14.664 21.6 ;
    END
  END tx_flit[468]
  PIN tx_flit[469]
    DIRECTION OUTPUT ;
    USE SIGNAL ;
    PORT
      LAYER M5 ;
        RECT  14.736 21.516 14.76 21.6 ;
    END
  END tx_flit[469]
  PIN tx_flit[46]
    DIRECTION OUTPUT ;
    USE SIGNAL ;
    PORT
      LAYER M5 ;
        RECT  33.264 21.516 33.288 21.6 ;
    END
  END tx_flit[46]
  PIN tx_flit[470]
    DIRECTION OUTPUT ;
    USE SIGNAL ;
    PORT
      LAYER M5 ;
        RECT  14.832 21.516 14.856 21.6 ;
    END
  END tx_flit[470]
  PIN tx_flit[471]
    DIRECTION OUTPUT ;
    USE SIGNAL ;
    PORT
      LAYER M5 ;
        RECT  14.928 21.516 14.952 21.6 ;
    END
  END tx_flit[471]
  PIN tx_flit[472]
    DIRECTION OUTPUT ;
    USE SIGNAL ;
    PORT
      LAYER M5 ;
        RECT  15.024 21.516 15.048 21.6 ;
    END
  END tx_flit[472]
  PIN tx_flit[473]
    DIRECTION OUTPUT ;
    USE SIGNAL ;
    PORT
      LAYER M5 ;
        RECT  15.12 21.516 15.144 21.6 ;
    END
  END tx_flit[473]
  PIN tx_flit[474]
    DIRECTION OUTPUT ;
    USE SIGNAL ;
    PORT
      LAYER M5 ;
        RECT  15.216 21.516 15.24 21.6 ;
    END
  END tx_flit[474]
  PIN tx_flit[475]
    DIRECTION OUTPUT ;
    USE SIGNAL ;
    PORT
      LAYER M5 ;
        RECT  15.312 21.516 15.336 21.6 ;
    END
  END tx_flit[475]
  PIN tx_flit[476]
    DIRECTION OUTPUT ;
    USE SIGNAL ;
    PORT
      LAYER M5 ;
        RECT  15.408 21.516 15.432 21.6 ;
    END
  END tx_flit[476]
  PIN tx_flit[477]
    DIRECTION OUTPUT ;
    USE SIGNAL ;
    PORT
      LAYER M5 ;
        RECT  15.504 21.516 15.528 21.6 ;
    END
  END tx_flit[477]
  PIN tx_flit[478]
    DIRECTION OUTPUT ;
    USE SIGNAL ;
    PORT
      LAYER M5 ;
        RECT  15.6 21.516 15.624 21.6 ;
    END
  END tx_flit[478]
  PIN tx_flit[479]
    DIRECTION OUTPUT ;
    USE SIGNAL ;
    PORT
      LAYER M5 ;
        RECT  15.696 21.516 15.72 21.6 ;
    END
  END tx_flit[479]
  PIN tx_flit[47]
    DIRECTION OUTPUT ;
    USE SIGNAL ;
    PORT
      LAYER M5 ;
        RECT  33.36 21.516 33.384 21.6 ;
    END
  END tx_flit[47]
  PIN tx_flit[480]
    DIRECTION OUTPUT ;
    USE SIGNAL ;
    PORT
      LAYER M5 ;
        RECT  18.864 21.516 18.888 21.6 ;
    END
  END tx_flit[480]
  PIN tx_flit[481]
    DIRECTION OUTPUT ;
    USE SIGNAL ;
    PORT
      LAYER M5 ;
        RECT  18.96 21.516 18.984 21.6 ;
    END
  END tx_flit[481]
  PIN tx_flit[482]
    DIRECTION OUTPUT ;
    USE SIGNAL ;
    PORT
      LAYER M5 ;
        RECT  19.056 21.516 19.08 21.6 ;
    END
  END tx_flit[482]
  PIN tx_flit[483]
    DIRECTION OUTPUT ;
    USE SIGNAL ;
    PORT
      LAYER M5 ;
        RECT  19.152 21.516 19.176 21.6 ;
    END
  END tx_flit[483]
  PIN tx_flit[484]
    DIRECTION OUTPUT ;
    USE SIGNAL ;
    PORT
      LAYER M5 ;
        RECT  19.248 21.516 19.272 21.6 ;
    END
  END tx_flit[484]
  PIN tx_flit[485]
    DIRECTION OUTPUT ;
    USE SIGNAL ;
    PORT
      LAYER M5 ;
        RECT  19.344 21.516 19.368 21.6 ;
    END
  END tx_flit[485]
  PIN tx_flit[486]
    DIRECTION OUTPUT ;
    USE SIGNAL ;
    PORT
      LAYER M5 ;
        RECT  19.44 21.516 19.464 21.6 ;
    END
  END tx_flit[486]
  PIN tx_flit[487]
    DIRECTION OUTPUT ;
    USE SIGNAL ;
    PORT
      LAYER M5 ;
        RECT  19.536 21.516 19.56 21.6 ;
    END
  END tx_flit[487]
  PIN tx_flit[488]
    DIRECTION OUTPUT ;
    USE SIGNAL ;
    PORT
      LAYER M5 ;
        RECT  19.632 21.516 19.656 21.6 ;
    END
  END tx_flit[488]
  PIN tx_flit[489]
    DIRECTION OUTPUT ;
    USE SIGNAL ;
    PORT
      LAYER M5 ;
        RECT  19.728 21.516 19.752 21.6 ;
    END
  END tx_flit[489]
  PIN tx_flit[48]
    DIRECTION OUTPUT ;
    USE SIGNAL ;
    PORT
      LAYER M5 ;
        RECT  33.456 21.516 33.48 21.6 ;
    END
  END tx_flit[48]
  PIN tx_flit[490]
    DIRECTION OUTPUT ;
    USE SIGNAL ;
    PORT
      LAYER M5 ;
        RECT  19.824 21.516 19.848 21.6 ;
    END
  END tx_flit[490]
  PIN tx_flit[491]
    DIRECTION OUTPUT ;
    USE SIGNAL ;
    PORT
      LAYER M5 ;
        RECT  19.92 21.516 19.944 21.6 ;
    END
  END tx_flit[491]
  PIN tx_flit[492]
    DIRECTION OUTPUT ;
    USE SIGNAL ;
    PORT
      LAYER M5 ;
        RECT  20.016 21.516 20.04 21.6 ;
    END
  END tx_flit[492]
  PIN tx_flit[493]
    DIRECTION OUTPUT ;
    USE SIGNAL ;
    PORT
      LAYER M5 ;
        RECT  20.112 21.516 20.136 21.6 ;
    END
  END tx_flit[493]
  PIN tx_flit[494]
    DIRECTION OUTPUT ;
    USE SIGNAL ;
    PORT
      LAYER M5 ;
        RECT  20.208 21.516 20.232 21.6 ;
    END
  END tx_flit[494]
  PIN tx_flit[495]
    DIRECTION OUTPUT ;
    USE SIGNAL ;
    PORT
      LAYER M5 ;
        RECT  20.304 21.516 20.328 21.6 ;
    END
  END tx_flit[495]
  PIN tx_flit[496]
    DIRECTION OUTPUT ;
    USE SIGNAL ;
    PORT
      LAYER M5 ;
        RECT  20.4 21.516 20.424 21.6 ;
    END
  END tx_flit[496]
  PIN tx_flit[497]
    DIRECTION OUTPUT ;
    USE SIGNAL ;
    PORT
      LAYER M5 ;
        RECT  20.496 21.516 20.52 21.6 ;
    END
  END tx_flit[497]
  PIN tx_flit[498]
    DIRECTION OUTPUT ;
    USE SIGNAL ;
    PORT
      LAYER M5 ;
        RECT  20.592 21.516 20.616 21.6 ;
    END
  END tx_flit[498]
  PIN tx_flit[499]
    DIRECTION OUTPUT ;
    USE SIGNAL ;
    PORT
      LAYER M5 ;
        RECT  20.688 21.516 20.712 21.6 ;
    END
  END tx_flit[499]
  PIN tx_flit[49]
    DIRECTION OUTPUT ;
    USE SIGNAL ;
    PORT
      LAYER M5 ;
        RECT  33.552 21.516 33.576 21.6 ;
    END
  END tx_flit[49]
  PIN tx_flit[4]
    DIRECTION OUTPUT ;
    USE SIGNAL ;
    PORT
      LAYER M5 ;
        RECT  29.232 21.516 29.256 21.6 ;
    END
  END tx_flit[4]
  PIN tx_flit[500]
    DIRECTION OUTPUT ;
    USE SIGNAL ;
    PORT
      LAYER M5 ;
        RECT  20.784 21.516 20.808 21.6 ;
    END
  END tx_flit[500]
  PIN tx_flit[501]
    DIRECTION OUTPUT ;
    USE SIGNAL ;
    PORT
      LAYER M5 ;
        RECT  20.88 21.516 20.904 21.6 ;
    END
  END tx_flit[501]
  PIN tx_flit[502]
    DIRECTION OUTPUT ;
    USE SIGNAL ;
    PORT
      LAYER M5 ;
        RECT  20.976 21.516 21 21.6 ;
    END
  END tx_flit[502]
  PIN tx_flit[503]
    DIRECTION OUTPUT ;
    USE SIGNAL ;
    PORT
      LAYER M5 ;
        RECT  21.072 21.516 21.096 21.6 ;
    END
  END tx_flit[503]
  PIN tx_flit[504]
    DIRECTION OUTPUT ;
    USE SIGNAL ;
    PORT
      LAYER M5 ;
        RECT  21.168 21.516 21.192 21.6 ;
    END
  END tx_flit[504]
  PIN tx_flit[505]
    DIRECTION OUTPUT ;
    USE SIGNAL ;
    PORT
      LAYER M5 ;
        RECT  21.264 21.516 21.288 21.6 ;
    END
  END tx_flit[505]
  PIN tx_flit[506]
    DIRECTION OUTPUT ;
    USE SIGNAL ;
    PORT
      LAYER M5 ;
        RECT  21.36 21.516 21.384 21.6 ;
    END
  END tx_flit[506]
  PIN tx_flit[507]
    DIRECTION OUTPUT ;
    USE SIGNAL ;
    PORT
      LAYER M5 ;
        RECT  21.456 21.516 21.48 21.6 ;
    END
  END tx_flit[507]
  PIN tx_flit[508]
    DIRECTION OUTPUT ;
    USE SIGNAL ;
    PORT
      LAYER M5 ;
        RECT  21.552 21.516 21.576 21.6 ;
    END
  END tx_flit[508]
  PIN tx_flit[509]
    DIRECTION OUTPUT ;
    USE SIGNAL ;
    PORT
      LAYER M5 ;
        RECT  21.648 21.516 21.672 21.6 ;
    END
  END tx_flit[509]
  PIN tx_flit[50]
    DIRECTION OUTPUT ;
    USE SIGNAL ;
    PORT
      LAYER M5 ;
        RECT  33.648 21.516 33.672 21.6 ;
    END
  END tx_flit[50]
  PIN tx_flit[510]
    DIRECTION OUTPUT ;
    USE SIGNAL ;
    PORT
      LAYER M5 ;
        RECT  21.744 21.516 21.768 21.6 ;
    END
  END tx_flit[510]
  PIN tx_flit[511]
    DIRECTION OUTPUT ;
    USE SIGNAL ;
    PORT
      LAYER M5 ;
        RECT  21.84 21.516 21.864 21.6 ;
    END
  END tx_flit[511]
  PIN tx_flit[512]
    DIRECTION OUTPUT ;
    USE SIGNAL ;
    PORT
      LAYER M5 ;
        RECT  25.008 21.516 25.032 21.6 ;
    END
  END tx_flit[512]
  PIN tx_flit[513]
    DIRECTION OUTPUT ;
    USE SIGNAL ;
    PORT
      LAYER M5 ;
        RECT  25.104 21.516 25.128 21.6 ;
    END
  END tx_flit[513]
  PIN tx_flit[514]
    DIRECTION OUTPUT ;
    USE SIGNAL ;
    PORT
      LAYER M5 ;
        RECT  25.2 21.516 25.224 21.6 ;
    END
  END tx_flit[514]
  PIN tx_flit[515]
    DIRECTION OUTPUT ;
    USE SIGNAL ;
    PORT
      LAYER M5 ;
        RECT  25.296 21.516 25.32 21.6 ;
    END
  END tx_flit[515]
  PIN tx_flit[516]
    DIRECTION OUTPUT ;
    USE SIGNAL ;
    PORT
      LAYER M5 ;
        RECT  25.392 21.516 25.416 21.6 ;
    END
  END tx_flit[516]
  PIN tx_flit[517]
    DIRECTION OUTPUT ;
    USE SIGNAL ;
    PORT
      LAYER M5 ;
        RECT  25.488 21.516 25.512 21.6 ;
    END
  END tx_flit[517]
  PIN tx_flit[518]
    DIRECTION OUTPUT ;
    USE SIGNAL ;
    PORT
      LAYER M5 ;
        RECT  25.584 21.516 25.608 21.6 ;
    END
  END tx_flit[518]
  PIN tx_flit[519]
    DIRECTION OUTPUT ;
    USE SIGNAL ;
    PORT
      LAYER M5 ;
        RECT  25.68 21.516 25.704 21.6 ;
    END
  END tx_flit[519]
  PIN tx_flit[51]
    DIRECTION OUTPUT ;
    USE SIGNAL ;
    PORT
      LAYER M5 ;
        RECT  33.744 21.516 33.768 21.6 ;
    END
  END tx_flit[51]
  PIN tx_flit[520]
    DIRECTION OUTPUT ;
    USE SIGNAL ;
    PORT
      LAYER M5 ;
        RECT  25.776 21.516 25.8 21.6 ;
    END
  END tx_flit[520]
  PIN tx_flit[521]
    DIRECTION OUTPUT ;
    USE SIGNAL ;
    PORT
      LAYER M5 ;
        RECT  25.872 21.516 25.896 21.6 ;
    END
  END tx_flit[521]
  PIN tx_flit[522]
    DIRECTION OUTPUT ;
    USE SIGNAL ;
    PORT
      LAYER M5 ;
        RECT  25.968 21.516 25.992 21.6 ;
    END
  END tx_flit[522]
  PIN tx_flit[523]
    DIRECTION OUTPUT ;
    USE SIGNAL ;
    PORT
      LAYER M5 ;
        RECT  26.064 21.516 26.088 21.6 ;
    END
  END tx_flit[523]
  PIN tx_flit[524]
    DIRECTION OUTPUT ;
    USE SIGNAL ;
    PORT
      LAYER M5 ;
        RECT  26.16 21.516 26.184 21.6 ;
    END
  END tx_flit[524]
  PIN tx_flit[525]
    DIRECTION OUTPUT ;
    USE SIGNAL ;
    PORT
      LAYER M5 ;
        RECT  26.256 21.516 26.28 21.6 ;
    END
  END tx_flit[525]
  PIN tx_flit[526]
    DIRECTION OUTPUT ;
    USE SIGNAL ;
    PORT
      LAYER M5 ;
        RECT  26.352 21.516 26.376 21.6 ;
    END
  END tx_flit[526]
  PIN tx_flit[527]
    DIRECTION OUTPUT ;
    USE SIGNAL ;
    PORT
      LAYER M5 ;
        RECT  26.448 21.516 26.472 21.6 ;
    END
  END tx_flit[527]
  PIN tx_flit[528]
    DIRECTION OUTPUT ;
    USE SIGNAL ;
    PORT
      LAYER M5 ;
        RECT  26.544 21.516 26.568 21.6 ;
    END
  END tx_flit[528]
  PIN tx_flit[529]
    DIRECTION OUTPUT ;
    USE SIGNAL ;
    PORT
      LAYER M5 ;
        RECT  26.64 21.516 26.664 21.6 ;
    END
  END tx_flit[529]
  PIN tx_flit[52]
    DIRECTION OUTPUT ;
    USE SIGNAL ;
    PORT
      LAYER M5 ;
        RECT  33.84 21.516 33.864 21.6 ;
    END
  END tx_flit[52]
  PIN tx_flit[530]
    DIRECTION OUTPUT ;
    USE SIGNAL ;
    PORT
      LAYER M5 ;
        RECT  26.736 21.516 26.76 21.6 ;
    END
  END tx_flit[530]
  PIN tx_flit[531]
    DIRECTION OUTPUT ;
    USE SIGNAL ;
    PORT
      LAYER M5 ;
        RECT  26.832 21.516 26.856 21.6 ;
    END
  END tx_flit[531]
  PIN tx_flit[532]
    DIRECTION OUTPUT ;
    USE SIGNAL ;
    PORT
      LAYER M5 ;
        RECT  26.928 21.516 26.952 21.6 ;
    END
  END tx_flit[532]
  PIN tx_flit[533]
    DIRECTION OUTPUT ;
    USE SIGNAL ;
    PORT
      LAYER M5 ;
        RECT  27.024 21.516 27.048 21.6 ;
    END
  END tx_flit[533]
  PIN tx_flit[534]
    DIRECTION OUTPUT ;
    USE SIGNAL ;
    PORT
      LAYER M5 ;
        RECT  27.12 21.516 27.144 21.6 ;
    END
  END tx_flit[534]
  PIN tx_flit[535]
    DIRECTION OUTPUT ;
    USE SIGNAL ;
    PORT
      LAYER M5 ;
        RECT  27.216 21.516 27.24 21.6 ;
    END
  END tx_flit[535]
  PIN tx_flit[536]
    DIRECTION OUTPUT ;
    USE SIGNAL ;
    PORT
      LAYER M5 ;
        RECT  27.312 21.516 27.336 21.6 ;
    END
  END tx_flit[536]
  PIN tx_flit[537]
    DIRECTION OUTPUT ;
    USE SIGNAL ;
    PORT
      LAYER M5 ;
        RECT  27.408 21.516 27.432 21.6 ;
    END
  END tx_flit[537]
  PIN tx_flit[538]
    DIRECTION OUTPUT ;
    USE SIGNAL ;
    PORT
      LAYER M5 ;
        RECT  27.504 21.516 27.528 21.6 ;
    END
  END tx_flit[538]
  PIN tx_flit[539]
    DIRECTION OUTPUT ;
    USE SIGNAL ;
    PORT
      LAYER M5 ;
        RECT  27.6 21.516 27.624 21.6 ;
    END
  END tx_flit[539]
  PIN tx_flit[53]
    DIRECTION OUTPUT ;
    USE SIGNAL ;
    PORT
      LAYER M5 ;
        RECT  33.936 21.516 33.96 21.6 ;
    END
  END tx_flit[53]
  PIN tx_flit[540]
    DIRECTION OUTPUT ;
    USE SIGNAL ;
    PORT
      LAYER M5 ;
        RECT  27.696 21.516 27.72 21.6 ;
    END
  END tx_flit[540]
  PIN tx_flit[541]
    DIRECTION OUTPUT ;
    USE SIGNAL ;
    PORT
      LAYER M5 ;
        RECT  27.792 21.516 27.816 21.6 ;
    END
  END tx_flit[541]
  PIN tx_flit[542]
    DIRECTION OUTPUT ;
    USE SIGNAL ;
    PORT
      LAYER M5 ;
        RECT  27.888 21.516 27.912 21.6 ;
    END
  END tx_flit[542]
  PIN tx_flit[543]
    DIRECTION OUTPUT ;
    USE SIGNAL ;
    PORT
      LAYER M5 ;
        RECT  27.984 21.516 28.008 21.6 ;
    END
  END tx_flit[543]
  PIN tx_flit[544]
    DIRECTION OUTPUT ;
    USE SIGNAL ;
    PORT
      LAYER M5 ;
        RECT  28.272 21.516 28.296 21.6 ;
    END
  END tx_flit[544]
  PIN tx_flit[545]
    DIRECTION OUTPUT ;
    USE SIGNAL ;
    PORT
      LAYER M5 ;
        RECT  28.368 21.516 28.392 21.6 ;
    END
  END tx_flit[545]
  PIN tx_flit[546]
    DIRECTION OUTPUT ;
    USE SIGNAL ;
    PORT
      LAYER M5 ;
        RECT  28.464 21.516 28.488 21.6 ;
    END
  END tx_flit[546]
  PIN tx_flit[547]
    DIRECTION OUTPUT ;
    USE SIGNAL ;
    PORT
      LAYER M5 ;
        RECT  28.56 21.516 28.584 21.6 ;
    END
  END tx_flit[547]
  PIN tx_flit[54]
    DIRECTION OUTPUT ;
    USE SIGNAL ;
    PORT
      LAYER M5 ;
        RECT  34.032 21.516 34.056 21.6 ;
    END
  END tx_flit[54]
  PIN tx_flit[55]
    DIRECTION OUTPUT ;
    USE SIGNAL ;
    PORT
      LAYER M5 ;
        RECT  34.128 21.516 34.152 21.6 ;
    END
  END tx_flit[55]
  PIN tx_flit[56]
    DIRECTION OUTPUT ;
    USE SIGNAL ;
    PORT
      LAYER M5 ;
        RECT  34.224 21.516 34.248 21.6 ;
    END
  END tx_flit[56]
  PIN tx_flit[57]
    DIRECTION OUTPUT ;
    USE SIGNAL ;
    PORT
      LAYER M5 ;
        RECT  34.32 21.516 34.344 21.6 ;
    END
  END tx_flit[57]
  PIN tx_flit[58]
    DIRECTION OUTPUT ;
    USE SIGNAL ;
    PORT
      LAYER M5 ;
        RECT  34.416 21.516 34.44 21.6 ;
    END
  END tx_flit[58]
  PIN tx_flit[59]
    DIRECTION OUTPUT ;
    USE SIGNAL ;
    PORT
      LAYER M5 ;
        RECT  34.512 21.516 34.536 21.6 ;
    END
  END tx_flit[59]
  PIN tx_flit[5]
    DIRECTION OUTPUT ;
    USE SIGNAL ;
    PORT
      LAYER M5 ;
        RECT  29.328 21.516 29.352 21.6 ;
    END
  END tx_flit[5]
  PIN tx_flit[60]
    DIRECTION OUTPUT ;
    USE SIGNAL ;
    PORT
      LAYER M5 ;
        RECT  34.608 21.516 34.632 21.6 ;
    END
  END tx_flit[60]
  PIN tx_flit[61]
    DIRECTION OUTPUT ;
    USE SIGNAL ;
    PORT
      LAYER M5 ;
        RECT  34.704 21.516 34.728 21.6 ;
    END
  END tx_flit[61]
  PIN tx_flit[62]
    DIRECTION OUTPUT ;
    USE SIGNAL ;
    PORT
      LAYER M5 ;
        RECT  34.8 21.516 34.824 21.6 ;
    END
  END tx_flit[62]
  PIN tx_flit[63]
    DIRECTION OUTPUT ;
    USE SIGNAL ;
    PORT
      LAYER M5 ;
        RECT  34.896 21.516 34.92 21.6 ;
    END
  END tx_flit[63]
  PIN tx_flit[64]
    DIRECTION OUTPUT ;
    USE SIGNAL ;
    PORT
      LAYER M5 ;
        RECT  38.064 21.516 38.088 21.6 ;
    END
  END tx_flit[64]
  PIN tx_flit[65]
    DIRECTION OUTPUT ;
    USE SIGNAL ;
    PORT
      LAYER M5 ;
        RECT  38.16 21.516 38.184 21.6 ;
    END
  END tx_flit[65]
  PIN tx_flit[66]
    DIRECTION OUTPUT ;
    USE SIGNAL ;
    PORT
      LAYER M5 ;
        RECT  38.256 21.516 38.28 21.6 ;
    END
  END tx_flit[66]
  PIN tx_flit[67]
    DIRECTION OUTPUT ;
    USE SIGNAL ;
    PORT
      LAYER M5 ;
        RECT  38.352 21.516 38.376 21.6 ;
    END
  END tx_flit[67]
  PIN tx_flit[68]
    DIRECTION OUTPUT ;
    USE SIGNAL ;
    PORT
      LAYER M5 ;
        RECT  38.448 21.516 38.472 21.6 ;
    END
  END tx_flit[68]
  PIN tx_flit[69]
    DIRECTION OUTPUT ;
    USE SIGNAL ;
    PORT
      LAYER M5 ;
        RECT  38.544 21.516 38.568 21.6 ;
    END
  END tx_flit[69]
  PIN tx_flit[6]
    DIRECTION OUTPUT ;
    USE SIGNAL ;
    PORT
      LAYER M5 ;
        RECT  29.424 21.516 29.448 21.6 ;
    END
  END tx_flit[6]
  PIN tx_flit[70]
    DIRECTION OUTPUT ;
    USE SIGNAL ;
    PORT
      LAYER M5 ;
        RECT  38.64 21.516 38.664 21.6 ;
    END
  END tx_flit[70]
  PIN tx_flit[71]
    DIRECTION OUTPUT ;
    USE SIGNAL ;
    PORT
      LAYER M5 ;
        RECT  38.736 21.516 38.76 21.6 ;
    END
  END tx_flit[71]
  PIN tx_flit[72]
    DIRECTION OUTPUT ;
    USE SIGNAL ;
    PORT
      LAYER M5 ;
        RECT  38.832 21.516 38.856 21.6 ;
    END
  END tx_flit[72]
  PIN tx_flit[73]
    DIRECTION OUTPUT ;
    USE SIGNAL ;
    PORT
      LAYER M5 ;
        RECT  38.928 21.516 38.952 21.6 ;
    END
  END tx_flit[73]
  PIN tx_flit[74]
    DIRECTION OUTPUT ;
    USE SIGNAL ;
    PORT
      LAYER M5 ;
        RECT  39.024 21.516 39.048 21.6 ;
    END
  END tx_flit[74]
  PIN tx_flit[75]
    DIRECTION OUTPUT ;
    USE SIGNAL ;
    PORT
      LAYER M5 ;
        RECT  39.12 21.516 39.144 21.6 ;
    END
  END tx_flit[75]
  PIN tx_flit[76]
    DIRECTION OUTPUT ;
    USE SIGNAL ;
    PORT
      LAYER M5 ;
        RECT  39.216 21.516 39.24 21.6 ;
    END
  END tx_flit[76]
  PIN tx_flit[77]
    DIRECTION OUTPUT ;
    USE SIGNAL ;
    PORT
      LAYER M5 ;
        RECT  39.312 21.516 39.336 21.6 ;
    END
  END tx_flit[77]
  PIN tx_flit[78]
    DIRECTION OUTPUT ;
    USE SIGNAL ;
    PORT
      LAYER M5 ;
        RECT  39.408 21.516 39.432 21.6 ;
    END
  END tx_flit[78]
  PIN tx_flit[79]
    DIRECTION OUTPUT ;
    USE SIGNAL ;
    PORT
      LAYER M5 ;
        RECT  39.504 21.516 39.528 21.6 ;
    END
  END tx_flit[79]
  PIN tx_flit[7]
    DIRECTION OUTPUT ;
    USE SIGNAL ;
    PORT
      LAYER M5 ;
        RECT  29.52 21.516 29.544 21.6 ;
    END
  END tx_flit[7]
  PIN tx_flit[80]
    DIRECTION OUTPUT ;
    USE SIGNAL ;
    PORT
      LAYER M5 ;
        RECT  39.6 21.516 39.624 21.6 ;
    END
  END tx_flit[80]
  PIN tx_flit[81]
    DIRECTION OUTPUT ;
    USE SIGNAL ;
    PORT
      LAYER M5 ;
        RECT  39.696 21.516 39.72 21.6 ;
    END
  END tx_flit[81]
  PIN tx_flit[82]
    DIRECTION OUTPUT ;
    USE SIGNAL ;
    PORT
      LAYER M5 ;
        RECT  39.792 21.516 39.816 21.6 ;
    END
  END tx_flit[82]
  PIN tx_flit[83]
    DIRECTION OUTPUT ;
    USE SIGNAL ;
    PORT
      LAYER M5 ;
        RECT  39.888 21.516 39.912 21.6 ;
    END
  END tx_flit[83]
  PIN tx_flit[84]
    DIRECTION OUTPUT ;
    USE SIGNAL ;
    PORT
      LAYER M5 ;
        RECT  39.984 21.516 40.008 21.6 ;
    END
  END tx_flit[84]
  PIN tx_flit[85]
    DIRECTION OUTPUT ;
    USE SIGNAL ;
    PORT
      LAYER M5 ;
        RECT  40.08 21.516 40.104 21.6 ;
    END
  END tx_flit[85]
  PIN tx_flit[86]
    DIRECTION OUTPUT ;
    USE SIGNAL ;
    PORT
      LAYER M5 ;
        RECT  40.176 21.516 40.2 21.6 ;
    END
  END tx_flit[86]
  PIN tx_flit[87]
    DIRECTION OUTPUT ;
    USE SIGNAL ;
    PORT
      LAYER M5 ;
        RECT  40.272 21.516 40.296 21.6 ;
    END
  END tx_flit[87]
  PIN tx_flit[88]
    DIRECTION OUTPUT ;
    USE SIGNAL ;
    PORT
      LAYER M5 ;
        RECT  40.368 21.516 40.392 21.6 ;
    END
  END tx_flit[88]
  PIN tx_flit[89]
    DIRECTION OUTPUT ;
    USE SIGNAL ;
    PORT
      LAYER M5 ;
        RECT  40.464 21.516 40.488 21.6 ;
    END
  END tx_flit[89]
  PIN tx_flit[8]
    DIRECTION OUTPUT ;
    USE SIGNAL ;
    PORT
      LAYER M5 ;
        RECT  29.616 21.516 29.64 21.6 ;
    END
  END tx_flit[8]
  PIN tx_flit[90]
    DIRECTION OUTPUT ;
    USE SIGNAL ;
    PORT
      LAYER M5 ;
        RECT  40.56 21.516 40.584 21.6 ;
    END
  END tx_flit[90]
  PIN tx_flit[91]
    DIRECTION OUTPUT ;
    USE SIGNAL ;
    PORT
      LAYER M5 ;
        RECT  40.656 21.516 40.68 21.6 ;
    END
  END tx_flit[91]
  PIN tx_flit[92]
    DIRECTION OUTPUT ;
    USE SIGNAL ;
    PORT
      LAYER M5 ;
        RECT  40.752 21.516 40.776 21.6 ;
    END
  END tx_flit[92]
  PIN tx_flit[93]
    DIRECTION OUTPUT ;
    USE SIGNAL ;
    PORT
      LAYER M5 ;
        RECT  40.848 21.516 40.872 21.6 ;
    END
  END tx_flit[93]
  PIN tx_flit[94]
    DIRECTION OUTPUT ;
    USE SIGNAL ;
    PORT
      LAYER M5 ;
        RECT  40.944 21.516 40.968 21.6 ;
    END
  END tx_flit[94]
  PIN tx_flit[95]
    DIRECTION OUTPUT ;
    USE SIGNAL ;
    PORT
      LAYER M5 ;
        RECT  41.04 21.516 41.064 21.6 ;
    END
  END tx_flit[95]
  PIN tx_flit[96]
    DIRECTION OUTPUT ;
    USE SIGNAL ;
    PORT
      LAYER M5 ;
        RECT  34.992 21.516 35.016 21.6 ;
    END
  END tx_flit[96]
  PIN tx_flit[97]
    DIRECTION OUTPUT ;
    USE SIGNAL ;
    PORT
      LAYER M5 ;
        RECT  35.088 21.516 35.112 21.6 ;
    END
  END tx_flit[97]
  PIN tx_flit[98]
    DIRECTION OUTPUT ;
    USE SIGNAL ;
    PORT
      LAYER M5 ;
        RECT  35.184 21.516 35.208 21.6 ;
    END
  END tx_flit[98]
  PIN tx_flit[99]
    DIRECTION OUTPUT ;
    USE SIGNAL ;
    PORT
      LAYER M5 ;
        RECT  35.28 21.516 35.304 21.6 ;
    END
  END tx_flit[99]
  PIN tx_flit[9]
    DIRECTION OUTPUT ;
    USE SIGNAL ;
    PORT
      LAYER M5 ;
        RECT  29.712 21.516 29.736 21.6 ;
    END
  END tx_flit[9]
  PIN tx_up
    DIRECTION INPUT ;
    USE SIGNAL ;
    PORT
      LAYER M5 ;
        RECT  28.656 21.516 28.68 21.6 ;
    END
  END tx_up
  PIN tx_v
    DIRECTION OUTPUT ;
    USE SIGNAL ;
    PORT
      LAYER M5 ;
        RECT  28.752 21.516 28.776 21.6 ;
    END
  END tx_v
  PIN upq
    DIRECTION OUTPUT ;
    USE SIGNAL ;
    PORT
      LAYER M5 ;
        RECT  58.032 0 58.056 0.084 ;
    END
  END upq
  PIN VDD
    DIRECTION INOUT ;
    USE POWER ;
    PORT
      LAYER M5 ;
        RECT  83.592 2.151 83.712 19.449 ;
        RECT  78.192 2.151 78.312 19.449 ;
        RECT  72.792 2.151 72.912 19.449 ;
        RECT  67.392 2.151 67.512 19.449 ;
        RECT  61.992 2.151 62.112 19.449 ;
        RECT  56.592 2.151 56.712 19.449 ;
        RECT  51.192 2.151 51.312 19.449 ;
        RECT  45.792 2.151 45.912 19.449 ;
        RECT  40.392 2.151 40.512 19.449 ;
        RECT  34.992 2.151 35.112 19.449 ;
        RECT  29.592 2.151 29.712 19.449 ;
        RECT  24.192 2.151 24.312 19.449 ;
        RECT  18.792 2.151 18.912 19.449 ;
        RECT  13.392 2.151 13.512 19.449 ;
        RECT  7.992 2.151 8.112 19.449 ;
        RECT  2.592 2.151 2.712 19.449 ;
    END
  END VDD
  PIN VSS
    DIRECTION INOUT ;
    USE GROUND ;
    PORT
      LAYER M5 ;
        RECT  83.4 2.137 83.52 19.463 ;
        RECT  78 2.137 78.12 19.463 ;
        RECT  72.6 2.137 72.72 19.463 ;
        RECT  67.2 2.137 67.32 19.463 ;
        RECT  61.8 2.137 61.92 19.463 ;
        RECT  56.4 2.137 56.52 19.463 ;
        RECT  51 2.137 51.12 19.463 ;
        RECT  45.6 2.137 45.72 19.463 ;
        RECT  40.2 2.137 40.32 19.463 ;
        RECT  34.8 2.137 34.92 19.463 ;
        RECT  29.4 2.137 29.52 19.463 ;
        RECT  24 2.137 24.12 19.463 ;
        RECT  18.6 2.137 18.72 19.463 ;
        RECT  13.2 2.137 13.32 19.463 ;
        RECT  7.8 2.137 7.92 19.463 ;
        RECT  2.4 2.137 2.52 19.463 ;
    END
  END VSS
  # OT_OBS_CLOSED layer=M5 d_um=1.536 added=76
  OBS
    LAYER RVTN ;
     RECT  2.16 2.16 84.24 2.295 ;
     RECT  2.16 2.565 84.24 2.835 ;
     RECT  2.16 3.105 84.24 3.375 ;
     RECT  2.16 3.645 84.24 3.915 ;
     RECT  2.16 4.185 84.24 4.455 ;
     RECT  2.16 4.725 84.24 4.995 ;
     RECT  2.16 5.265 84.24 5.535 ;
     RECT  2.16 5.805 84.24 6.075 ;
     RECT  2.16 6.345 84.24 6.615 ;
     RECT  2.16 6.885 84.24 7.155 ;
     RECT  2.16 7.425 84.24 7.695 ;
     RECT  2.16 7.965 84.24 8.235 ;
     RECT  2.16 8.505 84.24 8.775 ;
     RECT  2.16 9.045 84.24 9.315 ;
     RECT  2.16 9.585 84.24 9.855 ;
     RECT  2.16 10.125 84.24 10.395 ;
     RECT  2.16 10.665 84.24 10.935 ;
     RECT  2.16 11.205 84.24 11.475 ;
     RECT  2.16 11.745 84.24 12.015 ;
     RECT  2.16 12.285 84.24 12.555 ;
     RECT  2.16 12.825 84.24 13.095 ;
     RECT  2.16 13.365 84.24 13.635 ;
     RECT  2.16 13.905 84.24 14.175 ;
     RECT  2.16 14.445 84.24 14.715 ;
     RECT  2.16 14.985 84.24 15.255 ;
     RECT  2.16 15.525 84.24 15.795 ;
     RECT  2.16 16.065 84.24 16.335 ;
     RECT  2.16 16.605 84.24 16.875 ;
     RECT  2.16 17.145 84.24 17.415 ;
     RECT  2.16 17.685 84.24 17.955 ;
     RECT  2.16 18.225 84.24 18.495 ;
     RECT  2.16 18.765 84.24 19.035 ;
     RECT  2.16 19.305 84.24 19.44 ;
    LAYER RVTP ;
     RECT  2.16 2.295 84.24 2.565 ;
     RECT  2.16 2.835 84.24 3.105 ;
     RECT  2.16 3.375 84.24 3.645 ;
     RECT  2.16 3.915 84.24 4.185 ;
     RECT  2.16 4.455 84.24 4.725 ;
     RECT  2.16 4.995 84.24 5.265 ;
     RECT  2.16 5.535 84.24 5.805 ;
     RECT  2.16 6.075 84.24 6.345 ;
     RECT  2.16 6.615 84.24 6.885 ;
     RECT  2.16 7.155 84.24 7.425 ;
     RECT  2.16 7.695 84.24 7.965 ;
     RECT  2.16 8.235 84.24 8.505 ;
     RECT  2.16 8.775 84.24 9.045 ;
     RECT  2.16 9.315 84.24 9.585 ;
     RECT  2.16 9.855 84.24 10.125 ;
     RECT  2.16 10.395 84.24 10.665 ;
     RECT  2.16 10.935 84.24 11.205 ;
     RECT  2.16 11.475 84.24 11.745 ;
     RECT  2.16 12.015 84.24 12.285 ;
     RECT  2.16 12.555 84.24 12.825 ;
     RECT  2.16 13.095 84.24 13.365 ;
     RECT  2.16 13.635 84.24 13.905 ;
     RECT  2.16 14.175 84.24 14.445 ;
     RECT  2.16 14.715 84.24 14.985 ;
     RECT  2.16 15.255 84.24 15.525 ;
     RECT  2.16 15.795 84.24 16.065 ;
     RECT  2.16 16.335 84.24 16.605 ;
     RECT  2.16 16.875 84.24 17.145 ;
     RECT  2.16 17.415 84.24 17.685 ;
     RECT  2.16 17.955 84.24 18.225 ;
     RECT  2.16 18.495 84.24 18.765 ;
     RECT  2.16 19.035 84.24 19.305 ;
    LAYER M1 ;
     RECT  2.16 2.151 84.24 19.449 ;
    LAYER M2 ;
     RECT  2.16 2.151 11.803 19.449 ;
     RECT  11.803 2.151 14.827 19.494 ;
     RECT  14.827 2.151 15.655 19.566 ;
     RECT  15.403 0.414 16.267 0.432 ;
     RECT  16.267 0.414 17.347 0.549 ;
     RECT  17.347 0.378 17.383 0.549 ;
     RECT  15.655 2.151 17.635 19.638 ;
     RECT  17.383 0.378 18.391 1.134 ;
     RECT  17.635 2.151 18.391 20.034 ;
     RECT  18.391 0.378 22.099 20.034 ;
     RECT  22.099 0.261 23.647 20.034 ;
     RECT  23.647 0.261 37.363 20.142 ;
     RECT  37.363 0.216 38.119 20.142 ;
     RECT  38.119 0.18 42.763 20.142 ;
     RECT  42.763 0.18 49.739 20.178 ;
     RECT  49.739 0.18 53.699 20.142 ;
     RECT  53.699 0.216 53.879 20.142 ;
     RECT  53.879 0.261 53.915 20.142 ;
     RECT  53.915 0.261 54.923 20.106 ;
     RECT  54.923 0.261 55.391 20.07 ;
     RECT  55.391 0.306 59.171 20.07 ;
     RECT  59.171 0.306 62.267 19.989 ;
     RECT  62.267 0.342 62.591 19.989 ;
     RECT  62.591 0.342 62.663 19.494 ;
     RECT  62.663 0.342 63.311 19.449 ;
     RECT  63.311 0.45 66.155 19.449 ;
     RECT  66.155 0.486 72.167 19.449 ;
     RECT  72.167 1.026 73.895 19.449 ;
     RECT  73.895 1.026 74.435 1.089 ;
     RECT  73.895 2.106 74.471 19.449 ;
     RECT  74.435 1.071 74.579 1.089 ;
     RECT  74.471 2.151 84.24 19.449 ;
    LAYER M3 ;
     RECT  20.7 0.091 20.718 0.139 ;
     RECT  67.428 0.091 67.446 0.139 ;
     RECT  53.676 0.175 53.694 0.211 ;
     RECT  46.656 0.091 46.674 0.235 ;
     RECT  21.672 0.091 21.69 0.256 ;
     RECT  67.428 0.139 67.554 0.269 ;
     RECT  61.596 0.091 61.614 0.301 ;
     RECT  21.672 0.256 22.122 0.337 ;
     RECT  23.004 0.091 23.598 0.337 ;
     RECT  61.596 0.301 62.262 0.409 ;
     RECT  37.368 0.211 37.386 0.427 ;
     RECT  38.124 0.175 38.142 0.427 ;
     RECT  49.392 0.091 49.41 0.427 ;
     RECT  17.352 0.373 17.37 0.445 ;
     RECT  65.52 0.091 65.538 0.445 ;
     RECT  27.144 0.301 27.162 0.475 ;
     RECT  31.644 0.427 31.662 0.475 ;
     RECT  49.392 0.427 49.554 0.475 ;
     RECT  55.368 0.256 55.386 0.523 ;
     RECT  58.428 0.373 58.446 0.523 ;
     RECT  72.144 0.481 72.162 0.526 ;
     RECT  19.584 0.481 19.602 0.571 ;
     RECT  20.556 0.139 20.718 0.571 ;
     RECT  31.644 0.475 31.806 0.571 ;
     RECT  33.552 0.475 33.57 0.571 ;
     RECT  37.368 0.427 38.142 0.571 ;
     RECT  39.204 0.475 39.222 0.571 ;
     RECT  41.724 0.091 41.742 0.571 ;
     RECT  49.104 0.475 49.554 0.571 ;
     RECT  53.676 0.211 53.874 0.571 ;
     RECT  58.248 0.523 58.95 0.571 ;
     RECT  65.52 0.445 66.15 0.571 ;
     RECT  68.94 0.091 68.958 0.571 ;
     RECT  26.82 0.475 27.162 0.751 ;
     RECT  54.684 0.523 55.602 0.751 ;
     RECT  21.672 0.337 23.598 0.796 ;
     RECT  53.028 0.571 53.874 0.796 ;
     RECT  54.684 0.751 56.106 0.796 ;
     RECT  26.568 0.751 27.162 0.877 ;
     RECT  61.596 0.409 62.55 0.877 ;
     RECT  63.288 0.337 63.306 0.877 ;
     RECT  19.584 0.571 20.718 0.913 ;
     RECT  21.6 0.796 23.598 0.913 ;
     RECT  61.596 0.877 63.306 0.913 ;
     RECT  17.352 0.445 17.91 0.949 ;
     RECT  34.524 0.475 34.542 1.003 ;
     RECT  41.688 0.571 41.742 1.003 ;
     RECT  46.224 0.235 46.674 1.003 ;
     RECT  58.248 0.571 59.31 1.003 ;
     RECT  60.336 0.571 60.714 1.003 ;
     RECT  61.596 0.913 63.666 1.003 ;
     RECT  74.412 1.021 74.43 1.051 ;
     RECT  73.836 1.051 74.43 1.066 ;
     RECT  15.408 0.409 15.426 1.099 ;
     RECT  16.272 0.526 16.29 1.099 ;
     RECT  73.836 1.066 74.574 1.099 ;
     RECT  72.972 0.571 72.99 1.111 ;
     RECT  73.836 1.099 74.898 1.111 ;
     RECT  19.584 0.913 23.598 1.147 ;
     RECT  33.084 0.571 33.642 1.147 ;
     RECT  51.444 0.523 51.462 1.147 ;
     RECT  49.032 0.571 49.554 1.243 ;
     RECT  50.832 1.147 51.462 1.435 ;
     RECT  36.36 0.091 36.378 1.453 ;
     RECT  31.644 0.571 31.95 1.483 ;
     RECT  39.96 0.571 39.978 1.483 ;
     RECT  46.08 1.003 46.674 1.483 ;
     RECT  24.444 1.051 24.462 1.531 ;
     RECT  17.352 0.949 18.234 1.561 ;
     RECT  15.408 1.099 16.29 1.579 ;
     RECT  17.352 1.561 18.414 1.579 ;
     RECT  58.248 1.003 63.666 1.579 ;
     RECT  25.668 0.841 25.686 1.627 ;
     RECT  26.568 0.877 27.522 1.627 ;
     RECT  67.536 0.269 67.554 1.651 ;
     RECT  68.436 0.571 70.218 1.651 ;
     RECT  24.444 1.531 24.93 1.675 ;
     RECT  25.668 1.627 27.522 1.675 ;
     RECT  19.584 1.147 23.67 1.687 ;
     RECT  71.496 0.526 72.162 1.687 ;
     RECT  19.188 1.687 23.67 1.723 ;
     RECT  24.444 1.675 27.522 1.723 ;
     RECT  28.548 1.051 29.286 1.723 ;
     RECT  30.564 0.475 30.582 1.723 ;
     RECT  31.644 1.483 32.094 1.723 ;
     RECT  33.084 1.147 33.714 1.723 ;
     RECT  34.524 1.003 34.614 1.723 ;
     RECT  36.108 1.453 36.378 1.723 ;
     RECT  37.188 0.571 38.142 1.723 ;
     RECT  38.88 0.571 39.222 1.723 ;
     RECT  39.96 1.483 40.014 1.723 ;
     RECT  41.004 1.003 41.742 1.723 ;
     RECT  42.768 0.571 42.786 1.723 ;
     RECT  43.56 1.003 43.578 1.723 ;
     RECT  44.424 1.483 44.442 1.723 ;
     RECT  45.972 1.483 46.674 1.723 ;
     RECT  48.744 1.243 49.554 1.723 ;
     RECT  50.832 1.435 52.146 1.723 ;
     RECT  53.028 0.796 56.106 1.723 ;
     RECT  57.06 0.571 57.078 1.723 ;
     RECT  57.996 1.579 63.666 1.723 ;
     RECT  65.016 0.571 66.762 1.723 ;
     RECT  67.536 1.651 70.218 1.723 ;
     RECT  71.496 1.687 72.234 1.723 ;
     RECT  72.972 1.111 74.898 1.723 ;
     RECT  19.188 1.723 66.762 1.963 ;
     RECT  67.536 1.723 74.898 1.963 ;
     RECT  15.408 1.579 18.414 2.143 ;
     RECT  19.188 1.963 74.898 2.143 ;
     RECT  2.415 2.143 2.505 2.413 ;
     RECT  7.815 2.143 7.905 2.413 ;
     RECT  13.215 2.143 13.305 2.413 ;
     RECT  78.015 2.143 78.105 2.413 ;
     RECT  83.415 2.143 83.505 2.413 ;
     RECT  15.408 2.143 74.898 2.731 ;
     RECT  15.408 2.731 75.15 3.001 ;
     RECT  15.408 3.001 75.294 3.053 ;
     RECT  15.408 3.053 75.15 3.569 ;
     RECT  15.408 3.569 75.006 3.605 ;
     RECT  15.408 3.605 74.934 4.109 ;
     RECT  15.408 4.109 74.898 4.351 ;
     RECT  75.924 3.721 75.942 4.451 ;
     RECT  15.264 4.351 74.898 4.559 ;
     RECT  17.82 4.559 74.898 4.649 ;
     RECT  14.508 4.081 14.526 4.801 ;
     RECT  15.264 4.559 16.722 4.801 ;
     RECT  17.82 4.649 74.61 4.919 ;
     RECT  17.82 4.919 74.178 5.189 ;
     RECT  17.82 5.189 74.034 5.225 ;
     RECT  14.508 4.801 16.722 5.515 ;
     RECT  17.82 5.225 73.998 5.515 ;
     RECT  14.508 5.515 73.998 5.729 ;
     RECT  14.508 5.729 73.638 5.803 ;
     RECT  13.215 2.413 13.497 6.091 ;
     RECT  14.22 5.803 73.638 6.269 ;
     RECT  12.492 6.091 13.497 7.465 ;
     RECT  14.22 6.269 72.897 7.465 ;
     RECT  3.996 7.339 4.014 7.655 ;
     RECT  12.492 7.465 72.897 7.771 ;
     RECT  73.62 6.269 73.638 7.771 ;
     RECT  12.492 7.771 73.638 10.061 ;
     RECT  12.492 10.061 71.838 10.109 ;
     RECT  12.492 10.109 71.118 10.733 ;
     RECT  12.492 10.733 69.03 10.769 ;
     RECT  69.876 10.733 71.118 10.925 ;
     RECT  69.876 10.925 70.938 10.973 ;
     RECT  69.876 10.973 70.182 11.021 ;
     RECT  72.615 10.061 73.638 11.435 ;
     RECT  70.92 10.973 70.938 11.453 ;
     RECT  69.876 11.021 69.894 11.501 ;
     RECT  12.492 10.769 68.058 11.543 ;
     RECT  72.615 11.435 73.17 12.029 ;
     RECT  12.492 11.543 57.942 12.361 ;
     RECT  58.752 11.543 68.058 12.361 ;
     RECT  12.492 12.361 68.058 12.821 ;
     RECT  12.492 12.821 67.734 13.037 ;
     RECT  12.492 13.037 64.062 13.369 ;
     RECT  12.384 13.369 64.062 14.881 ;
     RECT  12.384 14.881 64.134 14.909 ;
     RECT  12.456 14.909 64.134 15.025 ;
     RECT  64.872 13.037 67.734 15.025 ;
     RECT  12.456 15.025 67.734 16.951 ;
     RECT  12.384 16.951 67.734 17.041 ;
     RECT  12.024 17.041 67.734 17.077 ;
     RECT  69.012 10.769 69.03 17.411 ;
     RECT  11.808 17.077 67.734 18.149 ;
     RECT  11.808 18.149 67.59 18.995 ;
     RECT  2.415 2.413 2.697 19.187 ;
     RECT  7.815 2.413 8.097 19.187 ;
     RECT  72.615 12.029 72.897 19.187 ;
     RECT  78.015 2.413 78.297 19.187 ;
     RECT  83.415 2.413 83.697 19.187 ;
     RECT  12.6 18.995 67.59 19.337 ;
     RECT  12.6 19.337 67.305 19.373 ;
     RECT  2.415 19.187 2.505 19.457 ;
     RECT  7.815 19.187 7.905 19.457 ;
     RECT  66.564 19.373 67.305 19.457 ;
     RECT  72.615 19.187 72.705 19.457 ;
     RECT  78.015 19.187 78.105 19.457 ;
     RECT  83.415 19.187 83.505 19.457 ;
     RECT  31.356 19.373 65.826 19.469 ;
     RECT  11.808 18.995 11.826 19.499 ;
     RECT  31.356 19.469 37.638 19.607 ;
     RECT  38.376 19.469 65.826 19.841 ;
     RECT  12.6 19.373 30.51 19.949 ;
     RECT  31.356 19.607 37.53 19.949 ;
     RECT  38.376 19.841 47.25 19.949 ;
     RECT  48.24 19.841 65.826 19.949 ;
     RECT  66.564 19.457 66.582 19.949 ;
     RECT  40.824 19.949 47.25 19.997 ;
     RECT  54.9 19.949 56.574 19.997 ;
     RECT  57.42 19.949 65.826 19.997 ;
     RECT  40.824 19.997 44.226 20.075 ;
     RECT  12.6 19.949 26.226 20.111 ;
     RECT  54.9 19.997 56.25 20.111 ;
     RECT  12.6 20.111 24.498 20.147 ;
     RECT  40.824 20.075 42.786 20.183 ;
     RECT  48.24 19.949 50.742 20.285 ;
     RECT  38.376 19.949 39.978 20.381 ;
     RECT  40.824 20.183 42.102 20.381 ;
     RECT  55.116 20.111 56.25 20.381 ;
     RECT  64.764 19.997 65.826 20.429 ;
     RECT  12.6 20.147 23.598 20.477 ;
     RECT  38.376 20.381 39.546 20.477 ;
     RECT  43.56 20.075 44.226 20.477 ;
     RECT  55.116 20.381 56.214 20.477 ;
     RECT  57.42 19.997 63.918 20.477 ;
     RECT  12.924 20.477 23.598 20.525 ;
     RECT  24.336 20.147 24.498 20.525 ;
     RECT  25.272 20.111 26.226 20.525 ;
     RECT  26.964 19.949 30.51 20.525 ;
     RECT  31.356 19.949 36.198 20.525 ;
     RECT  36.936 19.949 37.026 20.525 ;
     RECT  38.376 20.477 38.394 20.525 ;
     RECT  39.168 20.477 39.546 20.525 ;
     RECT  40.86 20.381 42.102 20.525 ;
     RECT  43.56 20.477 44.01 20.525 ;
     RECT  45 19.997 47.25 20.525 ;
     RECT  48.24 20.285 48.69 20.525 ;
     RECT  49.5 20.285 50.742 20.525 ;
     RECT  51.588 19.949 53.982 20.525 ;
     RECT  55.116 20.477 55.962 20.525 ;
     RECT  57.492 20.477 63.918 20.525 ;
     RECT  64.8 20.429 65.826 20.525 ;
     RECT  13.356 20.525 14.49 20.573 ;
     RECT  22.14 20.525 22.734 20.573 ;
     RECT  48.24 20.525 48.294 20.573 ;
     RECT  52.38 20.525 53.874 20.573 ;
     RECT  57.924 20.525 58.662 20.573 ;
     RECT  60.192 20.525 60.93 20.573 ;
     RECT  61.74 20.525 61.758 20.573 ;
     RECT  62.676 20.525 63.918 20.573 ;
     RECT  13.608 20.573 14.13 20.621 ;
     RECT  24.336 20.525 24.426 20.621 ;
     RECT  25.38 20.525 26.226 20.621 ;
     RECT  49.536 20.525 50.742 20.669 ;
     RECT  24.336 20.621 24.354 20.717 ;
     RECT  31.356 20.525 31.374 20.765 ;
     RECT  33.084 20.525 35.154 20.765 ;
     RECT  39.204 20.525 39.546 20.765 ;
     RECT  45.036 20.525 47.25 20.765 ;
     RECT  36 20.525 36.198 21.197 ;
     RECT  45.432 20.765 47.25 21.245 ;
     RECT  39.204 20.765 39.402 21.259 ;
     RECT  21.168 20.525 21.33 21.341 ;
     RECT  26.064 20.621 26.226 21.437 ;
     RECT  32.112 20.525 32.346 21.437 ;
     RECT  46.008 21.245 47.25 21.437 ;
     RECT  14.112 20.621 14.13 21.485 ;
     RECT  17.532 20.525 18.774 21.485 ;
     RECT  19.584 20.525 19.602 21.485 ;
     RECT  22.716 20.573 22.734 21.485 ;
     RECT  26.064 21.437 26.082 21.485 ;
     RECT  27.108 20.525 27.126 21.485 ;
     RECT  27.9 20.525 30.366 21.485 ;
     RECT  32.112 21.437 32.13 21.485 ;
     RECT  33.588 20.765 33.606 21.485 ;
     RECT  34.524 20.765 35.154 21.485 ;
     RECT  36.18 21.197 36.198 21.485 ;
     RECT  36.936 20.525 36.954 21.485 ;
     RECT  38.736 21.259 39.402 21.485 ;
     RECT  41.436 20.525 41.454 21.485 ;
     RECT  43.56 20.525 43.83 21.485 ;
     RECT  46.008 21.437 46.134 21.485 ;
     RECT  46.908 21.437 47.25 21.485 ;
     RECT  48.276 20.573 48.294 21.485 ;
     RECT  49.536 20.669 49.806 21.485 ;
     RECT  52.38 20.573 52.398 21.485 ;
     RECT  53.424 20.573 53.874 21.485 ;
     RECT  55.116 20.525 55.134 21.485 ;
     RECT  57.924 20.573 57.942 21.485 ;
     RECT  60.192 20.573 60.21 21.485 ;
     RECT  63.144 20.573 63.918 21.485 ;
    LAYER M4 ;
     RECT  0.06 7.248 0.133 7.368 ;
     RECT  0.133 6.576 2.408 7.368 ;
     RECT  2.408 2.148 2.512 19.452 ;
     RECT  2.512 2.418 2.704 19.182 ;
     RECT  2.704 6.576 4.025 7.368 ;
     RECT  4.025 6.576 7.808 6.6 ;
     RECT  7.808 2.148 7.912 19.452 ;
     RECT  7.912 2.418 8.104 19.182 ;
     RECT  8.104 6.576 12.481 6.6 ;
     RECT  12.589 20.448 12.709 20.472 ;
     RECT  12.733 19.392 12.769 19.416 ;
     RECT  12.709 20.448 12.769 20.52 ;
     RECT  12.769 19.392 12.901 20.52 ;
     RECT  12.481 6.096 13.208 6.6 ;
     RECT  12.901 19.344 13.208 20.52 ;
     RECT  13.208 2.148 13.312 20.52 ;
     RECT  13.312 2.418 13.34 20.52 ;
     RECT  13.34 2.418 13.504 20.568 ;
     RECT  13.504 18.432 13.597 20.568 ;
     RECT  13.597 18.432 13.861 20.616 ;
     RECT  13.861 18.432 14.141 21.48 ;
     RECT  13.504 5.808 14.569 6.6 ;
     RECT  14.141 18.432 14.675 20.568 ;
     RECT  14.749 15.984 14.821 16.008 ;
     RECT  14.675 18.432 15.013 20.52 ;
     RECT  15.013 18.144 15.401 20.52 ;
     RECT  15.401 18.144 16.049 18.84 ;
     RECT  14.569 5.808 16.081 7.224 ;
     RECT  13.504 14.736 16.117 14.76 ;
     RECT  16.117 14.736 16.189 14.856 ;
     RECT  14.821 15.984 16.225 16.344 ;
     RECT  16.189 14.736 16.445 14.952 ;
     RECT  16.049 18.192 16.645 18.84 ;
     RECT  15.401 19.92 16.645 20.52 ;
     RECT  15.829 1.104 16.657 1.128 ;
     RECT  16.645 18.192 17.477 20.52 ;
     RECT  16.225 15.984 17.549 16.824 ;
     RECT  14.641 13.344 17.629 13.368 ;
     RECT  17.549 15.984 17.633 17.112 ;
     RECT  17.629 13.344 18.205 13.416 ;
     RECT  16.445 14.736 18.205 14.76 ;
     RECT  17.633 15.984 18.277 16.824 ;
     RECT  16.657 1.104 18.608 1.608 ;
     RECT  16.081 5.472 18.608 7.224 ;
     RECT  17.233 9.072 18.608 9.096 ;
     RECT  18.169 12.24 18.608 12.264 ;
     RECT  18.205 13.344 18.608 14.76 ;
     RECT  18.277 15.84 18.608 16.824 ;
     RECT  17.477 18.192 18.608 21.48 ;
     RECT  18.608 1.104 18.904 21.48 ;
     RECT  18.904 18.096 19.001 21.48 ;
     RECT  19.001 21.456 19.613 21.48 ;
     RECT  18.904 1.104 19.645 1.704 ;
     RECT  19.645 1.056 19.969 1.704 ;
     RECT  19.001 18.096 19.973 20.472 ;
     RECT  19.969 0.576 20.005 1.704 ;
     RECT  18.904 13.344 20.005 14.76 ;
     RECT  18.904 15.84 20.005 16.824 ;
     RECT  19.973 18.144 20.005 20.472 ;
     RECT  20.005 0.576 20.041 1.752 ;
     RECT  18.904 5.088 20.149 7.224 ;
     RECT  20.005 18.144 20.153 20.52 ;
     RECT  20.041 0.576 20.221 1.848 ;
     RECT  18.904 2.832 20.221 3.72 ;
     RECT  20.221 0.576 20.545 3.72 ;
     RECT  20.545 0.144 20.645 3.72 ;
     RECT  20.149 4.992 20.689 7.224 ;
     RECT  20.645 0.096 20.869 3.72 ;
     RECT  18.904 12.24 20.869 12.264 ;
     RECT  20.869 0.096 21.107 3.864 ;
     RECT  20.005 13.344 21.107 16.824 ;
     RECT  20.153 18.192 21.116 20.52 ;
     RECT  21.107 1.104 21.203 3.864 ;
     RECT  21.116 18.192 21.341 21.336 ;
     RECT  21.107 15.84 21.445 16.824 ;
     RECT  21.107 13.344 21.449 14.856 ;
     RECT  21.203 2.832 21.596 3.864 ;
     RECT  20.689 4.992 21.596 7.416 ;
     RECT  21.107 0.096 21.701 0.12 ;
     RECT  21.203 1.104 22.165 1.848 ;
     RECT  21.596 2.832 22.165 7.416 ;
     RECT  21.341 18.192 22.597 20.568 ;
     RECT  21.769 10.704 22.633 10.728 ;
     RECT  20.869 12.192 22.633 12.264 ;
     RECT  21.445 15.84 22.741 17.064 ;
     RECT  22.597 18.192 22.745 21.48 ;
     RECT  22.165 1.104 22.813 7.416 ;
     RECT  21.449 13.344 22.849 14.76 ;
     RECT  22.741 15.84 22.849 17.208 ;
     RECT  22.813 0.576 22.949 7.416 ;
     RECT  22.949 0.096 22.957 7.416 ;
     RECT  22.957 0.096 23.029 7.464 ;
     RECT  23.029 0.096 23.065 7.608 ;
     RECT  23.065 0.096 23.101 7.704 ;
     RECT  23.101 0.096 23.173 7.848 ;
     RECT  23.173 0.096 23.209 8.04 ;
     RECT  18.904 9.072 23.209 9.672 ;
     RECT  22.849 13.344 23.785 17.208 ;
     RECT  22.745 18.192 23.785 20.568 ;
     RECT  23.785 13.344 23.941 20.568 ;
     RECT  23.209 0.096 24.008 9.672 ;
     RECT  22.633 10.704 24.008 12.264 ;
     RECT  23.941 13.344 24.008 21.192 ;
     RECT  24.008 0.096 24.037 21.192 ;
     RECT  24.037 0.096 24.083 21.336 ;
     RECT  24.083 0.144 24.277 21.336 ;
     RECT  24.277 0.144 24.467 21.432 ;
     RECT  24.467 0.144 24.515 21.336 ;
     RECT  24.515 0.528 24.563 20.712 ;
     RECT  24.563 0.528 25.861 20.616 ;
     RECT  25.861 0.528 26.78 21.48 ;
     RECT  26.78 0.48 26.867 21.48 ;
     RECT  26.867 0.528 29.173 21.48 ;
     RECT  29.173 0.192 29.555 21.48 ;
     RECT  29.555 0.528 30.377 21.48 ;
     RECT  30.377 0.528 30.553 20.616 ;
     RECT  30.553 0.48 30.757 20.616 ;
     RECT  30.757 0.144 30.947 20.616 ;
     RECT  30.947 0.432 31.345 20.616 ;
     RECT  31.345 0.432 31.909 20.76 ;
     RECT  31.909 0.432 32.141 21.48 ;
     RECT  32.141 0.432 32.147 21.432 ;
     RECT  32.147 0.48 32.339 21.432 ;
     RECT  32.339 0.528 32.357 21.432 ;
     RECT  32.357 0.528 33.533 20.76 ;
     RECT  33.533 0.528 33.541 21.48 ;
     RECT  33.541 0.48 36.037 21.48 ;
     RECT  36.037 0.096 36.389 21.48 ;
     RECT  36.389 0.528 36.965 21.48 ;
     RECT  36.965 0.528 37.465 20.712 ;
     RECT  37.465 0.48 37.789 20.712 ;
     RECT  37.789 0.432 38.195 20.712 ;
     RECT  38.195 0.528 38.533 20.712 ;
     RECT  38.533 0.528 38.581 21.192 ;
     RECT  38.581 0.528 38.629 21.288 ;
     RECT  38.629 0.528 38.725 21.384 ;
     RECT  38.725 0.528 39.193 21.48 ;
     RECT  39.193 0.48 39.457 21.48 ;
     RECT  39.457 0.48 39.925 21.432 ;
     RECT  39.925 0.144 40.307 21.432 ;
     RECT  40.307 0.192 40.403 21.432 ;
     RECT  40.403 0.528 41.125 21.432 ;
     RECT  41.125 0.528 41.465 21.48 ;
     RECT  41.465 0.528 41.669 21.432 ;
     RECT  41.669 0.096 41.753 21.432 ;
     RECT  41.753 0.528 41.795 21.432 ;
     RECT  41.795 0.528 43.333 20.712 ;
     RECT  43.333 0.528 43.841 21.48 ;
     RECT  43.841 0.528 45.025 20.712 ;
     RECT  45.025 0.528 45.061 20.76 ;
     RECT  45.061 0.528 45.397 21.24 ;
     RECT  45.397 0.144 45.925 21.432 ;
     RECT  45.925 0.144 46.645 21.48 ;
     RECT  46.645 0.096 47.027 21.48 ;
     RECT  47.027 0.528 49.093 21.48 ;
     RECT  49.093 0.48 49.381 21.48 ;
     RECT  49.381 0.096 49.811 21.48 ;
     RECT  49.811 0.432 49.817 21.48 ;
     RECT  49.817 0.432 50.869 21.384 ;
     RECT  50.869 0.144 51.059 21.432 ;
     RECT  51.059 0.144 51.155 21.384 ;
     RECT  51.155 0.528 51.473 20.664 ;
     RECT  51.473 1.056 52.261 20.664 ;
     RECT  52.261 1.056 52.409 21.48 ;
     RECT  52.409 1.056 53.017 20.664 ;
     RECT  53.017 0.576 53.101 20.664 ;
     RECT  53.101 1.056 53.413 20.664 ;
     RECT  53.413 1.056 53.885 21.48 ;
     RECT  53.885 1.056 54.673 20.664 ;
     RECT  54.673 0.528 54.853 20.664 ;
     RECT  54.853 0.528 55.145 21.48 ;
     RECT  55.145 0.528 56.339 20.616 ;
     RECT  56.339 0.576 57.133 20.616 ;
     RECT  57.133 1.056 57.637 20.616 ;
     RECT  57.637 1.056 57.953 21.48 ;
     RECT  57.953 1.056 58.237 20.616 ;
     RECT  58.237 0.528 59.609 20.616 ;
     RECT  59.609 0.528 59.825 20.472 ;
     RECT  59.825 0.528 60.179 20.232 ;
     RECT  59.845 21.456 60.221 21.48 ;
     RECT  60.179 0.576 60.437 20.232 ;
     RECT  60.437 17.136 60.901 20.232 ;
     RECT  60.437 0.576 61.525 16.152 ;
     RECT  60.901 17.136 61.525 20.568 ;
     RECT  61.525 0.576 61.541 20.568 ;
     RECT  61.541 0.096 61.621 20.568 ;
     RECT  61.621 0.096 61.625 21.432 ;
     RECT  61.625 0.192 62.003 21.432 ;
     RECT  62.003 0.192 62.099 20.568 ;
     RECT  62.099 1.008 62.104 20.568 ;
     RECT  62.104 17.424 62.201 18.264 ;
     RECT  62.104 14.112 62.597 16.152 ;
     RECT  62.597 14.832 62.669 16.152 ;
     RECT  62.104 19.248 62.669 20.568 ;
     RECT  62.104 1.008 62.813 13.032 ;
     RECT  62.669 19.344 63.089 20.568 ;
     RECT  62.669 14.832 63.101 15.768 ;
     RECT  63.101 15.456 63.245 15.768 ;
     RECT  62.813 1.056 63.281 13.032 ;
     RECT  63.245 15.744 63.641 15.768 ;
     RECT  63.089 19.344 63.773 21.48 ;
     RECT  63.281 5.712 63.821 13.032 ;
     RECT  62.201 17.424 63.893 17.976 ;
     RECT  63.893 17.952 63.929 17.976 ;
     RECT  63.773 19.248 63.929 21.48 ;
     RECT  63.281 1.056 64.261 4.68 ;
     RECT  63.821 5.712 64.261 12.024 ;
     RECT  63.929 19.248 64.357 20.52 ;
     RECT  63.821 13.008 64.577 13.032 ;
     RECT  64.261 1.056 64.649 12.024 ;
     RECT  64.357 19.2 64.649 20.52 ;
     RECT  64.649 19.2 64.741 19.368 ;
     RECT  64.649 20.4 64.793 20.52 ;
     RECT  64.649 1.056 65.005 7.896 ;
     RECT  64.741 18.864 65.413 19.368 ;
     RECT  65.005 0.576 65.509 7.896 ;
     RECT  65.413 18.72 65.513 19.368 ;
     RECT  65.509 0.096 65.747 7.896 ;
     RECT  64.793 20.448 65.837 20.52 ;
     RECT  65.513 18.816 66.035 19.368 ;
     RECT  65.797 17.088 66.089 17.112 ;
     RECT  66.035 19.2 66.181 19.368 ;
     RECT  66.181 19.2 66.593 19.944 ;
     RECT  65.747 1.008 66.733 7.896 ;
     RECT  66.733 0.576 67.208 7.896 ;
     RECT  64.649 9.12 67.208 12.024 ;
     RECT  66.593 19.2 67.208 19.452 ;
     RECT  67.208 0.576 67.237 19.452 ;
     RECT  67.237 0.288 67.312 19.452 ;
     RECT  67.312 0.288 67.313 19.368 ;
     RECT  67.313 0.288 67.333 19.182 ;
     RECT  67.333 0.192 67.378 19.182 ;
     RECT  67.378 0.096 67.501 19.182 ;
     RECT  67.501 0.144 67.504 19.182 ;
     RECT  67.504 0.144 67.609 6.84 ;
     RECT  67.609 0.192 67.715 6.84 ;
     RECT  67.504 8.16 68.249 12.024 ;
     RECT  67.715 0.576 68.749 6.84 ;
     RECT  68.749 0.576 68.833 6.888 ;
     RECT  68.833 0.576 68.929 6.264 ;
     RECT  68.929 0.096 69.203 6.264 ;
     RECT  69.203 0.576 70.273 6.264 ;
     RECT  70.273 1.056 70.445 6.264 ;
     RECT  70.445 5.712 70.645 6.264 ;
     RECT  70.645 5.712 70.757 6.312 ;
     RECT  69.613 7.44 70.757 7.464 ;
     RECT  68.249 9.12 70.949 12.024 ;
     RECT  70.949 9.12 71.129 10.92 ;
     RECT  70.757 5.712 71.417 7.464 ;
     RECT  71.129 9.12 71.561 10.104 ;
     RECT  70.445 1.056 71.773 4.536 ;
     RECT  71.773 1.008 71.881 4.536 ;
     RECT  71.417 5.712 72.457 6.84 ;
     RECT  71.881 0.576 72.608 4.536 ;
     RECT  72.457 5.568 72.608 6.84 ;
     RECT  71.561 10.032 72.608 10.104 ;
     RECT  70.949 12 72.608 12.024 ;
     RECT  72.608 0.576 72.712 19.452 ;
     RECT  72.712 0.576 72.904 19.182 ;
     RECT  72.904 0.576 73.045 3.432 ;
     RECT  72.904 5.568 73.109 5.592 ;
     RECT  72.904 12 73.181 12.024 ;
     RECT  73.045 1.056 73.469 3.432 ;
     RECT  73.469 1.056 73.549 1.848 ;
     RECT  73.549 1.056 73.865 1.8 ;
     RECT  73.865 1.104 73.937 1.8 ;
     RECT  73.937 1.104 74.009 1.704 ;
     RECT  74.009 1.104 74.621 1.656 ;
     RECT  74.621 1.104 74.909 1.128 ;
     RECT  73.469 3.024 75.017 3.432 ;
     RECT  75.017 3.024 75.305 3.048 ;
     RECT  78.008 2.148 78.112 19.452 ;
     RECT  78.112 2.418 78.304 19.182 ;
     RECT  83.408 2.148 83.512 19.452 ;
     RECT  83.512 2.418 83.704 19.182 ;
    LAYER M5 ;
     RECT  19.92 0.016 73.608 1.091 ;
     RECT  20.016 1.091 73.608 1.763 ;
     RECT  20.208 1.763 73.608 1.811 ;
     RECT  20.208 1.811 73.512 1.859 ;
     RECT  20.208 1.859 73.32 1.955 ;
     RECT  2.4 2.137 2.52 2.151 ;
     RECT  7.8 2.137 7.92 2.151 ;
     RECT  13.2 2.137 13.32 2.151 ;
     RECT  18.6 2.137 18.72 2.151 ;
     RECT  78 2.137 78.12 2.151 ;
     RECT  83.4 2.137 83.52 2.151 ;
     RECT  20.208 1.955 35.112 2.291 ;
     RECT  36.336 1.955 73.32 2.291 ;
     RECT  20.208 2.291 27.72 2.867 ;
     RECT  28.992 2.291 35.112 3.349 ;
     RECT  60.432 2.291 72.912 3.491 ;
     RECT  60.432 3.491 64.584 3.587 ;
     RECT  20.88 2.867 27.72 4.019 ;
     RECT  28.992 3.349 35.256 4.019 ;
     RECT  36.336 2.291 59.4 4.019 ;
     RECT  65.616 3.491 72.912 4.019 ;
     RECT  38.832 4.019 59.4 4.067 ;
     RECT  60.432 3.587 64.296 4.211 ;
     RECT  30.912 4.019 35.256 4.501 ;
     RECT  36.336 4.019 37.704 4.501 ;
     RECT  20.88 4.019 25.608 4.595 ;
     RECT  30.912 4.501 37.704 4.595 ;
     RECT  60.528 4.211 64.296 4.595 ;
     RECT  65.616 4.019 67.512 4.595 ;
     RECT  30.96 4.595 37.704 4.835 ;
     RECT  55.728 4.067 59.4 4.835 ;
     RECT  63.12 4.595 64.296 4.883 ;
     RECT  64.08 4.883 64.296 5.027 ;
     RECT  66.384 4.595 67.512 5.077 ;
     RECT  38.832 4.067 54.312 5.171 ;
     RECT  28.992 4.019 29.712 5.221 ;
     RECT  38.832 5.171 52.152 5.315 ;
     RECT  28.512 5.221 29.712 5.605 ;
     RECT  66.384 5.077 67.704 5.699 ;
     RECT  20.88 4.595 25.032 5.747 ;
     RECT  30.96 4.835 37.32 5.747 ;
     RECT  64.08 5.027 64.104 5.747 ;
     RECT  68.784 4.019 72.912 5.795 ;
     RECT  33.456 5.747 37.32 5.797 ;
     RECT  66.384 5.699 67.512 5.843 ;
     RECT  26.784 4.019 27.528 5.893 ;
     RECT  28.512 5.605 29.832 5.893 ;
     RECT  56.112 4.835 59.4 5.893 ;
     RECT  33.456 5.797 37.608 5.989 ;
     RECT  38.832 5.315 47.496 5.989 ;
     RECT  26.784 5.893 29.832 6.131 ;
     RECT  33.456 5.989 47.496 6.179 ;
     RECT  61.104 4.595 62.112 6.229 ;
     RECT  20.88 5.747 20.904 6.275 ;
     RECT  29.28 6.131 29.832 6.275 ;
     RECT  66.48 5.843 67.512 6.275 ;
     RECT  38.736 6.179 47.496 6.277 ;
     RECT  48.528 5.315 52.152 6.277 ;
     RECT  22.368 5.747 25.032 6.323 ;
     RECT  69.936 5.795 72.912 6.323 ;
     RECT  26.784 6.131 28.104 6.371 ;
     RECT  53.52 5.171 54.312 6.469 ;
     RECT  56.112 5.893 59.496 6.469 ;
     RECT  53.52 6.469 59.496 6.661 ;
     RECT  29.4 6.275 29.832 6.709 ;
     RECT  31.44 5.747 32.232 6.709 ;
     RECT  53.52 6.661 59.784 6.803 ;
     RECT  29.4 6.709 32.232 6.805 ;
     RECT  33.456 6.179 37.608 6.805 ;
     RECT  58.512 6.803 59.784 6.851 ;
     RECT  59.328 6.851 59.784 6.899 ;
     RECT  68.784 5.795 68.808 6.899 ;
     RECT  69.936 6.323 70.824 6.899 ;
     RECT  53.52 6.803 54.552 6.997 ;
     RECT  55.872 6.803 57.528 7.043 ;
     RECT  53.376 6.997 54.552 7.139 ;
     RECT  27.744 6.371 28.104 7.235 ;
     RECT  65.472 6.757 65.496 7.235 ;
     RECT  29.4 6.805 37.608 7.237 ;
     RECT  38.736 6.277 52.152 7.237 ;
     RECT  61.104 6.229 62.664 7.237 ;
     RECT  0.144 6.565 0.168 7.283 ;
     RECT  59.328 6.899 59.496 7.283 ;
     RECT  23.28 6.323 24.504 7.475 ;
     RECT  56.304 7.043 57.528 7.475 ;
     RECT  69.936 6.899 69.96 7.475 ;
     RECT  29.4 7.237 52.152 7.573 ;
     RECT  53.376 7.139 53.976 7.573 ;
     RECT  24 7.475 24.504 7.909 ;
     RECT  29.4 7.573 53.976 8.003 ;
     RECT  29.4 8.003 53.112 8.099 ;
     RECT  61.056 7.237 62.664 8.435 ;
     RECT  27.744 7.235 27.768 8.437 ;
     RECT  29.4 8.099 52.2 8.437 ;
     RECT  27.744 8.437 52.2 9.203 ;
     RECT  27.744 9.203 51.912 11.603 ;
     RECT  59.328 7.283 59.352 11.653 ;
     RECT  47.184 11.603 51.912 12.179 ;
     RECT  56.4 7.475 57.528 12.517 ;
     RECT  59.328 11.653 60.168 12.517 ;
     RECT  54.624 8.437 54.648 13.045 ;
     RECT  54.624 13.045 55.032 13.285 ;
     RECT  47.184 12.179 49.56 13.331 ;
     RECT  51 12.179 51.912 13.909 ;
     RECT  47.232 13.331 49.56 14.197 ;
     RECT  47.232 14.197 49.848 14.245 ;
     RECT  51 13.909 52.152 14.245 ;
     RECT  27.744 11.603 46.2 14.771 ;
     RECT  56.4 12.517 60.168 15.205 ;
     RECT  53.952 13.285 55.032 15.301 ;
     RECT  61.8 8.435 62.664 15.301 ;
     RECT  56.208 15.205 60.168 15.349 ;
     RECT  61.632 15.301 62.664 15.349 ;
     RECT  26.688 6.805 26.712 15.973 ;
     RECT  47.232 14.245 52.152 16.021 ;
     RECT  17.568 5.989 17.592 16.357 ;
     RECT  18.6 2.151 18.912 16.357 ;
     RECT  27.744 14.771 46.008 16.405 ;
     RECT  17.568 16.357 18.912 16.549 ;
     RECT  27.744 16.405 46.104 16.595 ;
     RECT  17.568 16.549 19.752 16.597 ;
     RECT  47.232 16.021 52.776 16.597 ;
     RECT  53.952 15.301 55.08 16.597 ;
     RECT  29.232 16.595 46.104 16.837 ;
     RECT  47.232 16.597 55.08 16.837 ;
     RECT  26.352 15.973 26.712 17.029 ;
     RECT  17.568 16.597 19.944 17.123 ;
     RECT  24 7.909 25.08 17.123 ;
     RECT  26.16 17.029 26.712 17.845 ;
     RECT  27.696 17.557 27.72 17.845 ;
     RECT  24 17.123 24.552 18.133 ;
     RECT  18.336 17.123 19.944 18.229 ;
     RECT  21.072 15.349 21.096 18.229 ;
     RECT  23.856 18.133 24.552 18.421 ;
     RECT  18.336 18.229 21.096 18.661 ;
     RECT  65.808 17.077 65.832 18.709 ;
     RECT  15.024 18.133 15.048 18.757 ;
     RECT  18.336 18.661 21.24 18.757 ;
     RECT  29.232 16.837 55.08 18.757 ;
     RECT  56.208 15.349 62.664 18.757 ;
     RECT  13.2 2.151 13.512 18.805 ;
     RECT  15.024 18.757 15.816 18.805 ;
     RECT  17.856 18.757 21.24 18.805 ;
     RECT  26.16 17.845 27.72 18.805 ;
     RECT  29.232 18.757 62.664 18.805 ;
     RECT  65.424 18.709 65.832 18.805 ;
     RECT  65.424 18.805 66.024 18.853 ;
     RECT  13.2 18.805 16.488 18.997 ;
     RECT  17.856 18.805 22.056 18.997 ;
     RECT  13.2 18.997 22.056 19.093 ;
     RECT  64.752 18.853 66.024 19.189 ;
     RECT  67.2 6.275 67.512 19.189 ;
     RECT  13.2 19.093 22.728 19.237 ;
     RECT  23.856 18.421 25.176 19.237 ;
     RECT  64.368 19.189 67.512 19.237 ;
     RECT  13.2 19.237 25.176 19.333 ;
     RECT  26.16 18.805 62.664 19.333 ;
     RECT  63.792 19.237 67.512 19.333 ;
     RECT  2.4 2.151 2.712 19.449 ;
     RECT  7.8 2.151 8.112 19.449 ;
     RECT  12.912 19.333 67.512 19.449 ;
     RECT  72.6 6.323 72.912 19.449 ;
     RECT  78 2.151 78.312 19.449 ;
     RECT  83.4 2.151 83.712 19.449 ;
     RECT  2.4 19.449 2.52 19.463 ;
     RECT  7.8 19.449 7.92 19.463 ;
     RECT  12.912 19.449 67.32 19.463 ;
     RECT  72.6 19.449 72.72 19.463 ;
     RECT  78 19.449 78.12 19.463 ;
     RECT  83.4 19.449 83.52 19.463 ;
     RECT  12.912 19.463 66.408 20.437 ;
     RECT  12.816 20.437 66.408 20.485 ;
     RECT  12.72 20.485 66.408 21.584 ;
     RECT  19.92 1.091 20.016 1.763 ;
     RECT  19.92 1.763 20.208 2.137 ;
     RECT  35.112 1.955 36.336 3.349 ;
     RECT  18.72 2.137 20.208 2.151 ;
     RECT  18.912 2.151 20.208 2.867 ;
     RECT  27.72 2.291 28.992 4.019 ;
     RECT  59.4 2.291 60.432 4.211 ;
     RECT  35.256 3.349 36.336 4.501 ;
     RECT  64.584 3.491 65.616 3.587 ;
     RECT  64.296 3.587 65.616 4.595 ;
     RECT  25.608 4.019 26.784 4.595 ;
     RECT  27.528 4.019 28.992 5.221 ;
     RECT  29.712 4.019 30.912 4.595 ;
     RECT  37.704 4.019 38.832 4.835 ;
     RECT  67.512 4.019 68.784 5.077 ;
     RECT  54.312 4.067 55.728 4.835 ;
     RECT  59.4 4.211 60.528 4.595 ;
     RECT  29.712 4.595 30.96 5.605 ;
     RECT  59.4 4.595 59.496 5.893 ;
     RECT  62.112 4.595 63.12 4.883 ;
     RECT  37.32 4.835 38.832 5.797 ;
     RECT  62.112 4.883 64.08 5.747 ;
     RECT  67.704 5.077 68.784 5.699 ;
     RECT  52.152 5.171 53.52 6.997 ;
     RECT  27.528 5.221 28.512 5.893 ;
     RECT  47.496 5.315 48.528 6.277 ;
     RECT  29.832 5.605 30.96 5.747 ;
     RECT  67.512 5.699 68.784 6.899 ;
     RECT  20.904 5.747 22.368 6.275 ;
     RECT  29.832 5.747 31.44 6.709 ;
     RECT  32.232 5.747 33.456 6.805 ;
     RECT  62.112 5.747 62.664 6.229 ;
     RECT  68.808 5.795 69.936 6.899 ;
     RECT  37.608 5.797 38.832 5.989 ;
     RECT  17.592 5.989 18.6 16.357 ;
     RECT  28.104 6.131 29.28 6.275 ;
     RECT  37.608 6.179 38.736 7.237 ;
     RECT  28.104 6.275 29.4 7.235 ;
     RECT  26.784 6.371 27.744 6.805 ;
     RECT  59.784 6.661 61.104 6.899 ;
     RECT  54.552 6.803 55.872 7.043 ;
     RECT  57.528 6.803 58.512 6.851 ;
     RECT  26.712 6.805 27.744 16.595 ;
     RECT  61.056 6.899 61.104 7.237 ;
     RECT  52.152 6.997 53.376 7.573 ;
     RECT  54.552 7.043 54.648 7.139 ;
     RECT  53.976 7.139 54.648 8.003 ;
     RECT  27.768 7.235 29.4 8.437 ;
     RECT  53.112 8.003 54.648 8.099 ;
     RECT  54.624 8.099 54.648 8.437 ;
     RECT  46.2 11.603 47.184 13.331 ;
     RECT  49.56 12.179 51 14.197 ;
     RECT  55.032 13.045 56.4 15.205 ;
     RECT  46.2 13.331 47.232 14.771 ;
     RECT  49.848 14.197 51 14.245 ;
     RECT  46.008 14.771 47.232 16.405 ;
     RECT  55.032 15.205 56.208 15.301 ;
     RECT  55.08 15.301 56.208 18.757 ;
     RECT  60.168 15.301 61.632 15.349 ;
     RECT  25.08 15.973 26.352 17.029 ;
     RECT  52.776 16.021 53.952 16.597 ;
     RECT  46.104 16.405 47.232 16.837 ;
     RECT  19.752 16.549 21.072 16.597 ;
     RECT  26.712 16.595 29.232 17.557 ;
     RECT  19.944 16.597 21.072 18.229 ;
     RECT  25.08 17.029 26.16 17.123 ;
     RECT  65.832 17.077 67.2 18.805 ;
     RECT  24.552 17.123 26.16 18.421 ;
     RECT  26.712 17.557 27.696 17.845 ;
     RECT  27.72 17.557 29.232 18.805 ;
     RECT  13.512 18.133 15.024 18.805 ;
     RECT  25.176 18.421 26.16 19.333 ;
     RECT  16.488 18.805 17.856 18.997 ;
     RECT  66.024 18.805 67.2 19.189 ;
     RECT  22.728 19.093 23.856 19.237 ;
     RECT  62.664 19.237 63.792 19.333 ;
  END
END ot_qkvd_ke_tf
END LIBRARY
